VERSION 5.7 ;
BUSBITCHARS "[]" ;
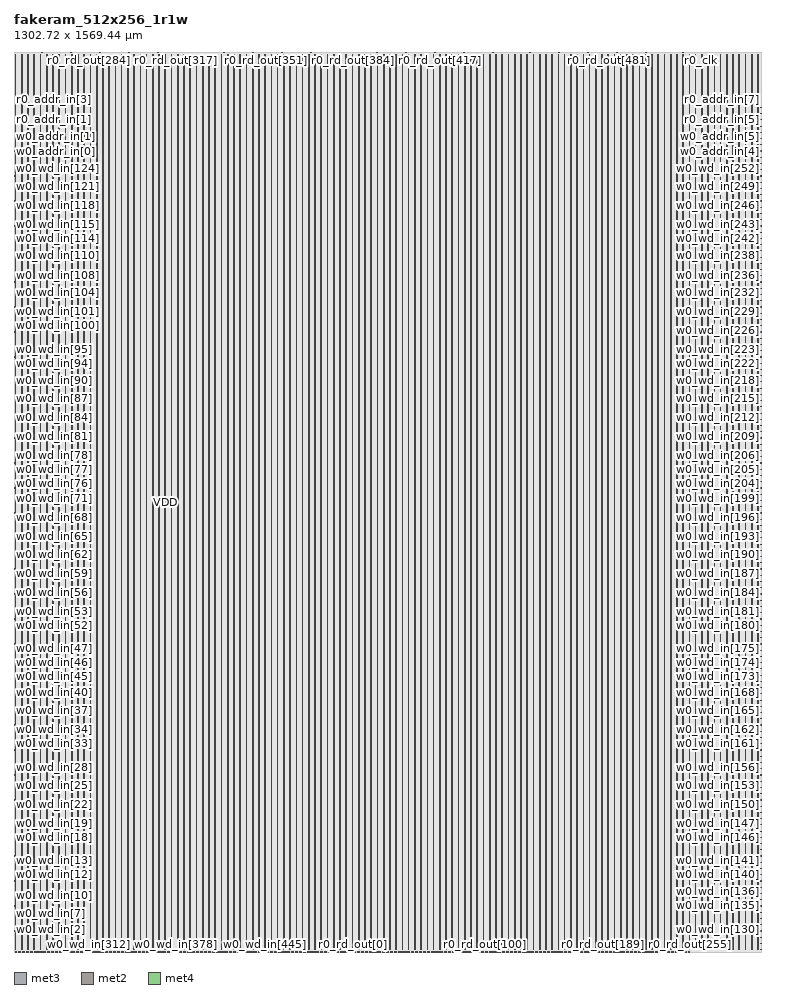
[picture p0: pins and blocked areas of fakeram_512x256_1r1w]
MACRO fakeram_512x256_1r1w
  FOREIGN fakeram_512x256_1r1w 0 0 ;
  SYMMETRY X Y R90 ;
  SIZE 1302.720 BY 1569.440 ;
  CLASS BLOCK ;
  PIN w0_wd_in[0]
    DIRECTION INPUT ;
    USE SIGNAL ;
    SHAPE ABUTMENT ;
    PORT
      LAYER met3 ;
      RECT 0.000 3.930 0.900 4.230 ;
    END
  END w0_wd_in[0]
  PIN w0_wd_in[1]
    DIRECTION INPUT ;
    USE SIGNAL ;
    SHAPE ABUTMENT ;
    PORT
      LAYER met3 ;
      RECT 0.000 14.810 0.900 15.110 ;
    END
  END w0_wd_in[1]
  PIN w0_wd_in[2]
    DIRECTION INPUT ;
    USE SIGNAL ;
    SHAPE ABUTMENT ;
    PORT
      LAYER met3 ;
      RECT 0.000 25.690 0.900 25.990 ;
    END
  END w0_wd_in[2]
  PIN w0_wd_in[3]
    DIRECTION INPUT ;
    USE SIGNAL ;
    SHAPE ABUTMENT ;
    PORT
      LAYER met3 ;
      RECT 0.000 36.570 0.900 36.870 ;
    END
  END w0_wd_in[3]
  PIN w0_wd_in[4]
    DIRECTION INPUT ;
    USE SIGNAL ;
    SHAPE ABUTMENT ;
    PORT
      LAYER met3 ;
      RECT 0.000 47.450 0.900 47.750 ;
    END
  END w0_wd_in[4]
  PIN w0_wd_in[5]
    DIRECTION INPUT ;
    USE SIGNAL ;
    SHAPE ABUTMENT ;
    PORT
      LAYER met3 ;
      RECT 0.000 58.330 0.900 58.630 ;
    END
  END w0_wd_in[5]
  PIN w0_wd_in[6]
    DIRECTION INPUT ;
    USE SIGNAL ;
    SHAPE ABUTMENT ;
    PORT
      LAYER met3 ;
      RECT 0.000 69.210 0.900 69.510 ;
    END
  END w0_wd_in[6]
  PIN w0_wd_in[7]
    DIRECTION INPUT ;
    USE SIGNAL ;
    SHAPE ABUTMENT ;
    PORT
      LAYER met3 ;
      RECT 0.000 80.090 0.900 80.390 ;
    END
  END w0_wd_in[7]
  PIN w0_wd_in[8]
    DIRECTION INPUT ;
    USE SIGNAL ;
    SHAPE ABUTMENT ;
    PORT
      LAYER met3 ;
      RECT 0.000 90.970 0.900 91.270 ;
    END
  END w0_wd_in[8]
  PIN w0_wd_in[9]
    DIRECTION INPUT ;
    USE SIGNAL ;
    SHAPE ABUTMENT ;
    PORT
      LAYER met3 ;
      RECT 0.000 101.850 0.900 102.150 ;
    END
  END w0_wd_in[9]
  PIN w0_wd_in[10]
    DIRECTION INPUT ;
    USE SIGNAL ;
    SHAPE ABUTMENT ;
    PORT
      LAYER met3 ;
      RECT 0.000 112.730 0.900 113.030 ;
    END
  END w0_wd_in[10]
  PIN w0_wd_in[11]
    DIRECTION INPUT ;
    USE SIGNAL ;
    SHAPE ABUTMENT ;
    PORT
      LAYER met3 ;
      RECT 0.000 123.610 0.900 123.910 ;
    END
  END w0_wd_in[11]
  PIN w0_wd_in[12]
    DIRECTION INPUT ;
    USE SIGNAL ;
    SHAPE ABUTMENT ;
    PORT
      LAYER met3 ;
      RECT 0.000 134.490 0.900 134.790 ;
    END
  END w0_wd_in[12]
  PIN w0_wd_in[13]
    DIRECTION INPUT ;
    USE SIGNAL ;
    SHAPE ABUTMENT ;
    PORT
      LAYER met3 ;
      RECT 0.000 145.370 0.900 145.670 ;
    END
  END w0_wd_in[13]
  PIN w0_wd_in[14]
    DIRECTION INPUT ;
    USE SIGNAL ;
    SHAPE ABUTMENT ;
    PORT
      LAYER met3 ;
      RECT 0.000 156.250 0.900 156.550 ;
    END
  END w0_wd_in[14]
  PIN w0_wd_in[15]
    DIRECTION INPUT ;
    USE SIGNAL ;
    SHAPE ABUTMENT ;
    PORT
      LAYER met3 ;
      RECT 0.000 167.130 0.900 167.430 ;
    END
  END w0_wd_in[15]
  PIN w0_wd_in[16]
    DIRECTION INPUT ;
    USE SIGNAL ;
    SHAPE ABUTMENT ;
    PORT
      LAYER met3 ;
      RECT 0.000 178.010 0.900 178.310 ;
    END
  END w0_wd_in[16]
  PIN w0_wd_in[17]
    DIRECTION INPUT ;
    USE SIGNAL ;
    SHAPE ABUTMENT ;
    PORT
      LAYER met3 ;
      RECT 0.000 188.890 0.900 189.190 ;
    END
  END w0_wd_in[17]
  PIN w0_wd_in[18]
    DIRECTION INPUT ;
    USE SIGNAL ;
    SHAPE ABUTMENT ;
    PORT
      LAYER met3 ;
      RECT 0.000 199.770 0.900 200.070 ;
    END
  END w0_wd_in[18]
  PIN w0_wd_in[19]
    DIRECTION INPUT ;
    USE SIGNAL ;
    SHAPE ABUTMENT ;
    PORT
      LAYER met3 ;
      RECT 0.000 210.650 0.900 210.950 ;
    END
  END w0_wd_in[19]
  PIN w0_wd_in[20]
    DIRECTION INPUT ;
    USE SIGNAL ;
    SHAPE ABUTMENT ;
    PORT
      LAYER met3 ;
      RECT 0.000 221.530 0.900 221.830 ;
    END
  END w0_wd_in[20]
  PIN w0_wd_in[21]
    DIRECTION INPUT ;
    USE SIGNAL ;
    SHAPE ABUTMENT ;
    PORT
      LAYER met3 ;
      RECT 0.000 232.410 0.900 232.710 ;
    END
  END w0_wd_in[21]
  PIN w0_wd_in[22]
    DIRECTION INPUT ;
    USE SIGNAL ;
    SHAPE ABUTMENT ;
    PORT
      LAYER met3 ;
      RECT 0.000 243.290 0.900 243.590 ;
    END
  END w0_wd_in[22]
  PIN w0_wd_in[23]
    DIRECTION INPUT ;
    USE SIGNAL ;
    SHAPE ABUTMENT ;
    PORT
      LAYER met3 ;
      RECT 0.000 254.170 0.900 254.470 ;
    END
  END w0_wd_in[23]
  PIN w0_wd_in[24]
    DIRECTION INPUT ;
    USE SIGNAL ;
    SHAPE ABUTMENT ;
    PORT
      LAYER met3 ;
      RECT 0.000 265.050 0.900 265.350 ;
    END
  END w0_wd_in[24]
  PIN w0_wd_in[25]
    DIRECTION INPUT ;
    USE SIGNAL ;
    SHAPE ABUTMENT ;
    PORT
      LAYER met3 ;
      RECT 0.000 275.930 0.900 276.230 ;
    END
  END w0_wd_in[25]
  PIN w0_wd_in[26]
    DIRECTION INPUT ;
    USE SIGNAL ;
    SHAPE ABUTMENT ;
    PORT
      LAYER met3 ;
      RECT 0.000 286.810 0.900 287.110 ;
    END
  END w0_wd_in[26]
  PIN w0_wd_in[27]
    DIRECTION INPUT ;
    USE SIGNAL ;
    SHAPE ABUTMENT ;
    PORT
      LAYER met3 ;
      RECT 0.000 297.690 0.900 297.990 ;
    END
  END w0_wd_in[27]
  PIN w0_wd_in[28]
    DIRECTION INPUT ;
    USE SIGNAL ;
    SHAPE ABUTMENT ;
    PORT
      LAYER met3 ;
      RECT 0.000 308.570 0.900 308.870 ;
    END
  END w0_wd_in[28]
  PIN w0_wd_in[29]
    DIRECTION INPUT ;
    USE SIGNAL ;
    SHAPE ABUTMENT ;
    PORT
      LAYER met3 ;
      RECT 0.000 319.450 0.900 319.750 ;
    END
  END w0_wd_in[29]
  PIN w0_wd_in[30]
    DIRECTION INPUT ;
    USE SIGNAL ;
    SHAPE ABUTMENT ;
    PORT
      LAYER met3 ;
      RECT 0.000 330.330 0.900 330.630 ;
    END
  END w0_wd_in[30]
  PIN w0_wd_in[31]
    DIRECTION INPUT ;
    USE SIGNAL ;
    SHAPE ABUTMENT ;
    PORT
      LAYER met3 ;
      RECT 0.000 341.210 0.900 341.510 ;
    END
  END w0_wd_in[31]
  PIN w0_wd_in[32]
    DIRECTION INPUT ;
    USE SIGNAL ;
    SHAPE ABUTMENT ;
    PORT
      LAYER met3 ;
      RECT 0.000 352.090 0.900 352.390 ;
    END
  END w0_wd_in[32]
  PIN w0_wd_in[33]
    DIRECTION INPUT ;
    USE SIGNAL ;
    SHAPE ABUTMENT ;
    PORT
      LAYER met3 ;
      RECT 0.000 362.970 0.900 363.270 ;
    END
  END w0_wd_in[33]
  PIN w0_wd_in[34]
    DIRECTION INPUT ;
    USE SIGNAL ;
    SHAPE ABUTMENT ;
    PORT
      LAYER met3 ;
      RECT 0.000 373.850 0.900 374.150 ;
    END
  END w0_wd_in[34]
  PIN w0_wd_in[35]
    DIRECTION INPUT ;
    USE SIGNAL ;
    SHAPE ABUTMENT ;
    PORT
      LAYER met3 ;
      RECT 0.000 384.730 0.900 385.030 ;
    END
  END w0_wd_in[35]
  PIN w0_wd_in[36]
    DIRECTION INPUT ;
    USE SIGNAL ;
    SHAPE ABUTMENT ;
    PORT
      LAYER met3 ;
      RECT 0.000 395.610 0.900 395.910 ;
    END
  END w0_wd_in[36]
  PIN w0_wd_in[37]
    DIRECTION INPUT ;
    USE SIGNAL ;
    SHAPE ABUTMENT ;
    PORT
      LAYER met3 ;
      RECT 0.000 406.490 0.900 406.790 ;
    END
  END w0_wd_in[37]
  PIN w0_wd_in[38]
    DIRECTION INPUT ;
    USE SIGNAL ;
    SHAPE ABUTMENT ;
    PORT
      LAYER met3 ;
      RECT 0.000 417.370 0.900 417.670 ;
    END
  END w0_wd_in[38]
  PIN w0_wd_in[39]
    DIRECTION INPUT ;
    USE SIGNAL ;
    SHAPE ABUTMENT ;
    PORT
      LAYER met3 ;
      RECT 0.000 428.250 0.900 428.550 ;
    END
  END w0_wd_in[39]
  PIN w0_wd_in[40]
    DIRECTION INPUT ;
    USE SIGNAL ;
    SHAPE ABUTMENT ;
    PORT
      LAYER met3 ;
      RECT 0.000 439.130 0.900 439.430 ;
    END
  END w0_wd_in[40]
  PIN w0_wd_in[41]
    DIRECTION INPUT ;
    USE SIGNAL ;
    SHAPE ABUTMENT ;
    PORT
      LAYER met3 ;
      RECT 0.000 450.010 0.900 450.310 ;
    END
  END w0_wd_in[41]
  PIN w0_wd_in[42]
    DIRECTION INPUT ;
    USE SIGNAL ;
    SHAPE ABUTMENT ;
    PORT
      LAYER met3 ;
      RECT 0.000 460.890 0.900 461.190 ;
    END
  END w0_wd_in[42]
  PIN w0_wd_in[43]
    DIRECTION INPUT ;
    USE SIGNAL ;
    SHAPE ABUTMENT ;
    PORT
      LAYER met3 ;
      RECT 0.000 471.770 0.900 472.070 ;
    END
  END w0_wd_in[43]
  PIN w0_wd_in[44]
    DIRECTION INPUT ;
    USE SIGNAL ;
    SHAPE ABUTMENT ;
    PORT
      LAYER met3 ;
      RECT 0.000 482.650 0.900 482.950 ;
    END
  END w0_wd_in[44]
  PIN w0_wd_in[45]
    DIRECTION INPUT ;
    USE SIGNAL ;
    SHAPE ABUTMENT ;
    PORT
      LAYER met3 ;
      RECT 0.000 493.530 0.900 493.830 ;
    END
  END w0_wd_in[45]
  PIN w0_wd_in[46]
    DIRECTION INPUT ;
    USE SIGNAL ;
    SHAPE ABUTMENT ;
    PORT
      LAYER met3 ;
      RECT 0.000 504.410 0.900 504.710 ;
    END
  END w0_wd_in[46]
  PIN w0_wd_in[47]
    DIRECTION INPUT ;
    USE SIGNAL ;
    SHAPE ABUTMENT ;
    PORT
      LAYER met3 ;
      RECT 0.000 515.290 0.900 515.590 ;
    END
  END w0_wd_in[47]
  PIN w0_wd_in[48]
    DIRECTION INPUT ;
    USE SIGNAL ;
    SHAPE ABUTMENT ;
    PORT
      LAYER met3 ;
      RECT 0.000 526.170 0.900 526.470 ;
    END
  END w0_wd_in[48]
  PIN w0_wd_in[49]
    DIRECTION INPUT ;
    USE SIGNAL ;
    SHAPE ABUTMENT ;
    PORT
      LAYER met3 ;
      RECT 0.000 537.050 0.900 537.350 ;
    END
  END w0_wd_in[49]
  PIN w0_wd_in[50]
    DIRECTION INPUT ;
    USE SIGNAL ;
    SHAPE ABUTMENT ;
    PORT
      LAYER met3 ;
      RECT 0.000 547.930 0.900 548.230 ;
    END
  END w0_wd_in[50]
  PIN w0_wd_in[51]
    DIRECTION INPUT ;
    USE SIGNAL ;
    SHAPE ABUTMENT ;
    PORT
      LAYER met3 ;
      RECT 0.000 558.810 0.900 559.110 ;
    END
  END w0_wd_in[51]
  PIN w0_wd_in[52]
    DIRECTION INPUT ;
    USE SIGNAL ;
    SHAPE ABUTMENT ;
    PORT
      LAYER met3 ;
      RECT 0.000 569.690 0.900 569.990 ;
    END
  END w0_wd_in[52]
  PIN w0_wd_in[53]
    DIRECTION INPUT ;
    USE SIGNAL ;
    SHAPE ABUTMENT ;
    PORT
      LAYER met3 ;
      RECT 0.000 580.570 0.900 580.870 ;
    END
  END w0_wd_in[53]
  PIN w0_wd_in[54]
    DIRECTION INPUT ;
    USE SIGNAL ;
    SHAPE ABUTMENT ;
    PORT
      LAYER met3 ;
      RECT 0.000 591.450 0.900 591.750 ;
    END
  END w0_wd_in[54]
  PIN w0_wd_in[55]
    DIRECTION INPUT ;
    USE SIGNAL ;
    SHAPE ABUTMENT ;
    PORT
      LAYER met3 ;
      RECT 0.000 602.330 0.900 602.630 ;
    END
  END w0_wd_in[55]
  PIN w0_wd_in[56]
    DIRECTION INPUT ;
    USE SIGNAL ;
    SHAPE ABUTMENT ;
    PORT
      LAYER met3 ;
      RECT 0.000 613.210 0.900 613.510 ;
    END
  END w0_wd_in[56]
  PIN w0_wd_in[57]
    DIRECTION INPUT ;
    USE SIGNAL ;
    SHAPE ABUTMENT ;
    PORT
      LAYER met3 ;
      RECT 0.000 624.090 0.900 624.390 ;
    END
  END w0_wd_in[57]
  PIN w0_wd_in[58]
    DIRECTION INPUT ;
    USE SIGNAL ;
    SHAPE ABUTMENT ;
    PORT
      LAYER met3 ;
      RECT 0.000 634.970 0.900 635.270 ;
    END
  END w0_wd_in[58]
  PIN w0_wd_in[59]
    DIRECTION INPUT ;
    USE SIGNAL ;
    SHAPE ABUTMENT ;
    PORT
      LAYER met3 ;
      RECT 0.000 645.850 0.900 646.150 ;
    END
  END w0_wd_in[59]
  PIN w0_wd_in[60]
    DIRECTION INPUT ;
    USE SIGNAL ;
    SHAPE ABUTMENT ;
    PORT
      LAYER met3 ;
      RECT 0.000 656.730 0.900 657.030 ;
    END
  END w0_wd_in[60]
  PIN w0_wd_in[61]
    DIRECTION INPUT ;
    USE SIGNAL ;
    SHAPE ABUTMENT ;
    PORT
      LAYER met3 ;
      RECT 0.000 667.610 0.900 667.910 ;
    END
  END w0_wd_in[61]
  PIN w0_wd_in[62]
    DIRECTION INPUT ;
    USE SIGNAL ;
    SHAPE ABUTMENT ;
    PORT
      LAYER met3 ;
      RECT 0.000 678.490 0.900 678.790 ;
    END
  END w0_wd_in[62]
  PIN w0_wd_in[63]
    DIRECTION INPUT ;
    USE SIGNAL ;
    SHAPE ABUTMENT ;
    PORT
      LAYER met3 ;
      RECT 0.000 689.370 0.900 689.670 ;
    END
  END w0_wd_in[63]
  PIN w0_wd_in[64]
    DIRECTION INPUT ;
    USE SIGNAL ;
    SHAPE ABUTMENT ;
    PORT
      LAYER met3 ;
      RECT 0.000 700.250 0.900 700.550 ;
    END
  END w0_wd_in[64]
  PIN w0_wd_in[65]
    DIRECTION INPUT ;
    USE SIGNAL ;
    SHAPE ABUTMENT ;
    PORT
      LAYER met3 ;
      RECT 0.000 711.130 0.900 711.430 ;
    END
  END w0_wd_in[65]
  PIN w0_wd_in[66]
    DIRECTION INPUT ;
    USE SIGNAL ;
    SHAPE ABUTMENT ;
    PORT
      LAYER met3 ;
      RECT 0.000 722.010 0.900 722.310 ;
    END
  END w0_wd_in[66]
  PIN w0_wd_in[67]
    DIRECTION INPUT ;
    USE SIGNAL ;
    SHAPE ABUTMENT ;
    PORT
      LAYER met3 ;
      RECT 0.000 732.890 0.900 733.190 ;
    END
  END w0_wd_in[67]
  PIN w0_wd_in[68]
    DIRECTION INPUT ;
    USE SIGNAL ;
    SHAPE ABUTMENT ;
    PORT
      LAYER met3 ;
      RECT 0.000 743.770 0.900 744.070 ;
    END
  END w0_wd_in[68]
  PIN w0_wd_in[69]
    DIRECTION INPUT ;
    USE SIGNAL ;
    SHAPE ABUTMENT ;
    PORT
      LAYER met3 ;
      RECT 0.000 754.650 0.900 754.950 ;
    END
  END w0_wd_in[69]
  PIN w0_wd_in[70]
    DIRECTION INPUT ;
    USE SIGNAL ;
    SHAPE ABUTMENT ;
    PORT
      LAYER met3 ;
      RECT 0.000 765.530 0.900 765.830 ;
    END
  END w0_wd_in[70]
  PIN w0_wd_in[71]
    DIRECTION INPUT ;
    USE SIGNAL ;
    SHAPE ABUTMENT ;
    PORT
      LAYER met3 ;
      RECT 0.000 776.410 0.900 776.710 ;
    END
  END w0_wd_in[71]
  PIN w0_wd_in[72]
    DIRECTION INPUT ;
    USE SIGNAL ;
    SHAPE ABUTMENT ;
    PORT
      LAYER met3 ;
      RECT 0.000 787.290 0.900 787.590 ;
    END
  END w0_wd_in[72]
  PIN w0_wd_in[73]
    DIRECTION INPUT ;
    USE SIGNAL ;
    SHAPE ABUTMENT ;
    PORT
      LAYER met3 ;
      RECT 0.000 798.170 0.900 798.470 ;
    END
  END w0_wd_in[73]
  PIN w0_wd_in[74]
    DIRECTION INPUT ;
    USE SIGNAL ;
    SHAPE ABUTMENT ;
    PORT
      LAYER met3 ;
      RECT 0.000 809.050 0.900 809.350 ;
    END
  END w0_wd_in[74]
  PIN w0_wd_in[75]
    DIRECTION INPUT ;
    USE SIGNAL ;
    SHAPE ABUTMENT ;
    PORT
      LAYER met3 ;
      RECT 0.000 819.930 0.900 820.230 ;
    END
  END w0_wd_in[75]
  PIN w0_wd_in[76]
    DIRECTION INPUT ;
    USE SIGNAL ;
    SHAPE ABUTMENT ;
    PORT
      LAYER met3 ;
      RECT 0.000 830.810 0.900 831.110 ;
    END
  END w0_wd_in[76]
  PIN w0_wd_in[77]
    DIRECTION INPUT ;
    USE SIGNAL ;
    SHAPE ABUTMENT ;
    PORT
      LAYER met3 ;
      RECT 0.000 841.690 0.900 841.990 ;
    END
  END w0_wd_in[77]
  PIN w0_wd_in[78]
    DIRECTION INPUT ;
    USE SIGNAL ;
    SHAPE ABUTMENT ;
    PORT
      LAYER met3 ;
      RECT 0.000 852.570 0.900 852.870 ;
    END
  END w0_wd_in[78]
  PIN w0_wd_in[79]
    DIRECTION INPUT ;
    USE SIGNAL ;
    SHAPE ABUTMENT ;
    PORT
      LAYER met3 ;
      RECT 0.000 863.450 0.900 863.750 ;
    END
  END w0_wd_in[79]
  PIN w0_wd_in[80]
    DIRECTION INPUT ;
    USE SIGNAL ;
    SHAPE ABUTMENT ;
    PORT
      LAYER met3 ;
      RECT 0.000 874.330 0.900 874.630 ;
    END
  END w0_wd_in[80]
  PIN w0_wd_in[81]
    DIRECTION INPUT ;
    USE SIGNAL ;
    SHAPE ABUTMENT ;
    PORT
      LAYER met3 ;
      RECT 0.000 885.210 0.900 885.510 ;
    END
  END w0_wd_in[81]
  PIN w0_wd_in[82]
    DIRECTION INPUT ;
    USE SIGNAL ;
    SHAPE ABUTMENT ;
    PORT
      LAYER met3 ;
      RECT 0.000 896.090 0.900 896.390 ;
    END
  END w0_wd_in[82]
  PIN w0_wd_in[83]
    DIRECTION INPUT ;
    USE SIGNAL ;
    SHAPE ABUTMENT ;
    PORT
      LAYER met3 ;
      RECT 0.000 906.970 0.900 907.270 ;
    END
  END w0_wd_in[83]
  PIN w0_wd_in[84]
    DIRECTION INPUT ;
    USE SIGNAL ;
    SHAPE ABUTMENT ;
    PORT
      LAYER met3 ;
      RECT 0.000 917.850 0.900 918.150 ;
    END
  END w0_wd_in[84]
  PIN w0_wd_in[85]
    DIRECTION INPUT ;
    USE SIGNAL ;
    SHAPE ABUTMENT ;
    PORT
      LAYER met3 ;
      RECT 0.000 928.730 0.900 929.030 ;
    END
  END w0_wd_in[85]
  PIN w0_wd_in[86]
    DIRECTION INPUT ;
    USE SIGNAL ;
    SHAPE ABUTMENT ;
    PORT
      LAYER met3 ;
      RECT 0.000 939.610 0.900 939.910 ;
    END
  END w0_wd_in[86]
  PIN w0_wd_in[87]
    DIRECTION INPUT ;
    USE SIGNAL ;
    SHAPE ABUTMENT ;
    PORT
      LAYER met3 ;
      RECT 0.000 950.490 0.900 950.790 ;
    END
  END w0_wd_in[87]
  PIN w0_wd_in[88]
    DIRECTION INPUT ;
    USE SIGNAL ;
    SHAPE ABUTMENT ;
    PORT
      LAYER met3 ;
      RECT 0.000 961.370 0.900 961.670 ;
    END
  END w0_wd_in[88]
  PIN w0_wd_in[89]
    DIRECTION INPUT ;
    USE SIGNAL ;
    SHAPE ABUTMENT ;
    PORT
      LAYER met3 ;
      RECT 0.000 972.250 0.900 972.550 ;
    END
  END w0_wd_in[89]
  PIN w0_wd_in[90]
    DIRECTION INPUT ;
    USE SIGNAL ;
    SHAPE ABUTMENT ;
    PORT
      LAYER met3 ;
      RECT 0.000 983.130 0.900 983.430 ;
    END
  END w0_wd_in[90]
  PIN w0_wd_in[91]
    DIRECTION INPUT ;
    USE SIGNAL ;
    SHAPE ABUTMENT ;
    PORT
      LAYER met3 ;
      RECT 0.000 994.010 0.900 994.310 ;
    END
  END w0_wd_in[91]
  PIN w0_wd_in[92]
    DIRECTION INPUT ;
    USE SIGNAL ;
    SHAPE ABUTMENT ;
    PORT
      LAYER met3 ;
      RECT 0.000 1004.890 0.900 1005.190 ;
    END
  END w0_wd_in[92]
  PIN w0_wd_in[93]
    DIRECTION INPUT ;
    USE SIGNAL ;
    SHAPE ABUTMENT ;
    PORT
      LAYER met3 ;
      RECT 0.000 1015.770 0.900 1016.070 ;
    END
  END w0_wd_in[93]
  PIN w0_wd_in[94]
    DIRECTION INPUT ;
    USE SIGNAL ;
    SHAPE ABUTMENT ;
    PORT
      LAYER met3 ;
      RECT 0.000 1026.650 0.900 1026.950 ;
    END
  END w0_wd_in[94]
  PIN w0_wd_in[95]
    DIRECTION INPUT ;
    USE SIGNAL ;
    SHAPE ABUTMENT ;
    PORT
      LAYER met3 ;
      RECT 0.000 1037.530 0.900 1037.830 ;
    END
  END w0_wd_in[95]
  PIN w0_wd_in[96]
    DIRECTION INPUT ;
    USE SIGNAL ;
    SHAPE ABUTMENT ;
    PORT
      LAYER met3 ;
      RECT 0.000 1048.410 0.900 1048.710 ;
    END
  END w0_wd_in[96]
  PIN w0_wd_in[97]
    DIRECTION INPUT ;
    USE SIGNAL ;
    SHAPE ABUTMENT ;
    PORT
      LAYER met3 ;
      RECT 0.000 1059.290 0.900 1059.590 ;
    END
  END w0_wd_in[97]
  PIN w0_wd_in[98]
    DIRECTION INPUT ;
    USE SIGNAL ;
    SHAPE ABUTMENT ;
    PORT
      LAYER met3 ;
      RECT 0.000 1070.170 0.900 1070.470 ;
    END
  END w0_wd_in[98]
  PIN w0_wd_in[99]
    DIRECTION INPUT ;
    USE SIGNAL ;
    SHAPE ABUTMENT ;
    PORT
      LAYER met3 ;
      RECT 0.000 1081.050 0.900 1081.350 ;
    END
  END w0_wd_in[99]
  PIN w0_wd_in[100]
    DIRECTION INPUT ;
    USE SIGNAL ;
    SHAPE ABUTMENT ;
    PORT
      LAYER met3 ;
      RECT 0.000 1091.930 0.900 1092.230 ;
    END
  END w0_wd_in[100]
  PIN w0_wd_in[101]
    DIRECTION INPUT ;
    USE SIGNAL ;
    SHAPE ABUTMENT ;
    PORT
      LAYER met3 ;
      RECT 0.000 1102.810 0.900 1103.110 ;
    END
  END w0_wd_in[101]
  PIN w0_wd_in[102]
    DIRECTION INPUT ;
    USE SIGNAL ;
    SHAPE ABUTMENT ;
    PORT
      LAYER met3 ;
      RECT 0.000 1113.690 0.900 1113.990 ;
    END
  END w0_wd_in[102]
  PIN w0_wd_in[103]
    DIRECTION INPUT ;
    USE SIGNAL ;
    SHAPE ABUTMENT ;
    PORT
      LAYER met3 ;
      RECT 0.000 1124.570 0.900 1124.870 ;
    END
  END w0_wd_in[103]
  PIN w0_wd_in[104]
    DIRECTION INPUT ;
    USE SIGNAL ;
    SHAPE ABUTMENT ;
    PORT
      LAYER met3 ;
      RECT 0.000 1135.450 0.900 1135.750 ;
    END
  END w0_wd_in[104]
  PIN w0_wd_in[105]
    DIRECTION INPUT ;
    USE SIGNAL ;
    SHAPE ABUTMENT ;
    PORT
      LAYER met3 ;
      RECT 0.000 1146.330 0.900 1146.630 ;
    END
  END w0_wd_in[105]
  PIN w0_wd_in[106]
    DIRECTION INPUT ;
    USE SIGNAL ;
    SHAPE ABUTMENT ;
    PORT
      LAYER met3 ;
      RECT 0.000 1157.210 0.900 1157.510 ;
    END
  END w0_wd_in[106]
  PIN w0_wd_in[107]
    DIRECTION INPUT ;
    USE SIGNAL ;
    SHAPE ABUTMENT ;
    PORT
      LAYER met3 ;
      RECT 0.000 1168.090 0.900 1168.390 ;
    END
  END w0_wd_in[107]
  PIN w0_wd_in[108]
    DIRECTION INPUT ;
    USE SIGNAL ;
    SHAPE ABUTMENT ;
    PORT
      LAYER met3 ;
      RECT 0.000 1178.970 0.900 1179.270 ;
    END
  END w0_wd_in[108]
  PIN w0_wd_in[109]
    DIRECTION INPUT ;
    USE SIGNAL ;
    SHAPE ABUTMENT ;
    PORT
      LAYER met3 ;
      RECT 0.000 1189.850 0.900 1190.150 ;
    END
  END w0_wd_in[109]
  PIN w0_wd_in[110]
    DIRECTION INPUT ;
    USE SIGNAL ;
    SHAPE ABUTMENT ;
    PORT
      LAYER met3 ;
      RECT 0.000 1200.730 0.900 1201.030 ;
    END
  END w0_wd_in[110]
  PIN w0_wd_in[111]
    DIRECTION INPUT ;
    USE SIGNAL ;
    SHAPE ABUTMENT ;
    PORT
      LAYER met3 ;
      RECT 0.000 1211.610 0.900 1211.910 ;
    END
  END w0_wd_in[111]
  PIN w0_wd_in[112]
    DIRECTION INPUT ;
    USE SIGNAL ;
    SHAPE ABUTMENT ;
    PORT
      LAYER met3 ;
      RECT 0.000 1222.490 0.900 1222.790 ;
    END
  END w0_wd_in[112]
  PIN w0_wd_in[113]
    DIRECTION INPUT ;
    USE SIGNAL ;
    SHAPE ABUTMENT ;
    PORT
      LAYER met3 ;
      RECT 0.000 1233.370 0.900 1233.670 ;
    END
  END w0_wd_in[113]
  PIN w0_wd_in[114]
    DIRECTION INPUT ;
    USE SIGNAL ;
    SHAPE ABUTMENT ;
    PORT
      LAYER met3 ;
      RECT 0.000 1244.250 0.900 1244.550 ;
    END
  END w0_wd_in[114]
  PIN w0_wd_in[115]
    DIRECTION INPUT ;
    USE SIGNAL ;
    SHAPE ABUTMENT ;
    PORT
      LAYER met3 ;
      RECT 0.000 1255.130 0.900 1255.430 ;
    END
  END w0_wd_in[115]
  PIN w0_wd_in[116]
    DIRECTION INPUT ;
    USE SIGNAL ;
    SHAPE ABUTMENT ;
    PORT
      LAYER met3 ;
      RECT 0.000 1266.010 0.900 1266.310 ;
    END
  END w0_wd_in[116]
  PIN w0_wd_in[117]
    DIRECTION INPUT ;
    USE SIGNAL ;
    SHAPE ABUTMENT ;
    PORT
      LAYER met3 ;
      RECT 0.000 1276.890 0.900 1277.190 ;
    END
  END w0_wd_in[117]
  PIN w0_wd_in[118]
    DIRECTION INPUT ;
    USE SIGNAL ;
    SHAPE ABUTMENT ;
    PORT
      LAYER met3 ;
      RECT 0.000 1287.770 0.900 1288.070 ;
    END
  END w0_wd_in[118]
  PIN w0_wd_in[119]
    DIRECTION INPUT ;
    USE SIGNAL ;
    SHAPE ABUTMENT ;
    PORT
      LAYER met3 ;
      RECT 0.000 1298.650 0.900 1298.950 ;
    END
  END w0_wd_in[119]
  PIN w0_wd_in[120]
    DIRECTION INPUT ;
    USE SIGNAL ;
    SHAPE ABUTMENT ;
    PORT
      LAYER met3 ;
      RECT 0.000 1309.530 0.900 1309.830 ;
    END
  END w0_wd_in[120]
  PIN w0_wd_in[121]
    DIRECTION INPUT ;
    USE SIGNAL ;
    SHAPE ABUTMENT ;
    PORT
      LAYER met3 ;
      RECT 0.000 1320.410 0.900 1320.710 ;
    END
  END w0_wd_in[121]
  PIN w0_wd_in[122]
    DIRECTION INPUT ;
    USE SIGNAL ;
    SHAPE ABUTMENT ;
    PORT
      LAYER met3 ;
      RECT 0.000 1331.290 0.900 1331.590 ;
    END
  END w0_wd_in[122]
  PIN w0_wd_in[123]
    DIRECTION INPUT ;
    USE SIGNAL ;
    SHAPE ABUTMENT ;
    PORT
      LAYER met3 ;
      RECT 0.000 1342.170 0.900 1342.470 ;
    END
  END w0_wd_in[123]
  PIN w0_wd_in[124]
    DIRECTION INPUT ;
    USE SIGNAL ;
    SHAPE ABUTMENT ;
    PORT
      LAYER met3 ;
      RECT 0.000 1353.050 0.900 1353.350 ;
    END
  END w0_wd_in[124]
  PIN w0_wd_in[125]
    DIRECTION INPUT ;
    USE SIGNAL ;
    SHAPE ABUTMENT ;
    PORT
      LAYER met3 ;
      RECT 0.000 1363.930 0.900 1364.230 ;
    END
  END w0_wd_in[125]
  PIN w0_wd_in[126]
    DIRECTION INPUT ;
    USE SIGNAL ;
    SHAPE ABUTMENT ;
    PORT
      LAYER met3 ;
      RECT 0.000 1374.810 0.900 1375.110 ;
    END
  END w0_wd_in[126]
  PIN w0_wd_in[127]
    DIRECTION INPUT ;
    USE SIGNAL ;
    SHAPE ABUTMENT ;
    PORT
      LAYER met3 ;
      RECT 0.000 1385.690 0.900 1385.990 ;
    END
  END w0_wd_in[127]
  PIN w0_wd_in[128]
    DIRECTION INPUT ;
    USE SIGNAL ;
    SHAPE ABUTMENT ;
    PORT
      LAYER met3 ;
      RECT 1301.820 3.930 1302.720 4.230 ;
    END
  END w0_wd_in[128]
  PIN w0_wd_in[129]
    DIRECTION INPUT ;
    USE SIGNAL ;
    SHAPE ABUTMENT ;
    PORT
      LAYER met3 ;
      RECT 1301.820 14.810 1302.720 15.110 ;
    END
  END w0_wd_in[129]
  PIN w0_wd_in[130]
    DIRECTION INPUT ;
    USE SIGNAL ;
    SHAPE ABUTMENT ;
    PORT
      LAYER met3 ;
      RECT 1301.820 25.690 1302.720 25.990 ;
    END
  END w0_wd_in[130]
  PIN w0_wd_in[131]
    DIRECTION INPUT ;
    USE SIGNAL ;
    SHAPE ABUTMENT ;
    PORT
      LAYER met3 ;
      RECT 1301.820 36.570 1302.720 36.870 ;
    END
  END w0_wd_in[131]
  PIN w0_wd_in[132]
    DIRECTION INPUT ;
    USE SIGNAL ;
    SHAPE ABUTMENT ;
    PORT
      LAYER met3 ;
      RECT 1301.820 47.450 1302.720 47.750 ;
    END
  END w0_wd_in[132]
  PIN w0_wd_in[133]
    DIRECTION INPUT ;
    USE SIGNAL ;
    SHAPE ABUTMENT ;
    PORT
      LAYER met3 ;
      RECT 1301.820 58.330 1302.720 58.630 ;
    END
  END w0_wd_in[133]
  PIN w0_wd_in[134]
    DIRECTION INPUT ;
    USE SIGNAL ;
    SHAPE ABUTMENT ;
    PORT
      LAYER met3 ;
      RECT 1301.820 69.210 1302.720 69.510 ;
    END
  END w0_wd_in[134]
  PIN w0_wd_in[135]
    DIRECTION INPUT ;
    USE SIGNAL ;
    SHAPE ABUTMENT ;
    PORT
      LAYER met3 ;
      RECT 1301.820 80.090 1302.720 80.390 ;
    END
  END w0_wd_in[135]
  PIN w0_wd_in[136]
    DIRECTION INPUT ;
    USE SIGNAL ;
    SHAPE ABUTMENT ;
    PORT
      LAYER met3 ;
      RECT 1301.820 90.970 1302.720 91.270 ;
    END
  END w0_wd_in[136]
  PIN w0_wd_in[137]
    DIRECTION INPUT ;
    USE SIGNAL ;
    SHAPE ABUTMENT ;
    PORT
      LAYER met3 ;
      RECT 1301.820 101.850 1302.720 102.150 ;
    END
  END w0_wd_in[137]
  PIN w0_wd_in[138]
    DIRECTION INPUT ;
    USE SIGNAL ;
    SHAPE ABUTMENT ;
    PORT
      LAYER met3 ;
      RECT 1301.820 112.730 1302.720 113.030 ;
    END
  END w0_wd_in[138]
  PIN w0_wd_in[139]
    DIRECTION INPUT ;
    USE SIGNAL ;
    SHAPE ABUTMENT ;
    PORT
      LAYER met3 ;
      RECT 1301.820 123.610 1302.720 123.910 ;
    END
  END w0_wd_in[139]
  PIN w0_wd_in[140]
    DIRECTION INPUT ;
    USE SIGNAL ;
    SHAPE ABUTMENT ;
    PORT
      LAYER met3 ;
      RECT 1301.820 134.490 1302.720 134.790 ;
    END
  END w0_wd_in[140]
  PIN w0_wd_in[141]
    DIRECTION INPUT ;
    USE SIGNAL ;
    SHAPE ABUTMENT ;
    PORT
      LAYER met3 ;
      RECT 1301.820 145.370 1302.720 145.670 ;
    END
  END w0_wd_in[141]
  PIN w0_wd_in[142]
    DIRECTION INPUT ;
    USE SIGNAL ;
    SHAPE ABUTMENT ;
    PORT
      LAYER met3 ;
      RECT 1301.820 156.250 1302.720 156.550 ;
    END
  END w0_wd_in[142]
  PIN w0_wd_in[143]
    DIRECTION INPUT ;
    USE SIGNAL ;
    SHAPE ABUTMENT ;
    PORT
      LAYER met3 ;
      RECT 1301.820 167.130 1302.720 167.430 ;
    END
  END w0_wd_in[143]
  PIN w0_wd_in[144]
    DIRECTION INPUT ;
    USE SIGNAL ;
    SHAPE ABUTMENT ;
    PORT
      LAYER met3 ;
      RECT 1301.820 178.010 1302.720 178.310 ;
    END
  END w0_wd_in[144]
  PIN w0_wd_in[145]
    DIRECTION INPUT ;
    USE SIGNAL ;
    SHAPE ABUTMENT ;
    PORT
      LAYER met3 ;
      RECT 1301.820 188.890 1302.720 189.190 ;
    END
  END w0_wd_in[145]
  PIN w0_wd_in[146]
    DIRECTION INPUT ;
    USE SIGNAL ;
    SHAPE ABUTMENT ;
    PORT
      LAYER met3 ;
      RECT 1301.820 199.770 1302.720 200.070 ;
    END
  END w0_wd_in[146]
  PIN w0_wd_in[147]
    DIRECTION INPUT ;
    USE SIGNAL ;
    SHAPE ABUTMENT ;
    PORT
      LAYER met3 ;
      RECT 1301.820 210.650 1302.720 210.950 ;
    END
  END w0_wd_in[147]
  PIN w0_wd_in[148]
    DIRECTION INPUT ;
    USE SIGNAL ;
    SHAPE ABUTMENT ;
    PORT
      LAYER met3 ;
      RECT 1301.820 221.530 1302.720 221.830 ;
    END
  END w0_wd_in[148]
  PIN w0_wd_in[149]
    DIRECTION INPUT ;
    USE SIGNAL ;
    SHAPE ABUTMENT ;
    PORT
      LAYER met3 ;
      RECT 1301.820 232.410 1302.720 232.710 ;
    END
  END w0_wd_in[149]
  PIN w0_wd_in[150]
    DIRECTION INPUT ;
    USE SIGNAL ;
    SHAPE ABUTMENT ;
    PORT
      LAYER met3 ;
      RECT 1301.820 243.290 1302.720 243.590 ;
    END
  END w0_wd_in[150]
  PIN w0_wd_in[151]
    DIRECTION INPUT ;
    USE SIGNAL ;
    SHAPE ABUTMENT ;
    PORT
      LAYER met3 ;
      RECT 1301.820 254.170 1302.720 254.470 ;
    END
  END w0_wd_in[151]
  PIN w0_wd_in[152]
    DIRECTION INPUT ;
    USE SIGNAL ;
    SHAPE ABUTMENT ;
    PORT
      LAYER met3 ;
      RECT 1301.820 265.050 1302.720 265.350 ;
    END
  END w0_wd_in[152]
  PIN w0_wd_in[153]
    DIRECTION INPUT ;
    USE SIGNAL ;
    SHAPE ABUTMENT ;
    PORT
      LAYER met3 ;
      RECT 1301.820 275.930 1302.720 276.230 ;
    END
  END w0_wd_in[153]
  PIN w0_wd_in[154]
    DIRECTION INPUT ;
    USE SIGNAL ;
    SHAPE ABUTMENT ;
    PORT
      LAYER met3 ;
      RECT 1301.820 286.810 1302.720 287.110 ;
    END
  END w0_wd_in[154]
  PIN w0_wd_in[155]
    DIRECTION INPUT ;
    USE SIGNAL ;
    SHAPE ABUTMENT ;
    PORT
      LAYER met3 ;
      RECT 1301.820 297.690 1302.720 297.990 ;
    END
  END w0_wd_in[155]
  PIN w0_wd_in[156]
    DIRECTION INPUT ;
    USE SIGNAL ;
    SHAPE ABUTMENT ;
    PORT
      LAYER met3 ;
      RECT 1301.820 308.570 1302.720 308.870 ;
    END
  END w0_wd_in[156]
  PIN w0_wd_in[157]
    DIRECTION INPUT ;
    USE SIGNAL ;
    SHAPE ABUTMENT ;
    PORT
      LAYER met3 ;
      RECT 1301.820 319.450 1302.720 319.750 ;
    END
  END w0_wd_in[157]
  PIN w0_wd_in[158]
    DIRECTION INPUT ;
    USE SIGNAL ;
    SHAPE ABUTMENT ;
    PORT
      LAYER met3 ;
      RECT 1301.820 330.330 1302.720 330.630 ;
    END
  END w0_wd_in[158]
  PIN w0_wd_in[159]
    DIRECTION INPUT ;
    USE SIGNAL ;
    SHAPE ABUTMENT ;
    PORT
      LAYER met3 ;
      RECT 1301.820 341.210 1302.720 341.510 ;
    END
  END w0_wd_in[159]
  PIN w0_wd_in[160]
    DIRECTION INPUT ;
    USE SIGNAL ;
    SHAPE ABUTMENT ;
    PORT
      LAYER met3 ;
      RECT 1301.820 352.090 1302.720 352.390 ;
    END
  END w0_wd_in[160]
  PIN w0_wd_in[161]
    DIRECTION INPUT ;
    USE SIGNAL ;
    SHAPE ABUTMENT ;
    PORT
      LAYER met3 ;
      RECT 1301.820 362.970 1302.720 363.270 ;
    END
  END w0_wd_in[161]
  PIN w0_wd_in[162]
    DIRECTION INPUT ;
    USE SIGNAL ;
    SHAPE ABUTMENT ;
    PORT
      LAYER met3 ;
      RECT 1301.820 373.850 1302.720 374.150 ;
    END
  END w0_wd_in[162]
  PIN w0_wd_in[163]
    DIRECTION INPUT ;
    USE SIGNAL ;
    SHAPE ABUTMENT ;
    PORT
      LAYER met3 ;
      RECT 1301.820 384.730 1302.720 385.030 ;
    END
  END w0_wd_in[163]
  PIN w0_wd_in[164]
    DIRECTION INPUT ;
    USE SIGNAL ;
    SHAPE ABUTMENT ;
    PORT
      LAYER met3 ;
      RECT 1301.820 395.610 1302.720 395.910 ;
    END
  END w0_wd_in[164]
  PIN w0_wd_in[165]
    DIRECTION INPUT ;
    USE SIGNAL ;
    SHAPE ABUTMENT ;
    PORT
      LAYER met3 ;
      RECT 1301.820 406.490 1302.720 406.790 ;
    END
  END w0_wd_in[165]
  PIN w0_wd_in[166]
    DIRECTION INPUT ;
    USE SIGNAL ;
    SHAPE ABUTMENT ;
    PORT
      LAYER met3 ;
      RECT 1301.820 417.370 1302.720 417.670 ;
    END
  END w0_wd_in[166]
  PIN w0_wd_in[167]
    DIRECTION INPUT ;
    USE SIGNAL ;
    SHAPE ABUTMENT ;
    PORT
      LAYER met3 ;
      RECT 1301.820 428.250 1302.720 428.550 ;
    END
  END w0_wd_in[167]
  PIN w0_wd_in[168]
    DIRECTION INPUT ;
    USE SIGNAL ;
    SHAPE ABUTMENT ;
    PORT
      LAYER met3 ;
      RECT 1301.820 439.130 1302.720 439.430 ;
    END
  END w0_wd_in[168]
  PIN w0_wd_in[169]
    DIRECTION INPUT ;
    USE SIGNAL ;
    SHAPE ABUTMENT ;
    PORT
      LAYER met3 ;
      RECT 1301.820 450.010 1302.720 450.310 ;
    END
  END w0_wd_in[169]
  PIN w0_wd_in[170]
    DIRECTION INPUT ;
    USE SIGNAL ;
    SHAPE ABUTMENT ;
    PORT
      LAYER met3 ;
      RECT 1301.820 460.890 1302.720 461.190 ;
    END
  END w0_wd_in[170]
  PIN w0_wd_in[171]
    DIRECTION INPUT ;
    USE SIGNAL ;
    SHAPE ABUTMENT ;
    PORT
      LAYER met3 ;
      RECT 1301.820 471.770 1302.720 472.070 ;
    END
  END w0_wd_in[171]
  PIN w0_wd_in[172]
    DIRECTION INPUT ;
    USE SIGNAL ;
    SHAPE ABUTMENT ;
    PORT
      LAYER met3 ;
      RECT 1301.820 482.650 1302.720 482.950 ;
    END
  END w0_wd_in[172]
  PIN w0_wd_in[173]
    DIRECTION INPUT ;
    USE SIGNAL ;
    SHAPE ABUTMENT ;
    PORT
      LAYER met3 ;
      RECT 1301.820 493.530 1302.720 493.830 ;
    END
  END w0_wd_in[173]
  PIN w0_wd_in[174]
    DIRECTION INPUT ;
    USE SIGNAL ;
    SHAPE ABUTMENT ;
    PORT
      LAYER met3 ;
      RECT 1301.820 504.410 1302.720 504.710 ;
    END
  END w0_wd_in[174]
  PIN w0_wd_in[175]
    DIRECTION INPUT ;
    USE SIGNAL ;
    SHAPE ABUTMENT ;
    PORT
      LAYER met3 ;
      RECT 1301.820 515.290 1302.720 515.590 ;
    END
  END w0_wd_in[175]
  PIN w0_wd_in[176]
    DIRECTION INPUT ;
    USE SIGNAL ;
    SHAPE ABUTMENT ;
    PORT
      LAYER met3 ;
      RECT 1301.820 526.170 1302.720 526.470 ;
    END
  END w0_wd_in[176]
  PIN w0_wd_in[177]
    DIRECTION INPUT ;
    USE SIGNAL ;
    SHAPE ABUTMENT ;
    PORT
      LAYER met3 ;
      RECT 1301.820 537.050 1302.720 537.350 ;
    END
  END w0_wd_in[177]
  PIN w0_wd_in[178]
    DIRECTION INPUT ;
    USE SIGNAL ;
    SHAPE ABUTMENT ;
    PORT
      LAYER met3 ;
      RECT 1301.820 547.930 1302.720 548.230 ;
    END
  END w0_wd_in[178]
  PIN w0_wd_in[179]
    DIRECTION INPUT ;
    USE SIGNAL ;
    SHAPE ABUTMENT ;
    PORT
      LAYER met3 ;
      RECT 1301.820 558.810 1302.720 559.110 ;
    END
  END w0_wd_in[179]
  PIN w0_wd_in[180]
    DIRECTION INPUT ;
    USE SIGNAL ;
    SHAPE ABUTMENT ;
    PORT
      LAYER met3 ;
      RECT 1301.820 569.690 1302.720 569.990 ;
    END
  END w0_wd_in[180]
  PIN w0_wd_in[181]
    DIRECTION INPUT ;
    USE SIGNAL ;
    SHAPE ABUTMENT ;
    PORT
      LAYER met3 ;
      RECT 1301.820 580.570 1302.720 580.870 ;
    END
  END w0_wd_in[181]
  PIN w0_wd_in[182]
    DIRECTION INPUT ;
    USE SIGNAL ;
    SHAPE ABUTMENT ;
    PORT
      LAYER met3 ;
      RECT 1301.820 591.450 1302.720 591.750 ;
    END
  END w0_wd_in[182]
  PIN w0_wd_in[183]
    DIRECTION INPUT ;
    USE SIGNAL ;
    SHAPE ABUTMENT ;
    PORT
      LAYER met3 ;
      RECT 1301.820 602.330 1302.720 602.630 ;
    END
  END w0_wd_in[183]
  PIN w0_wd_in[184]
    DIRECTION INPUT ;
    USE SIGNAL ;
    SHAPE ABUTMENT ;
    PORT
      LAYER met3 ;
      RECT 1301.820 613.210 1302.720 613.510 ;
    END
  END w0_wd_in[184]
  PIN w0_wd_in[185]
    DIRECTION INPUT ;
    USE SIGNAL ;
    SHAPE ABUTMENT ;
    PORT
      LAYER met3 ;
      RECT 1301.820 624.090 1302.720 624.390 ;
    END
  END w0_wd_in[185]
  PIN w0_wd_in[186]
    DIRECTION INPUT ;
    USE SIGNAL ;
    SHAPE ABUTMENT ;
    PORT
      LAYER met3 ;
      RECT 1301.820 634.970 1302.720 635.270 ;
    END
  END w0_wd_in[186]
  PIN w0_wd_in[187]
    DIRECTION INPUT ;
    USE SIGNAL ;
    SHAPE ABUTMENT ;
    PORT
      LAYER met3 ;
      RECT 1301.820 645.850 1302.720 646.150 ;
    END
  END w0_wd_in[187]
  PIN w0_wd_in[188]
    DIRECTION INPUT ;
    USE SIGNAL ;
    SHAPE ABUTMENT ;
    PORT
      LAYER met3 ;
      RECT 1301.820 656.730 1302.720 657.030 ;
    END
  END w0_wd_in[188]
  PIN w0_wd_in[189]
    DIRECTION INPUT ;
    USE SIGNAL ;
    SHAPE ABUTMENT ;
    PORT
      LAYER met3 ;
      RECT 1301.820 667.610 1302.720 667.910 ;
    END
  END w0_wd_in[189]
  PIN w0_wd_in[190]
    DIRECTION INPUT ;
    USE SIGNAL ;
    SHAPE ABUTMENT ;
    PORT
      LAYER met3 ;
      RECT 1301.820 678.490 1302.720 678.790 ;
    END
  END w0_wd_in[190]
  PIN w0_wd_in[191]
    DIRECTION INPUT ;
    USE SIGNAL ;
    SHAPE ABUTMENT ;
    PORT
      LAYER met3 ;
      RECT 1301.820 689.370 1302.720 689.670 ;
    END
  END w0_wd_in[191]
  PIN w0_wd_in[192]
    DIRECTION INPUT ;
    USE SIGNAL ;
    SHAPE ABUTMENT ;
    PORT
      LAYER met3 ;
      RECT 1301.820 700.250 1302.720 700.550 ;
    END
  END w0_wd_in[192]
  PIN w0_wd_in[193]
    DIRECTION INPUT ;
    USE SIGNAL ;
    SHAPE ABUTMENT ;
    PORT
      LAYER met3 ;
      RECT 1301.820 711.130 1302.720 711.430 ;
    END
  END w0_wd_in[193]
  PIN w0_wd_in[194]
    DIRECTION INPUT ;
    USE SIGNAL ;
    SHAPE ABUTMENT ;
    PORT
      LAYER met3 ;
      RECT 1301.820 722.010 1302.720 722.310 ;
    END
  END w0_wd_in[194]
  PIN w0_wd_in[195]
    DIRECTION INPUT ;
    USE SIGNAL ;
    SHAPE ABUTMENT ;
    PORT
      LAYER met3 ;
      RECT 1301.820 732.890 1302.720 733.190 ;
    END
  END w0_wd_in[195]
  PIN w0_wd_in[196]
    DIRECTION INPUT ;
    USE SIGNAL ;
    SHAPE ABUTMENT ;
    PORT
      LAYER met3 ;
      RECT 1301.820 743.770 1302.720 744.070 ;
    END
  END w0_wd_in[196]
  PIN w0_wd_in[197]
    DIRECTION INPUT ;
    USE SIGNAL ;
    SHAPE ABUTMENT ;
    PORT
      LAYER met3 ;
      RECT 1301.820 754.650 1302.720 754.950 ;
    END
  END w0_wd_in[197]
  PIN w0_wd_in[198]
    DIRECTION INPUT ;
    USE SIGNAL ;
    SHAPE ABUTMENT ;
    PORT
      LAYER met3 ;
      RECT 1301.820 765.530 1302.720 765.830 ;
    END
  END w0_wd_in[198]
  PIN w0_wd_in[199]
    DIRECTION INPUT ;
    USE SIGNAL ;
    SHAPE ABUTMENT ;
    PORT
      LAYER met3 ;
      RECT 1301.820 776.410 1302.720 776.710 ;
    END
  END w0_wd_in[199]
  PIN w0_wd_in[200]
    DIRECTION INPUT ;
    USE SIGNAL ;
    SHAPE ABUTMENT ;
    PORT
      LAYER met3 ;
      RECT 1301.820 787.290 1302.720 787.590 ;
    END
  END w0_wd_in[200]
  PIN w0_wd_in[201]
    DIRECTION INPUT ;
    USE SIGNAL ;
    SHAPE ABUTMENT ;
    PORT
      LAYER met3 ;
      RECT 1301.820 798.170 1302.720 798.470 ;
    END
  END w0_wd_in[201]
  PIN w0_wd_in[202]
    DIRECTION INPUT ;
    USE SIGNAL ;
    SHAPE ABUTMENT ;
    PORT
      LAYER met3 ;
      RECT 1301.820 809.050 1302.720 809.350 ;
    END
  END w0_wd_in[202]
  PIN w0_wd_in[203]
    DIRECTION INPUT ;
    USE SIGNAL ;
    SHAPE ABUTMENT ;
    PORT
      LAYER met3 ;
      RECT 1301.820 819.930 1302.720 820.230 ;
    END
  END w0_wd_in[203]
  PIN w0_wd_in[204]
    DIRECTION INPUT ;
    USE SIGNAL ;
    SHAPE ABUTMENT ;
    PORT
      LAYER met3 ;
      RECT 1301.820 830.810 1302.720 831.110 ;
    END
  END w0_wd_in[204]
  PIN w0_wd_in[205]
    DIRECTION INPUT ;
    USE SIGNAL ;
    SHAPE ABUTMENT ;
    PORT
      LAYER met3 ;
      RECT 1301.820 841.690 1302.720 841.990 ;
    END
  END w0_wd_in[205]
  PIN w0_wd_in[206]
    DIRECTION INPUT ;
    USE SIGNAL ;
    SHAPE ABUTMENT ;
    PORT
      LAYER met3 ;
      RECT 1301.820 852.570 1302.720 852.870 ;
    END
  END w0_wd_in[206]
  PIN w0_wd_in[207]
    DIRECTION INPUT ;
    USE SIGNAL ;
    SHAPE ABUTMENT ;
    PORT
      LAYER met3 ;
      RECT 1301.820 863.450 1302.720 863.750 ;
    END
  END w0_wd_in[207]
  PIN w0_wd_in[208]
    DIRECTION INPUT ;
    USE SIGNAL ;
    SHAPE ABUTMENT ;
    PORT
      LAYER met3 ;
      RECT 1301.820 874.330 1302.720 874.630 ;
    END
  END w0_wd_in[208]
  PIN w0_wd_in[209]
    DIRECTION INPUT ;
    USE SIGNAL ;
    SHAPE ABUTMENT ;
    PORT
      LAYER met3 ;
      RECT 1301.820 885.210 1302.720 885.510 ;
    END
  END w0_wd_in[209]
  PIN w0_wd_in[210]
    DIRECTION INPUT ;
    USE SIGNAL ;
    SHAPE ABUTMENT ;
    PORT
      LAYER met3 ;
      RECT 1301.820 896.090 1302.720 896.390 ;
    END
  END w0_wd_in[210]
  PIN w0_wd_in[211]
    DIRECTION INPUT ;
    USE SIGNAL ;
    SHAPE ABUTMENT ;
    PORT
      LAYER met3 ;
      RECT 1301.820 906.970 1302.720 907.270 ;
    END
  END w0_wd_in[211]
  PIN w0_wd_in[212]
    DIRECTION INPUT ;
    USE SIGNAL ;
    SHAPE ABUTMENT ;
    PORT
      LAYER met3 ;
      RECT 1301.820 917.850 1302.720 918.150 ;
    END
  END w0_wd_in[212]
  PIN w0_wd_in[213]
    DIRECTION INPUT ;
    USE SIGNAL ;
    SHAPE ABUTMENT ;
    PORT
      LAYER met3 ;
      RECT 1301.820 928.730 1302.720 929.030 ;
    END
  END w0_wd_in[213]
  PIN w0_wd_in[214]
    DIRECTION INPUT ;
    USE SIGNAL ;
    SHAPE ABUTMENT ;
    PORT
      LAYER met3 ;
      RECT 1301.820 939.610 1302.720 939.910 ;
    END
  END w0_wd_in[214]
  PIN w0_wd_in[215]
    DIRECTION INPUT ;
    USE SIGNAL ;
    SHAPE ABUTMENT ;
    PORT
      LAYER met3 ;
      RECT 1301.820 950.490 1302.720 950.790 ;
    END
  END w0_wd_in[215]
  PIN w0_wd_in[216]
    DIRECTION INPUT ;
    USE SIGNAL ;
    SHAPE ABUTMENT ;
    PORT
      LAYER met3 ;
      RECT 1301.820 961.370 1302.720 961.670 ;
    END
  END w0_wd_in[216]
  PIN w0_wd_in[217]
    DIRECTION INPUT ;
    USE SIGNAL ;
    SHAPE ABUTMENT ;
    PORT
      LAYER met3 ;
      RECT 1301.820 972.250 1302.720 972.550 ;
    END
  END w0_wd_in[217]
  PIN w0_wd_in[218]
    DIRECTION INPUT ;
    USE SIGNAL ;
    SHAPE ABUTMENT ;
    PORT
      LAYER met3 ;
      RECT 1301.820 983.130 1302.720 983.430 ;
    END
  END w0_wd_in[218]
  PIN w0_wd_in[219]
    DIRECTION INPUT ;
    USE SIGNAL ;
    SHAPE ABUTMENT ;
    PORT
      LAYER met3 ;
      RECT 1301.820 994.010 1302.720 994.310 ;
    END
  END w0_wd_in[219]
  PIN w0_wd_in[220]
    DIRECTION INPUT ;
    USE SIGNAL ;
    SHAPE ABUTMENT ;
    PORT
      LAYER met3 ;
      RECT 1301.820 1004.890 1302.720 1005.190 ;
    END
  END w0_wd_in[220]
  PIN w0_wd_in[221]
    DIRECTION INPUT ;
    USE SIGNAL ;
    SHAPE ABUTMENT ;
    PORT
      LAYER met3 ;
      RECT 1301.820 1015.770 1302.720 1016.070 ;
    END
  END w0_wd_in[221]
  PIN w0_wd_in[222]
    DIRECTION INPUT ;
    USE SIGNAL ;
    SHAPE ABUTMENT ;
    PORT
      LAYER met3 ;
      RECT 1301.820 1026.650 1302.720 1026.950 ;
    END
  END w0_wd_in[222]
  PIN w0_wd_in[223]
    DIRECTION INPUT ;
    USE SIGNAL ;
    SHAPE ABUTMENT ;
    PORT
      LAYER met3 ;
      RECT 1301.820 1037.530 1302.720 1037.830 ;
    END
  END w0_wd_in[223]
  PIN w0_wd_in[224]
    DIRECTION INPUT ;
    USE SIGNAL ;
    SHAPE ABUTMENT ;
    PORT
      LAYER met3 ;
      RECT 1301.820 1048.410 1302.720 1048.710 ;
    END
  END w0_wd_in[224]
  PIN w0_wd_in[225]
    DIRECTION INPUT ;
    USE SIGNAL ;
    SHAPE ABUTMENT ;
    PORT
      LAYER met3 ;
      RECT 1301.820 1059.290 1302.720 1059.590 ;
    END
  END w0_wd_in[225]
  PIN w0_wd_in[226]
    DIRECTION INPUT ;
    USE SIGNAL ;
    SHAPE ABUTMENT ;
    PORT
      LAYER met3 ;
      RECT 1301.820 1070.170 1302.720 1070.470 ;
    END
  END w0_wd_in[226]
  PIN w0_wd_in[227]
    DIRECTION INPUT ;
    USE SIGNAL ;
    SHAPE ABUTMENT ;
    PORT
      LAYER met3 ;
      RECT 1301.820 1081.050 1302.720 1081.350 ;
    END
  END w0_wd_in[227]
  PIN w0_wd_in[228]
    DIRECTION INPUT ;
    USE SIGNAL ;
    SHAPE ABUTMENT ;
    PORT
      LAYER met3 ;
      RECT 1301.820 1091.930 1302.720 1092.230 ;
    END
  END w0_wd_in[228]
  PIN w0_wd_in[229]
    DIRECTION INPUT ;
    USE SIGNAL ;
    SHAPE ABUTMENT ;
    PORT
      LAYER met3 ;
      RECT 1301.820 1102.810 1302.720 1103.110 ;
    END
  END w0_wd_in[229]
  PIN w0_wd_in[230]
    DIRECTION INPUT ;
    USE SIGNAL ;
    SHAPE ABUTMENT ;
    PORT
      LAYER met3 ;
      RECT 1301.820 1113.690 1302.720 1113.990 ;
    END
  END w0_wd_in[230]
  PIN w0_wd_in[231]
    DIRECTION INPUT ;
    USE SIGNAL ;
    SHAPE ABUTMENT ;
    PORT
      LAYER met3 ;
      RECT 1301.820 1124.570 1302.720 1124.870 ;
    END
  END w0_wd_in[231]
  PIN w0_wd_in[232]
    DIRECTION INPUT ;
    USE SIGNAL ;
    SHAPE ABUTMENT ;
    PORT
      LAYER met3 ;
      RECT 1301.820 1135.450 1302.720 1135.750 ;
    END
  END w0_wd_in[232]
  PIN w0_wd_in[233]
    DIRECTION INPUT ;
    USE SIGNAL ;
    SHAPE ABUTMENT ;
    PORT
      LAYER met3 ;
      RECT 1301.820 1146.330 1302.720 1146.630 ;
    END
  END w0_wd_in[233]
  PIN w0_wd_in[234]
    DIRECTION INPUT ;
    USE SIGNAL ;
    SHAPE ABUTMENT ;
    PORT
      LAYER met3 ;
      RECT 1301.820 1157.210 1302.720 1157.510 ;
    END
  END w0_wd_in[234]
  PIN w0_wd_in[235]
    DIRECTION INPUT ;
    USE SIGNAL ;
    SHAPE ABUTMENT ;
    PORT
      LAYER met3 ;
      RECT 1301.820 1168.090 1302.720 1168.390 ;
    END
  END w0_wd_in[235]
  PIN w0_wd_in[236]
    DIRECTION INPUT ;
    USE SIGNAL ;
    SHAPE ABUTMENT ;
    PORT
      LAYER met3 ;
      RECT 1301.820 1178.970 1302.720 1179.270 ;
    END
  END w0_wd_in[236]
  PIN w0_wd_in[237]
    DIRECTION INPUT ;
    USE SIGNAL ;
    SHAPE ABUTMENT ;
    PORT
      LAYER met3 ;
      RECT 1301.820 1189.850 1302.720 1190.150 ;
    END
  END w0_wd_in[237]
  PIN w0_wd_in[238]
    DIRECTION INPUT ;
    USE SIGNAL ;
    SHAPE ABUTMENT ;
    PORT
      LAYER met3 ;
      RECT 1301.820 1200.730 1302.720 1201.030 ;
    END
  END w0_wd_in[238]
  PIN w0_wd_in[239]
    DIRECTION INPUT ;
    USE SIGNAL ;
    SHAPE ABUTMENT ;
    PORT
      LAYER met3 ;
      RECT 1301.820 1211.610 1302.720 1211.910 ;
    END
  END w0_wd_in[239]
  PIN w0_wd_in[240]
    DIRECTION INPUT ;
    USE SIGNAL ;
    SHAPE ABUTMENT ;
    PORT
      LAYER met3 ;
      RECT 1301.820 1222.490 1302.720 1222.790 ;
    END
  END w0_wd_in[240]
  PIN w0_wd_in[241]
    DIRECTION INPUT ;
    USE SIGNAL ;
    SHAPE ABUTMENT ;
    PORT
      LAYER met3 ;
      RECT 1301.820 1233.370 1302.720 1233.670 ;
    END
  END w0_wd_in[241]
  PIN w0_wd_in[242]
    DIRECTION INPUT ;
    USE SIGNAL ;
    SHAPE ABUTMENT ;
    PORT
      LAYER met3 ;
      RECT 1301.820 1244.250 1302.720 1244.550 ;
    END
  END w0_wd_in[242]
  PIN w0_wd_in[243]
    DIRECTION INPUT ;
    USE SIGNAL ;
    SHAPE ABUTMENT ;
    PORT
      LAYER met3 ;
      RECT 1301.820 1255.130 1302.720 1255.430 ;
    END
  END w0_wd_in[243]
  PIN w0_wd_in[244]
    DIRECTION INPUT ;
    USE SIGNAL ;
    SHAPE ABUTMENT ;
    PORT
      LAYER met3 ;
      RECT 1301.820 1266.010 1302.720 1266.310 ;
    END
  END w0_wd_in[244]
  PIN w0_wd_in[245]
    DIRECTION INPUT ;
    USE SIGNAL ;
    SHAPE ABUTMENT ;
    PORT
      LAYER met3 ;
      RECT 1301.820 1276.890 1302.720 1277.190 ;
    END
  END w0_wd_in[245]
  PIN w0_wd_in[246]
    DIRECTION INPUT ;
    USE SIGNAL ;
    SHAPE ABUTMENT ;
    PORT
      LAYER met3 ;
      RECT 1301.820 1287.770 1302.720 1288.070 ;
    END
  END w0_wd_in[246]
  PIN w0_wd_in[247]
    DIRECTION INPUT ;
    USE SIGNAL ;
    SHAPE ABUTMENT ;
    PORT
      LAYER met3 ;
      RECT 1301.820 1298.650 1302.720 1298.950 ;
    END
  END w0_wd_in[247]
  PIN w0_wd_in[248]
    DIRECTION INPUT ;
    USE SIGNAL ;
    SHAPE ABUTMENT ;
    PORT
      LAYER met3 ;
      RECT 1301.820 1309.530 1302.720 1309.830 ;
    END
  END w0_wd_in[248]
  PIN w0_wd_in[249]
    DIRECTION INPUT ;
    USE SIGNAL ;
    SHAPE ABUTMENT ;
    PORT
      LAYER met3 ;
      RECT 1301.820 1320.410 1302.720 1320.710 ;
    END
  END w0_wd_in[249]
  PIN w0_wd_in[250]
    DIRECTION INPUT ;
    USE SIGNAL ;
    SHAPE ABUTMENT ;
    PORT
      LAYER met3 ;
      RECT 1301.820 1331.290 1302.720 1331.590 ;
    END
  END w0_wd_in[250]
  PIN w0_wd_in[251]
    DIRECTION INPUT ;
    USE SIGNAL ;
    SHAPE ABUTMENT ;
    PORT
      LAYER met3 ;
      RECT 1301.820 1342.170 1302.720 1342.470 ;
    END
  END w0_wd_in[251]
  PIN w0_wd_in[252]
    DIRECTION INPUT ;
    USE SIGNAL ;
    SHAPE ABUTMENT ;
    PORT
      LAYER met3 ;
      RECT 1301.820 1353.050 1302.720 1353.350 ;
    END
  END w0_wd_in[252]
  PIN w0_wd_in[253]
    DIRECTION INPUT ;
    USE SIGNAL ;
    SHAPE ABUTMENT ;
    PORT
      LAYER met3 ;
      RECT 1301.820 1363.930 1302.720 1364.230 ;
    END
  END w0_wd_in[253]
  PIN w0_wd_in[254]
    DIRECTION INPUT ;
    USE SIGNAL ;
    SHAPE ABUTMENT ;
    PORT
      LAYER met3 ;
      RECT 1301.820 1374.810 1302.720 1375.110 ;
    END
  END w0_wd_in[254]
  PIN w0_wd_in[255]
    DIRECTION INPUT ;
    USE SIGNAL ;
    SHAPE ABUTMENT ;
    PORT
      LAYER met3 ;
      RECT 1301.820 1385.690 1302.720 1385.990 ;
    END
  END w0_wd_in[255]
  PIN w0_wd_in[256]
    DIRECTION OUTPUT ;
    USE SIGNAL ;
    SHAPE ABUTMENT ;
    PORT
      LAYER met2 ;
      RECT 2.690 0.000 2.830 0.420 ;
    END
  END w0_wd_in[256]
  PIN w0_wd_in[257]
    DIRECTION OUTPUT ;
    USE SIGNAL ;
    SHAPE ABUTMENT ;
    PORT
      LAYER met2 ;
      RECT 4.990 0.000 5.130 0.420 ;
    END
  END w0_wd_in[257]
  PIN w0_wd_in[258]
    DIRECTION OUTPUT ;
    USE SIGNAL ;
    SHAPE ABUTMENT ;
    PORT
      LAYER met2 ;
      RECT 7.290 0.000 7.430 0.420 ;
    END
  END w0_wd_in[258]
  PIN w0_wd_in[259]
    DIRECTION OUTPUT ;
    USE SIGNAL ;
    SHAPE ABUTMENT ;
    PORT
      LAYER met2 ;
      RECT 9.590 0.000 9.730 0.420 ;
    END
  END w0_wd_in[259]
  PIN w0_wd_in[260]
    DIRECTION OUTPUT ;
    USE SIGNAL ;
    SHAPE ABUTMENT ;
    PORT
      LAYER met2 ;
      RECT 11.890 0.000 12.030 0.420 ;
    END
  END w0_wd_in[260]
  PIN w0_wd_in[261]
    DIRECTION OUTPUT ;
    USE SIGNAL ;
    SHAPE ABUTMENT ;
    PORT
      LAYER met2 ;
      RECT 14.190 0.000 14.330 0.420 ;
    END
  END w0_wd_in[261]
  PIN w0_wd_in[262]
    DIRECTION OUTPUT ;
    USE SIGNAL ;
    SHAPE ABUTMENT ;
    PORT
      LAYER met2 ;
      RECT 16.490 0.000 16.630 0.420 ;
    END
  END w0_wd_in[262]
  PIN w0_wd_in[263]
    DIRECTION OUTPUT ;
    USE SIGNAL ;
    SHAPE ABUTMENT ;
    PORT
      LAYER met2 ;
      RECT 18.790 0.000 18.930 0.420 ;
    END
  END w0_wd_in[263]
  PIN w0_wd_in[264]
    DIRECTION OUTPUT ;
    USE SIGNAL ;
    SHAPE ABUTMENT ;
    PORT
      LAYER met2 ;
      RECT 21.090 0.000 21.230 0.420 ;
    END
  END w0_wd_in[264]
  PIN w0_wd_in[265]
    DIRECTION OUTPUT ;
    USE SIGNAL ;
    SHAPE ABUTMENT ;
    PORT
      LAYER met2 ;
      RECT 23.390 0.000 23.530 0.420 ;
    END
  END w0_wd_in[265]
  PIN w0_wd_in[266]
    DIRECTION OUTPUT ;
    USE SIGNAL ;
    SHAPE ABUTMENT ;
    PORT
      LAYER met2 ;
      RECT 25.690 0.000 25.830 0.420 ;
    END
  END w0_wd_in[266]
  PIN w0_wd_in[267]
    DIRECTION OUTPUT ;
    USE SIGNAL ;
    SHAPE ABUTMENT ;
    PORT
      LAYER met2 ;
      RECT 27.990 0.000 28.130 0.420 ;
    END
  END w0_wd_in[267]
  PIN w0_wd_in[268]
    DIRECTION OUTPUT ;
    USE SIGNAL ;
    SHAPE ABUTMENT ;
    PORT
      LAYER met2 ;
      RECT 30.290 0.000 30.430 0.420 ;
    END
  END w0_wd_in[268]
  PIN w0_wd_in[269]
    DIRECTION OUTPUT ;
    USE SIGNAL ;
    SHAPE ABUTMENT ;
    PORT
      LAYER met2 ;
      RECT 32.590 0.000 32.730 0.420 ;
    END
  END w0_wd_in[269]
  PIN w0_wd_in[270]
    DIRECTION OUTPUT ;
    USE SIGNAL ;
    SHAPE ABUTMENT ;
    PORT
      LAYER met2 ;
      RECT 34.890 0.000 35.030 0.420 ;
    END
  END w0_wd_in[270]
  PIN w0_wd_in[271]
    DIRECTION OUTPUT ;
    USE SIGNAL ;
    SHAPE ABUTMENT ;
    PORT
      LAYER met2 ;
      RECT 37.190 0.000 37.330 0.420 ;
    END
  END w0_wd_in[271]
  PIN w0_wd_in[272]
    DIRECTION OUTPUT ;
    USE SIGNAL ;
    SHAPE ABUTMENT ;
    PORT
      LAYER met2 ;
      RECT 39.490 0.000 39.630 0.420 ;
    END
  END w0_wd_in[272]
  PIN w0_wd_in[273]
    DIRECTION OUTPUT ;
    USE SIGNAL ;
    SHAPE ABUTMENT ;
    PORT
      LAYER met2 ;
      RECT 41.790 0.000 41.930 0.420 ;
    END
  END w0_wd_in[273]
  PIN w0_wd_in[274]
    DIRECTION OUTPUT ;
    USE SIGNAL ;
    SHAPE ABUTMENT ;
    PORT
      LAYER met2 ;
      RECT 44.090 0.000 44.230 0.420 ;
    END
  END w0_wd_in[274]
  PIN w0_wd_in[275]
    DIRECTION OUTPUT ;
    USE SIGNAL ;
    SHAPE ABUTMENT ;
    PORT
      LAYER met2 ;
      RECT 46.390 0.000 46.530 0.420 ;
    END
  END w0_wd_in[275]
  PIN w0_wd_in[276]
    DIRECTION OUTPUT ;
    USE SIGNAL ;
    SHAPE ABUTMENT ;
    PORT
      LAYER met2 ;
      RECT 48.690 0.000 48.830 0.420 ;
    END
  END w0_wd_in[276]
  PIN w0_wd_in[277]
    DIRECTION OUTPUT ;
    USE SIGNAL ;
    SHAPE ABUTMENT ;
    PORT
      LAYER met2 ;
      RECT 50.990 0.000 51.130 0.420 ;
    END
  END w0_wd_in[277]
  PIN w0_wd_in[278]
    DIRECTION OUTPUT ;
    USE SIGNAL ;
    SHAPE ABUTMENT ;
    PORT
      LAYER met2 ;
      RECT 53.290 0.000 53.430 0.420 ;
    END
  END w0_wd_in[278]
  PIN w0_wd_in[279]
    DIRECTION OUTPUT ;
    USE SIGNAL ;
    SHAPE ABUTMENT ;
    PORT
      LAYER met2 ;
      RECT 55.590 0.000 55.730 0.420 ;
    END
  END w0_wd_in[279]
  PIN w0_wd_in[280]
    DIRECTION OUTPUT ;
    USE SIGNAL ;
    SHAPE ABUTMENT ;
    PORT
      LAYER met2 ;
      RECT 57.890 0.000 58.030 0.420 ;
    END
  END w0_wd_in[280]
  PIN w0_wd_in[281]
    DIRECTION OUTPUT ;
    USE SIGNAL ;
    SHAPE ABUTMENT ;
    PORT
      LAYER met2 ;
      RECT 60.190 0.000 60.330 0.420 ;
    END
  END w0_wd_in[281]
  PIN w0_wd_in[282]
    DIRECTION OUTPUT ;
    USE SIGNAL ;
    SHAPE ABUTMENT ;
    PORT
      LAYER met2 ;
      RECT 62.490 0.000 62.630 0.420 ;
    END
  END w0_wd_in[282]
  PIN w0_wd_in[283]
    DIRECTION OUTPUT ;
    USE SIGNAL ;
    SHAPE ABUTMENT ;
    PORT
      LAYER met2 ;
      RECT 64.790 0.000 64.930 0.420 ;
    END
  END w0_wd_in[283]
  PIN w0_wd_in[284]
    DIRECTION OUTPUT ;
    USE SIGNAL ;
    SHAPE ABUTMENT ;
    PORT
      LAYER met2 ;
      RECT 67.090 0.000 67.230 0.420 ;
    END
  END w0_wd_in[284]
  PIN w0_wd_in[285]
    DIRECTION OUTPUT ;
    USE SIGNAL ;
    SHAPE ABUTMENT ;
    PORT
      LAYER met2 ;
      RECT 69.390 0.000 69.530 0.420 ;
    END
  END w0_wd_in[285]
  PIN w0_wd_in[286]
    DIRECTION OUTPUT ;
    USE SIGNAL ;
    SHAPE ABUTMENT ;
    PORT
      LAYER met2 ;
      RECT 71.690 0.000 71.830 0.420 ;
    END
  END w0_wd_in[286]
  PIN w0_wd_in[287]
    DIRECTION OUTPUT ;
    USE SIGNAL ;
    SHAPE ABUTMENT ;
    PORT
      LAYER met2 ;
      RECT 73.990 0.000 74.130 0.420 ;
    END
  END w0_wd_in[287]
  PIN w0_wd_in[288]
    DIRECTION OUTPUT ;
    USE SIGNAL ;
    SHAPE ABUTMENT ;
    PORT
      LAYER met2 ;
      RECT 76.290 0.000 76.430 0.420 ;
    END
  END w0_wd_in[288]
  PIN w0_wd_in[289]
    DIRECTION OUTPUT ;
    USE SIGNAL ;
    SHAPE ABUTMENT ;
    PORT
      LAYER met2 ;
      RECT 78.590 0.000 78.730 0.420 ;
    END
  END w0_wd_in[289]
  PIN w0_wd_in[290]
    DIRECTION OUTPUT ;
    USE SIGNAL ;
    SHAPE ABUTMENT ;
    PORT
      LAYER met2 ;
      RECT 80.890 0.000 81.030 0.420 ;
    END
  END w0_wd_in[290]
  PIN w0_wd_in[291]
    DIRECTION OUTPUT ;
    USE SIGNAL ;
    SHAPE ABUTMENT ;
    PORT
      LAYER met2 ;
      RECT 83.190 0.000 83.330 0.420 ;
    END
  END w0_wd_in[291]
  PIN w0_wd_in[292]
    DIRECTION OUTPUT ;
    USE SIGNAL ;
    SHAPE ABUTMENT ;
    PORT
      LAYER met2 ;
      RECT 85.490 0.000 85.630 0.420 ;
    END
  END w0_wd_in[292]
  PIN w0_wd_in[293]
    DIRECTION OUTPUT ;
    USE SIGNAL ;
    SHAPE ABUTMENT ;
    PORT
      LAYER met2 ;
      RECT 87.790 0.000 87.930 0.420 ;
    END
  END w0_wd_in[293]
  PIN w0_wd_in[294]
    DIRECTION OUTPUT ;
    USE SIGNAL ;
    SHAPE ABUTMENT ;
    PORT
      LAYER met2 ;
      RECT 90.090 0.000 90.230 0.420 ;
    END
  END w0_wd_in[294]
  PIN w0_wd_in[295]
    DIRECTION OUTPUT ;
    USE SIGNAL ;
    SHAPE ABUTMENT ;
    PORT
      LAYER met2 ;
      RECT 92.390 0.000 92.530 0.420 ;
    END
  END w0_wd_in[295]
  PIN w0_wd_in[296]
    DIRECTION OUTPUT ;
    USE SIGNAL ;
    SHAPE ABUTMENT ;
    PORT
      LAYER met2 ;
      RECT 94.690 0.000 94.830 0.420 ;
    END
  END w0_wd_in[296]
  PIN w0_wd_in[297]
    DIRECTION OUTPUT ;
    USE SIGNAL ;
    SHAPE ABUTMENT ;
    PORT
      LAYER met2 ;
      RECT 96.990 0.000 97.130 0.420 ;
    END
  END w0_wd_in[297]
  PIN w0_wd_in[298]
    DIRECTION OUTPUT ;
    USE SIGNAL ;
    SHAPE ABUTMENT ;
    PORT
      LAYER met2 ;
      RECT 99.290 0.000 99.430 0.420 ;
    END
  END w0_wd_in[298]
  PIN w0_wd_in[299]
    DIRECTION OUTPUT ;
    USE SIGNAL ;
    SHAPE ABUTMENT ;
    PORT
      LAYER met2 ;
      RECT 101.590 0.000 101.730 0.420 ;
    END
  END w0_wd_in[299]
  PIN w0_wd_in[300]
    DIRECTION OUTPUT ;
    USE SIGNAL ;
    SHAPE ABUTMENT ;
    PORT
      LAYER met2 ;
      RECT 103.890 0.000 104.030 0.420 ;
    END
  END w0_wd_in[300]
  PIN w0_wd_in[301]
    DIRECTION OUTPUT ;
    USE SIGNAL ;
    SHAPE ABUTMENT ;
    PORT
      LAYER met2 ;
      RECT 106.190 0.000 106.330 0.420 ;
    END
  END w0_wd_in[301]
  PIN w0_wd_in[302]
    DIRECTION OUTPUT ;
    USE SIGNAL ;
    SHAPE ABUTMENT ;
    PORT
      LAYER met2 ;
      RECT 108.490 0.000 108.630 0.420 ;
    END
  END w0_wd_in[302]
  PIN w0_wd_in[303]
    DIRECTION OUTPUT ;
    USE SIGNAL ;
    SHAPE ABUTMENT ;
    PORT
      LAYER met2 ;
      RECT 110.790 0.000 110.930 0.420 ;
    END
  END w0_wd_in[303]
  PIN w0_wd_in[304]
    DIRECTION OUTPUT ;
    USE SIGNAL ;
    SHAPE ABUTMENT ;
    PORT
      LAYER met2 ;
      RECT 113.090 0.000 113.230 0.420 ;
    END
  END w0_wd_in[304]
  PIN w0_wd_in[305]
    DIRECTION OUTPUT ;
    USE SIGNAL ;
    SHAPE ABUTMENT ;
    PORT
      LAYER met2 ;
      RECT 115.390 0.000 115.530 0.420 ;
    END
  END w0_wd_in[305]
  PIN w0_wd_in[306]
    DIRECTION OUTPUT ;
    USE SIGNAL ;
    SHAPE ABUTMENT ;
    PORT
      LAYER met2 ;
      RECT 117.690 0.000 117.830 0.420 ;
    END
  END w0_wd_in[306]
  PIN w0_wd_in[307]
    DIRECTION OUTPUT ;
    USE SIGNAL ;
    SHAPE ABUTMENT ;
    PORT
      LAYER met2 ;
      RECT 119.990 0.000 120.130 0.420 ;
    END
  END w0_wd_in[307]
  PIN w0_wd_in[308]
    DIRECTION OUTPUT ;
    USE SIGNAL ;
    SHAPE ABUTMENT ;
    PORT
      LAYER met2 ;
      RECT 122.290 0.000 122.430 0.420 ;
    END
  END w0_wd_in[308]
  PIN w0_wd_in[309]
    DIRECTION OUTPUT ;
    USE SIGNAL ;
    SHAPE ABUTMENT ;
    PORT
      LAYER met2 ;
      RECT 124.590 0.000 124.730 0.420 ;
    END
  END w0_wd_in[309]
  PIN w0_wd_in[310]
    DIRECTION OUTPUT ;
    USE SIGNAL ;
    SHAPE ABUTMENT ;
    PORT
      LAYER met2 ;
      RECT 126.890 0.000 127.030 0.420 ;
    END
  END w0_wd_in[310]
  PIN w0_wd_in[311]
    DIRECTION OUTPUT ;
    USE SIGNAL ;
    SHAPE ABUTMENT ;
    PORT
      LAYER met2 ;
      RECT 129.190 0.000 129.330 0.420 ;
    END
  END w0_wd_in[311]
  PIN w0_wd_in[312]
    DIRECTION OUTPUT ;
    USE SIGNAL ;
    SHAPE ABUTMENT ;
    PORT
      LAYER met2 ;
      RECT 131.490 0.000 131.630 0.420 ;
    END
  END w0_wd_in[312]
  PIN w0_wd_in[313]
    DIRECTION OUTPUT ;
    USE SIGNAL ;
    SHAPE ABUTMENT ;
    PORT
      LAYER met2 ;
      RECT 133.790 0.000 133.930 0.420 ;
    END
  END w0_wd_in[313]
  PIN w0_wd_in[314]
    DIRECTION OUTPUT ;
    USE SIGNAL ;
    SHAPE ABUTMENT ;
    PORT
      LAYER met2 ;
      RECT 136.090 0.000 136.230 0.420 ;
    END
  END w0_wd_in[314]
  PIN w0_wd_in[315]
    DIRECTION OUTPUT ;
    USE SIGNAL ;
    SHAPE ABUTMENT ;
    PORT
      LAYER met2 ;
      RECT 138.390 0.000 138.530 0.420 ;
    END
  END w0_wd_in[315]
  PIN w0_wd_in[316]
    DIRECTION OUTPUT ;
    USE SIGNAL ;
    SHAPE ABUTMENT ;
    PORT
      LAYER met2 ;
      RECT 140.690 0.000 140.830 0.420 ;
    END
  END w0_wd_in[316]
  PIN w0_wd_in[317]
    DIRECTION OUTPUT ;
    USE SIGNAL ;
    SHAPE ABUTMENT ;
    PORT
      LAYER met2 ;
      RECT 142.990 0.000 143.130 0.420 ;
    END
  END w0_wd_in[317]
  PIN w0_wd_in[318]
    DIRECTION OUTPUT ;
    USE SIGNAL ;
    SHAPE ABUTMENT ;
    PORT
      LAYER met2 ;
      RECT 145.290 0.000 145.430 0.420 ;
    END
  END w0_wd_in[318]
  PIN w0_wd_in[319]
    DIRECTION OUTPUT ;
    USE SIGNAL ;
    SHAPE ABUTMENT ;
    PORT
      LAYER met2 ;
      RECT 147.590 0.000 147.730 0.420 ;
    END
  END w0_wd_in[319]
  PIN w0_wd_in[320]
    DIRECTION OUTPUT ;
    USE SIGNAL ;
    SHAPE ABUTMENT ;
    PORT
      LAYER met2 ;
      RECT 149.890 0.000 150.030 0.420 ;
    END
  END w0_wd_in[320]
  PIN w0_wd_in[321]
    DIRECTION OUTPUT ;
    USE SIGNAL ;
    SHAPE ABUTMENT ;
    PORT
      LAYER met2 ;
      RECT 152.190 0.000 152.330 0.420 ;
    END
  END w0_wd_in[321]
  PIN w0_wd_in[322]
    DIRECTION OUTPUT ;
    USE SIGNAL ;
    SHAPE ABUTMENT ;
    PORT
      LAYER met2 ;
      RECT 154.490 0.000 154.630 0.420 ;
    END
  END w0_wd_in[322]
  PIN w0_wd_in[323]
    DIRECTION OUTPUT ;
    USE SIGNAL ;
    SHAPE ABUTMENT ;
    PORT
      LAYER met2 ;
      RECT 156.790 0.000 156.930 0.420 ;
    END
  END w0_wd_in[323]
  PIN w0_wd_in[324]
    DIRECTION OUTPUT ;
    USE SIGNAL ;
    SHAPE ABUTMENT ;
    PORT
      LAYER met2 ;
      RECT 159.090 0.000 159.230 0.420 ;
    END
  END w0_wd_in[324]
  PIN w0_wd_in[325]
    DIRECTION OUTPUT ;
    USE SIGNAL ;
    SHAPE ABUTMENT ;
    PORT
      LAYER met2 ;
      RECT 161.390 0.000 161.530 0.420 ;
    END
  END w0_wd_in[325]
  PIN w0_wd_in[326]
    DIRECTION OUTPUT ;
    USE SIGNAL ;
    SHAPE ABUTMENT ;
    PORT
      LAYER met2 ;
      RECT 163.690 0.000 163.830 0.420 ;
    END
  END w0_wd_in[326]
  PIN w0_wd_in[327]
    DIRECTION OUTPUT ;
    USE SIGNAL ;
    SHAPE ABUTMENT ;
    PORT
      LAYER met2 ;
      RECT 165.990 0.000 166.130 0.420 ;
    END
  END w0_wd_in[327]
  PIN w0_wd_in[328]
    DIRECTION OUTPUT ;
    USE SIGNAL ;
    SHAPE ABUTMENT ;
    PORT
      LAYER met2 ;
      RECT 168.290 0.000 168.430 0.420 ;
    END
  END w0_wd_in[328]
  PIN w0_wd_in[329]
    DIRECTION OUTPUT ;
    USE SIGNAL ;
    SHAPE ABUTMENT ;
    PORT
      LAYER met2 ;
      RECT 170.590 0.000 170.730 0.420 ;
    END
  END w0_wd_in[329]
  PIN w0_wd_in[330]
    DIRECTION OUTPUT ;
    USE SIGNAL ;
    SHAPE ABUTMENT ;
    PORT
      LAYER met2 ;
      RECT 172.890 0.000 173.030 0.420 ;
    END
  END w0_wd_in[330]
  PIN w0_wd_in[331]
    DIRECTION OUTPUT ;
    USE SIGNAL ;
    SHAPE ABUTMENT ;
    PORT
      LAYER met2 ;
      RECT 175.190 0.000 175.330 0.420 ;
    END
  END w0_wd_in[331]
  PIN w0_wd_in[332]
    DIRECTION OUTPUT ;
    USE SIGNAL ;
    SHAPE ABUTMENT ;
    PORT
      LAYER met2 ;
      RECT 177.490 0.000 177.630 0.420 ;
    END
  END w0_wd_in[332]
  PIN w0_wd_in[333]
    DIRECTION OUTPUT ;
    USE SIGNAL ;
    SHAPE ABUTMENT ;
    PORT
      LAYER met2 ;
      RECT 179.790 0.000 179.930 0.420 ;
    END
  END w0_wd_in[333]
  PIN w0_wd_in[334]
    DIRECTION OUTPUT ;
    USE SIGNAL ;
    SHAPE ABUTMENT ;
    PORT
      LAYER met2 ;
      RECT 182.090 0.000 182.230 0.420 ;
    END
  END w0_wd_in[334]
  PIN w0_wd_in[335]
    DIRECTION OUTPUT ;
    USE SIGNAL ;
    SHAPE ABUTMENT ;
    PORT
      LAYER met2 ;
      RECT 184.390 0.000 184.530 0.420 ;
    END
  END w0_wd_in[335]
  PIN w0_wd_in[336]
    DIRECTION OUTPUT ;
    USE SIGNAL ;
    SHAPE ABUTMENT ;
    PORT
      LAYER met2 ;
      RECT 186.690 0.000 186.830 0.420 ;
    END
  END w0_wd_in[336]
  PIN w0_wd_in[337]
    DIRECTION OUTPUT ;
    USE SIGNAL ;
    SHAPE ABUTMENT ;
    PORT
      LAYER met2 ;
      RECT 188.990 0.000 189.130 0.420 ;
    END
  END w0_wd_in[337]
  PIN w0_wd_in[338]
    DIRECTION OUTPUT ;
    USE SIGNAL ;
    SHAPE ABUTMENT ;
    PORT
      LAYER met2 ;
      RECT 191.290 0.000 191.430 0.420 ;
    END
  END w0_wd_in[338]
  PIN w0_wd_in[339]
    DIRECTION OUTPUT ;
    USE SIGNAL ;
    SHAPE ABUTMENT ;
    PORT
      LAYER met2 ;
      RECT 193.590 0.000 193.730 0.420 ;
    END
  END w0_wd_in[339]
  PIN w0_wd_in[340]
    DIRECTION OUTPUT ;
    USE SIGNAL ;
    SHAPE ABUTMENT ;
    PORT
      LAYER met2 ;
      RECT 195.890 0.000 196.030 0.420 ;
    END
  END w0_wd_in[340]
  PIN w0_wd_in[341]
    DIRECTION OUTPUT ;
    USE SIGNAL ;
    SHAPE ABUTMENT ;
    PORT
      LAYER met2 ;
      RECT 198.190 0.000 198.330 0.420 ;
    END
  END w0_wd_in[341]
  PIN w0_wd_in[342]
    DIRECTION OUTPUT ;
    USE SIGNAL ;
    SHAPE ABUTMENT ;
    PORT
      LAYER met2 ;
      RECT 200.490 0.000 200.630 0.420 ;
    END
  END w0_wd_in[342]
  PIN w0_wd_in[343]
    DIRECTION OUTPUT ;
    USE SIGNAL ;
    SHAPE ABUTMENT ;
    PORT
      LAYER met2 ;
      RECT 202.790 0.000 202.930 0.420 ;
    END
  END w0_wd_in[343]
  PIN w0_wd_in[344]
    DIRECTION OUTPUT ;
    USE SIGNAL ;
    SHAPE ABUTMENT ;
    PORT
      LAYER met2 ;
      RECT 205.090 0.000 205.230 0.420 ;
    END
  END w0_wd_in[344]
  PIN w0_wd_in[345]
    DIRECTION OUTPUT ;
    USE SIGNAL ;
    SHAPE ABUTMENT ;
    PORT
      LAYER met2 ;
      RECT 207.390 0.000 207.530 0.420 ;
    END
  END w0_wd_in[345]
  PIN w0_wd_in[346]
    DIRECTION OUTPUT ;
    USE SIGNAL ;
    SHAPE ABUTMENT ;
    PORT
      LAYER met2 ;
      RECT 209.690 0.000 209.830 0.420 ;
    END
  END w0_wd_in[346]
  PIN w0_wd_in[347]
    DIRECTION OUTPUT ;
    USE SIGNAL ;
    SHAPE ABUTMENT ;
    PORT
      LAYER met2 ;
      RECT 211.990 0.000 212.130 0.420 ;
    END
  END w0_wd_in[347]
  PIN w0_wd_in[348]
    DIRECTION OUTPUT ;
    USE SIGNAL ;
    SHAPE ABUTMENT ;
    PORT
      LAYER met2 ;
      RECT 214.290 0.000 214.430 0.420 ;
    END
  END w0_wd_in[348]
  PIN w0_wd_in[349]
    DIRECTION OUTPUT ;
    USE SIGNAL ;
    SHAPE ABUTMENT ;
    PORT
      LAYER met2 ;
      RECT 216.590 0.000 216.730 0.420 ;
    END
  END w0_wd_in[349]
  PIN w0_wd_in[350]
    DIRECTION OUTPUT ;
    USE SIGNAL ;
    SHAPE ABUTMENT ;
    PORT
      LAYER met2 ;
      RECT 218.890 0.000 219.030 0.420 ;
    END
  END w0_wd_in[350]
  PIN w0_wd_in[351]
    DIRECTION OUTPUT ;
    USE SIGNAL ;
    SHAPE ABUTMENT ;
    PORT
      LAYER met2 ;
      RECT 221.190 0.000 221.330 0.420 ;
    END
  END w0_wd_in[351]
  PIN w0_wd_in[352]
    DIRECTION OUTPUT ;
    USE SIGNAL ;
    SHAPE ABUTMENT ;
    PORT
      LAYER met2 ;
      RECT 223.490 0.000 223.630 0.420 ;
    END
  END w0_wd_in[352]
  PIN w0_wd_in[353]
    DIRECTION OUTPUT ;
    USE SIGNAL ;
    SHAPE ABUTMENT ;
    PORT
      LAYER met2 ;
      RECT 225.790 0.000 225.930 0.420 ;
    END
  END w0_wd_in[353]
  PIN w0_wd_in[354]
    DIRECTION OUTPUT ;
    USE SIGNAL ;
    SHAPE ABUTMENT ;
    PORT
      LAYER met2 ;
      RECT 228.090 0.000 228.230 0.420 ;
    END
  END w0_wd_in[354]
  PIN w0_wd_in[355]
    DIRECTION OUTPUT ;
    USE SIGNAL ;
    SHAPE ABUTMENT ;
    PORT
      LAYER met2 ;
      RECT 230.390 0.000 230.530 0.420 ;
    END
  END w0_wd_in[355]
  PIN w0_wd_in[356]
    DIRECTION OUTPUT ;
    USE SIGNAL ;
    SHAPE ABUTMENT ;
    PORT
      LAYER met2 ;
      RECT 232.690 0.000 232.830 0.420 ;
    END
  END w0_wd_in[356]
  PIN w0_wd_in[357]
    DIRECTION OUTPUT ;
    USE SIGNAL ;
    SHAPE ABUTMENT ;
    PORT
      LAYER met2 ;
      RECT 234.990 0.000 235.130 0.420 ;
    END
  END w0_wd_in[357]
  PIN w0_wd_in[358]
    DIRECTION OUTPUT ;
    USE SIGNAL ;
    SHAPE ABUTMENT ;
    PORT
      LAYER met2 ;
      RECT 237.290 0.000 237.430 0.420 ;
    END
  END w0_wd_in[358]
  PIN w0_wd_in[359]
    DIRECTION OUTPUT ;
    USE SIGNAL ;
    SHAPE ABUTMENT ;
    PORT
      LAYER met2 ;
      RECT 239.590 0.000 239.730 0.420 ;
    END
  END w0_wd_in[359]
  PIN w0_wd_in[360]
    DIRECTION OUTPUT ;
    USE SIGNAL ;
    SHAPE ABUTMENT ;
    PORT
      LAYER met2 ;
      RECT 241.890 0.000 242.030 0.420 ;
    END
  END w0_wd_in[360]
  PIN w0_wd_in[361]
    DIRECTION OUTPUT ;
    USE SIGNAL ;
    SHAPE ABUTMENT ;
    PORT
      LAYER met2 ;
      RECT 244.190 0.000 244.330 0.420 ;
    END
  END w0_wd_in[361]
  PIN w0_wd_in[362]
    DIRECTION OUTPUT ;
    USE SIGNAL ;
    SHAPE ABUTMENT ;
    PORT
      LAYER met2 ;
      RECT 246.490 0.000 246.630 0.420 ;
    END
  END w0_wd_in[362]
  PIN w0_wd_in[363]
    DIRECTION OUTPUT ;
    USE SIGNAL ;
    SHAPE ABUTMENT ;
    PORT
      LAYER met2 ;
      RECT 248.790 0.000 248.930 0.420 ;
    END
  END w0_wd_in[363]
  PIN w0_wd_in[364]
    DIRECTION OUTPUT ;
    USE SIGNAL ;
    SHAPE ABUTMENT ;
    PORT
      LAYER met2 ;
      RECT 251.090 0.000 251.230 0.420 ;
    END
  END w0_wd_in[364]
  PIN w0_wd_in[365]
    DIRECTION OUTPUT ;
    USE SIGNAL ;
    SHAPE ABUTMENT ;
    PORT
      LAYER met2 ;
      RECT 253.390 0.000 253.530 0.420 ;
    END
  END w0_wd_in[365]
  PIN w0_wd_in[366]
    DIRECTION OUTPUT ;
    USE SIGNAL ;
    SHAPE ABUTMENT ;
    PORT
      LAYER met2 ;
      RECT 255.690 0.000 255.830 0.420 ;
    END
  END w0_wd_in[366]
  PIN w0_wd_in[367]
    DIRECTION OUTPUT ;
    USE SIGNAL ;
    SHAPE ABUTMENT ;
    PORT
      LAYER met2 ;
      RECT 257.990 0.000 258.130 0.420 ;
    END
  END w0_wd_in[367]
  PIN w0_wd_in[368]
    DIRECTION OUTPUT ;
    USE SIGNAL ;
    SHAPE ABUTMENT ;
    PORT
      LAYER met2 ;
      RECT 260.290 0.000 260.430 0.420 ;
    END
  END w0_wd_in[368]
  PIN w0_wd_in[369]
    DIRECTION OUTPUT ;
    USE SIGNAL ;
    SHAPE ABUTMENT ;
    PORT
      LAYER met2 ;
      RECT 262.590 0.000 262.730 0.420 ;
    END
  END w0_wd_in[369]
  PIN w0_wd_in[370]
    DIRECTION OUTPUT ;
    USE SIGNAL ;
    SHAPE ABUTMENT ;
    PORT
      LAYER met2 ;
      RECT 264.890 0.000 265.030 0.420 ;
    END
  END w0_wd_in[370]
  PIN w0_wd_in[371]
    DIRECTION OUTPUT ;
    USE SIGNAL ;
    SHAPE ABUTMENT ;
    PORT
      LAYER met2 ;
      RECT 267.190 0.000 267.330 0.420 ;
    END
  END w0_wd_in[371]
  PIN w0_wd_in[372]
    DIRECTION OUTPUT ;
    USE SIGNAL ;
    SHAPE ABUTMENT ;
    PORT
      LAYER met2 ;
      RECT 269.490 0.000 269.630 0.420 ;
    END
  END w0_wd_in[372]
  PIN w0_wd_in[373]
    DIRECTION OUTPUT ;
    USE SIGNAL ;
    SHAPE ABUTMENT ;
    PORT
      LAYER met2 ;
      RECT 271.790 0.000 271.930 0.420 ;
    END
  END w0_wd_in[373]
  PIN w0_wd_in[374]
    DIRECTION OUTPUT ;
    USE SIGNAL ;
    SHAPE ABUTMENT ;
    PORT
      LAYER met2 ;
      RECT 274.090 0.000 274.230 0.420 ;
    END
  END w0_wd_in[374]
  PIN w0_wd_in[375]
    DIRECTION OUTPUT ;
    USE SIGNAL ;
    SHAPE ABUTMENT ;
    PORT
      LAYER met2 ;
      RECT 276.390 0.000 276.530 0.420 ;
    END
  END w0_wd_in[375]
  PIN w0_wd_in[376]
    DIRECTION OUTPUT ;
    USE SIGNAL ;
    SHAPE ABUTMENT ;
    PORT
      LAYER met2 ;
      RECT 278.690 0.000 278.830 0.420 ;
    END
  END w0_wd_in[376]
  PIN w0_wd_in[377]
    DIRECTION OUTPUT ;
    USE SIGNAL ;
    SHAPE ABUTMENT ;
    PORT
      LAYER met2 ;
      RECT 280.990 0.000 281.130 0.420 ;
    END
  END w0_wd_in[377]
  PIN w0_wd_in[378]
    DIRECTION OUTPUT ;
    USE SIGNAL ;
    SHAPE ABUTMENT ;
    PORT
      LAYER met2 ;
      RECT 283.290 0.000 283.430 0.420 ;
    END
  END w0_wd_in[378]
  PIN w0_wd_in[379]
    DIRECTION OUTPUT ;
    USE SIGNAL ;
    SHAPE ABUTMENT ;
    PORT
      LAYER met2 ;
      RECT 285.590 0.000 285.730 0.420 ;
    END
  END w0_wd_in[379]
  PIN w0_wd_in[380]
    DIRECTION OUTPUT ;
    USE SIGNAL ;
    SHAPE ABUTMENT ;
    PORT
      LAYER met2 ;
      RECT 287.890 0.000 288.030 0.420 ;
    END
  END w0_wd_in[380]
  PIN w0_wd_in[381]
    DIRECTION OUTPUT ;
    USE SIGNAL ;
    SHAPE ABUTMENT ;
    PORT
      LAYER met2 ;
      RECT 290.190 0.000 290.330 0.420 ;
    END
  END w0_wd_in[381]
  PIN w0_wd_in[382]
    DIRECTION OUTPUT ;
    USE SIGNAL ;
    SHAPE ABUTMENT ;
    PORT
      LAYER met2 ;
      RECT 292.490 0.000 292.630 0.420 ;
    END
  END w0_wd_in[382]
  PIN w0_wd_in[383]
    DIRECTION OUTPUT ;
    USE SIGNAL ;
    SHAPE ABUTMENT ;
    PORT
      LAYER met2 ;
      RECT 294.790 0.000 294.930 0.420 ;
    END
  END w0_wd_in[383]
  PIN w0_wd_in[384]
    DIRECTION OUTPUT ;
    USE SIGNAL ;
    SHAPE ABUTMENT ;
    PORT
      LAYER met2 ;
      RECT 297.090 0.000 297.230 0.420 ;
    END
  END w0_wd_in[384]
  PIN w0_wd_in[385]
    DIRECTION OUTPUT ;
    USE SIGNAL ;
    SHAPE ABUTMENT ;
    PORT
      LAYER met2 ;
      RECT 299.390 0.000 299.530 0.420 ;
    END
  END w0_wd_in[385]
  PIN w0_wd_in[386]
    DIRECTION OUTPUT ;
    USE SIGNAL ;
    SHAPE ABUTMENT ;
    PORT
      LAYER met2 ;
      RECT 301.690 0.000 301.830 0.420 ;
    END
  END w0_wd_in[386]
  PIN w0_wd_in[387]
    DIRECTION OUTPUT ;
    USE SIGNAL ;
    SHAPE ABUTMENT ;
    PORT
      LAYER met2 ;
      RECT 303.990 0.000 304.130 0.420 ;
    END
  END w0_wd_in[387]
  PIN w0_wd_in[388]
    DIRECTION OUTPUT ;
    USE SIGNAL ;
    SHAPE ABUTMENT ;
    PORT
      LAYER met2 ;
      RECT 306.290 0.000 306.430 0.420 ;
    END
  END w0_wd_in[388]
  PIN w0_wd_in[389]
    DIRECTION OUTPUT ;
    USE SIGNAL ;
    SHAPE ABUTMENT ;
    PORT
      LAYER met2 ;
      RECT 308.590 0.000 308.730 0.420 ;
    END
  END w0_wd_in[389]
  PIN w0_wd_in[390]
    DIRECTION OUTPUT ;
    USE SIGNAL ;
    SHAPE ABUTMENT ;
    PORT
      LAYER met2 ;
      RECT 310.890 0.000 311.030 0.420 ;
    END
  END w0_wd_in[390]
  PIN w0_wd_in[391]
    DIRECTION OUTPUT ;
    USE SIGNAL ;
    SHAPE ABUTMENT ;
    PORT
      LAYER met2 ;
      RECT 313.190 0.000 313.330 0.420 ;
    END
  END w0_wd_in[391]
  PIN w0_wd_in[392]
    DIRECTION OUTPUT ;
    USE SIGNAL ;
    SHAPE ABUTMENT ;
    PORT
      LAYER met2 ;
      RECT 315.490 0.000 315.630 0.420 ;
    END
  END w0_wd_in[392]
  PIN w0_wd_in[393]
    DIRECTION OUTPUT ;
    USE SIGNAL ;
    SHAPE ABUTMENT ;
    PORT
      LAYER met2 ;
      RECT 317.790 0.000 317.930 0.420 ;
    END
  END w0_wd_in[393]
  PIN w0_wd_in[394]
    DIRECTION OUTPUT ;
    USE SIGNAL ;
    SHAPE ABUTMENT ;
    PORT
      LAYER met2 ;
      RECT 320.090 0.000 320.230 0.420 ;
    END
  END w0_wd_in[394]
  PIN w0_wd_in[395]
    DIRECTION OUTPUT ;
    USE SIGNAL ;
    SHAPE ABUTMENT ;
    PORT
      LAYER met2 ;
      RECT 322.390 0.000 322.530 0.420 ;
    END
  END w0_wd_in[395]
  PIN w0_wd_in[396]
    DIRECTION OUTPUT ;
    USE SIGNAL ;
    SHAPE ABUTMENT ;
    PORT
      LAYER met2 ;
      RECT 324.690 0.000 324.830 0.420 ;
    END
  END w0_wd_in[396]
  PIN w0_wd_in[397]
    DIRECTION OUTPUT ;
    USE SIGNAL ;
    SHAPE ABUTMENT ;
    PORT
      LAYER met2 ;
      RECT 326.990 0.000 327.130 0.420 ;
    END
  END w0_wd_in[397]
  PIN w0_wd_in[398]
    DIRECTION OUTPUT ;
    USE SIGNAL ;
    SHAPE ABUTMENT ;
    PORT
      LAYER met2 ;
      RECT 329.290 0.000 329.430 0.420 ;
    END
  END w0_wd_in[398]
  PIN w0_wd_in[399]
    DIRECTION OUTPUT ;
    USE SIGNAL ;
    SHAPE ABUTMENT ;
    PORT
      LAYER met2 ;
      RECT 331.590 0.000 331.730 0.420 ;
    END
  END w0_wd_in[399]
  PIN w0_wd_in[400]
    DIRECTION OUTPUT ;
    USE SIGNAL ;
    SHAPE ABUTMENT ;
    PORT
      LAYER met2 ;
      RECT 333.890 0.000 334.030 0.420 ;
    END
  END w0_wd_in[400]
  PIN w0_wd_in[401]
    DIRECTION OUTPUT ;
    USE SIGNAL ;
    SHAPE ABUTMENT ;
    PORT
      LAYER met2 ;
      RECT 336.190 0.000 336.330 0.420 ;
    END
  END w0_wd_in[401]
  PIN w0_wd_in[402]
    DIRECTION OUTPUT ;
    USE SIGNAL ;
    SHAPE ABUTMENT ;
    PORT
      LAYER met2 ;
      RECT 338.490 0.000 338.630 0.420 ;
    END
  END w0_wd_in[402]
  PIN w0_wd_in[403]
    DIRECTION OUTPUT ;
    USE SIGNAL ;
    SHAPE ABUTMENT ;
    PORT
      LAYER met2 ;
      RECT 340.790 0.000 340.930 0.420 ;
    END
  END w0_wd_in[403]
  PIN w0_wd_in[404]
    DIRECTION OUTPUT ;
    USE SIGNAL ;
    SHAPE ABUTMENT ;
    PORT
      LAYER met2 ;
      RECT 343.090 0.000 343.230 0.420 ;
    END
  END w0_wd_in[404]
  PIN w0_wd_in[405]
    DIRECTION OUTPUT ;
    USE SIGNAL ;
    SHAPE ABUTMENT ;
    PORT
      LAYER met2 ;
      RECT 345.390 0.000 345.530 0.420 ;
    END
  END w0_wd_in[405]
  PIN w0_wd_in[406]
    DIRECTION OUTPUT ;
    USE SIGNAL ;
    SHAPE ABUTMENT ;
    PORT
      LAYER met2 ;
      RECT 347.690 0.000 347.830 0.420 ;
    END
  END w0_wd_in[406]
  PIN w0_wd_in[407]
    DIRECTION OUTPUT ;
    USE SIGNAL ;
    SHAPE ABUTMENT ;
    PORT
      LAYER met2 ;
      RECT 349.990 0.000 350.130 0.420 ;
    END
  END w0_wd_in[407]
  PIN w0_wd_in[408]
    DIRECTION OUTPUT ;
    USE SIGNAL ;
    SHAPE ABUTMENT ;
    PORT
      LAYER met2 ;
      RECT 352.290 0.000 352.430 0.420 ;
    END
  END w0_wd_in[408]
  PIN w0_wd_in[409]
    DIRECTION OUTPUT ;
    USE SIGNAL ;
    SHAPE ABUTMENT ;
    PORT
      LAYER met2 ;
      RECT 354.590 0.000 354.730 0.420 ;
    END
  END w0_wd_in[409]
  PIN w0_wd_in[410]
    DIRECTION OUTPUT ;
    USE SIGNAL ;
    SHAPE ABUTMENT ;
    PORT
      LAYER met2 ;
      RECT 356.890 0.000 357.030 0.420 ;
    END
  END w0_wd_in[410]
  PIN w0_wd_in[411]
    DIRECTION OUTPUT ;
    USE SIGNAL ;
    SHAPE ABUTMENT ;
    PORT
      LAYER met2 ;
      RECT 359.190 0.000 359.330 0.420 ;
    END
  END w0_wd_in[411]
  PIN w0_wd_in[412]
    DIRECTION OUTPUT ;
    USE SIGNAL ;
    SHAPE ABUTMENT ;
    PORT
      LAYER met2 ;
      RECT 361.490 0.000 361.630 0.420 ;
    END
  END w0_wd_in[412]
  PIN w0_wd_in[413]
    DIRECTION OUTPUT ;
    USE SIGNAL ;
    SHAPE ABUTMENT ;
    PORT
      LAYER met2 ;
      RECT 363.790 0.000 363.930 0.420 ;
    END
  END w0_wd_in[413]
  PIN w0_wd_in[414]
    DIRECTION OUTPUT ;
    USE SIGNAL ;
    SHAPE ABUTMENT ;
    PORT
      LAYER met2 ;
      RECT 366.090 0.000 366.230 0.420 ;
    END
  END w0_wd_in[414]
  PIN w0_wd_in[415]
    DIRECTION OUTPUT ;
    USE SIGNAL ;
    SHAPE ABUTMENT ;
    PORT
      LAYER met2 ;
      RECT 368.390 0.000 368.530 0.420 ;
    END
  END w0_wd_in[415]
  PIN w0_wd_in[416]
    DIRECTION OUTPUT ;
    USE SIGNAL ;
    SHAPE ABUTMENT ;
    PORT
      LAYER met2 ;
      RECT 370.690 0.000 370.830 0.420 ;
    END
  END w0_wd_in[416]
  PIN w0_wd_in[417]
    DIRECTION OUTPUT ;
    USE SIGNAL ;
    SHAPE ABUTMENT ;
    PORT
      LAYER met2 ;
      RECT 372.990 0.000 373.130 0.420 ;
    END
  END w0_wd_in[417]
  PIN w0_wd_in[418]
    DIRECTION OUTPUT ;
    USE SIGNAL ;
    SHAPE ABUTMENT ;
    PORT
      LAYER met2 ;
      RECT 375.290 0.000 375.430 0.420 ;
    END
  END w0_wd_in[418]
  PIN w0_wd_in[419]
    DIRECTION OUTPUT ;
    USE SIGNAL ;
    SHAPE ABUTMENT ;
    PORT
      LAYER met2 ;
      RECT 377.590 0.000 377.730 0.420 ;
    END
  END w0_wd_in[419]
  PIN w0_wd_in[420]
    DIRECTION OUTPUT ;
    USE SIGNAL ;
    SHAPE ABUTMENT ;
    PORT
      LAYER met2 ;
      RECT 379.890 0.000 380.030 0.420 ;
    END
  END w0_wd_in[420]
  PIN w0_wd_in[421]
    DIRECTION OUTPUT ;
    USE SIGNAL ;
    SHAPE ABUTMENT ;
    PORT
      LAYER met2 ;
      RECT 382.190 0.000 382.330 0.420 ;
    END
  END w0_wd_in[421]
  PIN w0_wd_in[422]
    DIRECTION OUTPUT ;
    USE SIGNAL ;
    SHAPE ABUTMENT ;
    PORT
      LAYER met2 ;
      RECT 384.490 0.000 384.630 0.420 ;
    END
  END w0_wd_in[422]
  PIN w0_wd_in[423]
    DIRECTION OUTPUT ;
    USE SIGNAL ;
    SHAPE ABUTMENT ;
    PORT
      LAYER met2 ;
      RECT 386.790 0.000 386.930 0.420 ;
    END
  END w0_wd_in[423]
  PIN w0_wd_in[424]
    DIRECTION OUTPUT ;
    USE SIGNAL ;
    SHAPE ABUTMENT ;
    PORT
      LAYER met2 ;
      RECT 389.090 0.000 389.230 0.420 ;
    END
  END w0_wd_in[424]
  PIN w0_wd_in[425]
    DIRECTION OUTPUT ;
    USE SIGNAL ;
    SHAPE ABUTMENT ;
    PORT
      LAYER met2 ;
      RECT 391.390 0.000 391.530 0.420 ;
    END
  END w0_wd_in[425]
  PIN w0_wd_in[426]
    DIRECTION OUTPUT ;
    USE SIGNAL ;
    SHAPE ABUTMENT ;
    PORT
      LAYER met2 ;
      RECT 393.690 0.000 393.830 0.420 ;
    END
  END w0_wd_in[426]
  PIN w0_wd_in[427]
    DIRECTION OUTPUT ;
    USE SIGNAL ;
    SHAPE ABUTMENT ;
    PORT
      LAYER met2 ;
      RECT 395.990 0.000 396.130 0.420 ;
    END
  END w0_wd_in[427]
  PIN w0_wd_in[428]
    DIRECTION OUTPUT ;
    USE SIGNAL ;
    SHAPE ABUTMENT ;
    PORT
      LAYER met2 ;
      RECT 398.290 0.000 398.430 0.420 ;
    END
  END w0_wd_in[428]
  PIN w0_wd_in[429]
    DIRECTION OUTPUT ;
    USE SIGNAL ;
    SHAPE ABUTMENT ;
    PORT
      LAYER met2 ;
      RECT 400.590 0.000 400.730 0.420 ;
    END
  END w0_wd_in[429]
  PIN w0_wd_in[430]
    DIRECTION OUTPUT ;
    USE SIGNAL ;
    SHAPE ABUTMENT ;
    PORT
      LAYER met2 ;
      RECT 402.890 0.000 403.030 0.420 ;
    END
  END w0_wd_in[430]
  PIN w0_wd_in[431]
    DIRECTION OUTPUT ;
    USE SIGNAL ;
    SHAPE ABUTMENT ;
    PORT
      LAYER met2 ;
      RECT 405.190 0.000 405.330 0.420 ;
    END
  END w0_wd_in[431]
  PIN w0_wd_in[432]
    DIRECTION OUTPUT ;
    USE SIGNAL ;
    SHAPE ABUTMENT ;
    PORT
      LAYER met2 ;
      RECT 407.490 0.000 407.630 0.420 ;
    END
  END w0_wd_in[432]
  PIN w0_wd_in[433]
    DIRECTION OUTPUT ;
    USE SIGNAL ;
    SHAPE ABUTMENT ;
    PORT
      LAYER met2 ;
      RECT 409.790 0.000 409.930 0.420 ;
    END
  END w0_wd_in[433]
  PIN w0_wd_in[434]
    DIRECTION OUTPUT ;
    USE SIGNAL ;
    SHAPE ABUTMENT ;
    PORT
      LAYER met2 ;
      RECT 412.090 0.000 412.230 0.420 ;
    END
  END w0_wd_in[434]
  PIN w0_wd_in[435]
    DIRECTION OUTPUT ;
    USE SIGNAL ;
    SHAPE ABUTMENT ;
    PORT
      LAYER met2 ;
      RECT 414.390 0.000 414.530 0.420 ;
    END
  END w0_wd_in[435]
  PIN w0_wd_in[436]
    DIRECTION OUTPUT ;
    USE SIGNAL ;
    SHAPE ABUTMENT ;
    PORT
      LAYER met2 ;
      RECT 416.690 0.000 416.830 0.420 ;
    END
  END w0_wd_in[436]
  PIN w0_wd_in[437]
    DIRECTION OUTPUT ;
    USE SIGNAL ;
    SHAPE ABUTMENT ;
    PORT
      LAYER met2 ;
      RECT 418.990 0.000 419.130 0.420 ;
    END
  END w0_wd_in[437]
  PIN w0_wd_in[438]
    DIRECTION OUTPUT ;
    USE SIGNAL ;
    SHAPE ABUTMENT ;
    PORT
      LAYER met2 ;
      RECT 421.290 0.000 421.430 0.420 ;
    END
  END w0_wd_in[438]
  PIN w0_wd_in[439]
    DIRECTION OUTPUT ;
    USE SIGNAL ;
    SHAPE ABUTMENT ;
    PORT
      LAYER met2 ;
      RECT 423.590 0.000 423.730 0.420 ;
    END
  END w0_wd_in[439]
  PIN w0_wd_in[440]
    DIRECTION OUTPUT ;
    USE SIGNAL ;
    SHAPE ABUTMENT ;
    PORT
      LAYER met2 ;
      RECT 425.890 0.000 426.030 0.420 ;
    END
  END w0_wd_in[440]
  PIN w0_wd_in[441]
    DIRECTION OUTPUT ;
    USE SIGNAL ;
    SHAPE ABUTMENT ;
    PORT
      LAYER met2 ;
      RECT 428.190 0.000 428.330 0.420 ;
    END
  END w0_wd_in[441]
  PIN w0_wd_in[442]
    DIRECTION OUTPUT ;
    USE SIGNAL ;
    SHAPE ABUTMENT ;
    PORT
      LAYER met2 ;
      RECT 430.490 0.000 430.630 0.420 ;
    END
  END w0_wd_in[442]
  PIN w0_wd_in[443]
    DIRECTION OUTPUT ;
    USE SIGNAL ;
    SHAPE ABUTMENT ;
    PORT
      LAYER met2 ;
      RECT 432.790 0.000 432.930 0.420 ;
    END
  END w0_wd_in[443]
  PIN w0_wd_in[444]
    DIRECTION OUTPUT ;
    USE SIGNAL ;
    SHAPE ABUTMENT ;
    PORT
      LAYER met2 ;
      RECT 435.090 0.000 435.230 0.420 ;
    END
  END w0_wd_in[444]
  PIN w0_wd_in[445]
    DIRECTION OUTPUT ;
    USE SIGNAL ;
    SHAPE ABUTMENT ;
    PORT
      LAYER met2 ;
      RECT 437.390 0.000 437.530 0.420 ;
    END
  END w0_wd_in[445]
  PIN w0_wd_in[446]
    DIRECTION OUTPUT ;
    USE SIGNAL ;
    SHAPE ABUTMENT ;
    PORT
      LAYER met2 ;
      RECT 439.690 0.000 439.830 0.420 ;
    END
  END w0_wd_in[446]
  PIN w0_wd_in[447]
    DIRECTION OUTPUT ;
    USE SIGNAL ;
    SHAPE ABUTMENT ;
    PORT
      LAYER met2 ;
      RECT 441.990 0.000 442.130 0.420 ;
    END
  END w0_wd_in[447]
  PIN w0_wd_in[448]
    DIRECTION OUTPUT ;
    USE SIGNAL ;
    SHAPE ABUTMENT ;
    PORT
      LAYER met2 ;
      RECT 444.290 0.000 444.430 0.420 ;
    END
  END w0_wd_in[448]
  PIN w0_wd_in[449]
    DIRECTION OUTPUT ;
    USE SIGNAL ;
    SHAPE ABUTMENT ;
    PORT
      LAYER met2 ;
      RECT 446.590 0.000 446.730 0.420 ;
    END
  END w0_wd_in[449]
  PIN w0_wd_in[450]
    DIRECTION OUTPUT ;
    USE SIGNAL ;
    SHAPE ABUTMENT ;
    PORT
      LAYER met2 ;
      RECT 448.890 0.000 449.030 0.420 ;
    END
  END w0_wd_in[450]
  PIN w0_wd_in[451]
    DIRECTION OUTPUT ;
    USE SIGNAL ;
    SHAPE ABUTMENT ;
    PORT
      LAYER met2 ;
      RECT 451.190 0.000 451.330 0.420 ;
    END
  END w0_wd_in[451]
  PIN w0_wd_in[452]
    DIRECTION OUTPUT ;
    USE SIGNAL ;
    SHAPE ABUTMENT ;
    PORT
      LAYER met2 ;
      RECT 453.490 0.000 453.630 0.420 ;
    END
  END w0_wd_in[452]
  PIN w0_wd_in[453]
    DIRECTION OUTPUT ;
    USE SIGNAL ;
    SHAPE ABUTMENT ;
    PORT
      LAYER met2 ;
      RECT 455.790 0.000 455.930 0.420 ;
    END
  END w0_wd_in[453]
  PIN w0_wd_in[454]
    DIRECTION OUTPUT ;
    USE SIGNAL ;
    SHAPE ABUTMENT ;
    PORT
      LAYER met2 ;
      RECT 458.090 0.000 458.230 0.420 ;
    END
  END w0_wd_in[454]
  PIN w0_wd_in[455]
    DIRECTION OUTPUT ;
    USE SIGNAL ;
    SHAPE ABUTMENT ;
    PORT
      LAYER met2 ;
      RECT 460.390 0.000 460.530 0.420 ;
    END
  END w0_wd_in[455]
  PIN w0_wd_in[456]
    DIRECTION OUTPUT ;
    USE SIGNAL ;
    SHAPE ABUTMENT ;
    PORT
      LAYER met2 ;
      RECT 462.690 0.000 462.830 0.420 ;
    END
  END w0_wd_in[456]
  PIN w0_wd_in[457]
    DIRECTION OUTPUT ;
    USE SIGNAL ;
    SHAPE ABUTMENT ;
    PORT
      LAYER met2 ;
      RECT 464.990 0.000 465.130 0.420 ;
    END
  END w0_wd_in[457]
  PIN w0_wd_in[458]
    DIRECTION OUTPUT ;
    USE SIGNAL ;
    SHAPE ABUTMENT ;
    PORT
      LAYER met2 ;
      RECT 467.290 0.000 467.430 0.420 ;
    END
  END w0_wd_in[458]
  PIN w0_wd_in[459]
    DIRECTION OUTPUT ;
    USE SIGNAL ;
    SHAPE ABUTMENT ;
    PORT
      LAYER met2 ;
      RECT 469.590 0.000 469.730 0.420 ;
    END
  END w0_wd_in[459]
  PIN w0_wd_in[460]
    DIRECTION OUTPUT ;
    USE SIGNAL ;
    SHAPE ABUTMENT ;
    PORT
      LAYER met2 ;
      RECT 471.890 0.000 472.030 0.420 ;
    END
  END w0_wd_in[460]
  PIN w0_wd_in[461]
    DIRECTION OUTPUT ;
    USE SIGNAL ;
    SHAPE ABUTMENT ;
    PORT
      LAYER met2 ;
      RECT 474.190 0.000 474.330 0.420 ;
    END
  END w0_wd_in[461]
  PIN w0_wd_in[462]
    DIRECTION OUTPUT ;
    USE SIGNAL ;
    SHAPE ABUTMENT ;
    PORT
      LAYER met2 ;
      RECT 476.490 0.000 476.630 0.420 ;
    END
  END w0_wd_in[462]
  PIN w0_wd_in[463]
    DIRECTION OUTPUT ;
    USE SIGNAL ;
    SHAPE ABUTMENT ;
    PORT
      LAYER met2 ;
      RECT 478.790 0.000 478.930 0.420 ;
    END
  END w0_wd_in[463]
  PIN w0_wd_in[464]
    DIRECTION OUTPUT ;
    USE SIGNAL ;
    SHAPE ABUTMENT ;
    PORT
      LAYER met2 ;
      RECT 481.090 0.000 481.230 0.420 ;
    END
  END w0_wd_in[464]
  PIN w0_wd_in[465]
    DIRECTION OUTPUT ;
    USE SIGNAL ;
    SHAPE ABUTMENT ;
    PORT
      LAYER met2 ;
      RECT 483.390 0.000 483.530 0.420 ;
    END
  END w0_wd_in[465]
  PIN w0_wd_in[466]
    DIRECTION OUTPUT ;
    USE SIGNAL ;
    SHAPE ABUTMENT ;
    PORT
      LAYER met2 ;
      RECT 485.690 0.000 485.830 0.420 ;
    END
  END w0_wd_in[466]
  PIN w0_wd_in[467]
    DIRECTION OUTPUT ;
    USE SIGNAL ;
    SHAPE ABUTMENT ;
    PORT
      LAYER met2 ;
      RECT 487.990 0.000 488.130 0.420 ;
    END
  END w0_wd_in[467]
  PIN w0_wd_in[468]
    DIRECTION OUTPUT ;
    USE SIGNAL ;
    SHAPE ABUTMENT ;
    PORT
      LAYER met2 ;
      RECT 490.290 0.000 490.430 0.420 ;
    END
  END w0_wd_in[468]
  PIN w0_wd_in[469]
    DIRECTION OUTPUT ;
    USE SIGNAL ;
    SHAPE ABUTMENT ;
    PORT
      LAYER met2 ;
      RECT 492.590 0.000 492.730 0.420 ;
    END
  END w0_wd_in[469]
  PIN w0_wd_in[470]
    DIRECTION OUTPUT ;
    USE SIGNAL ;
    SHAPE ABUTMENT ;
    PORT
      LAYER met2 ;
      RECT 494.890 0.000 495.030 0.420 ;
    END
  END w0_wd_in[470]
  PIN w0_wd_in[471]
    DIRECTION OUTPUT ;
    USE SIGNAL ;
    SHAPE ABUTMENT ;
    PORT
      LAYER met2 ;
      RECT 497.190 0.000 497.330 0.420 ;
    END
  END w0_wd_in[471]
  PIN w0_wd_in[472]
    DIRECTION OUTPUT ;
    USE SIGNAL ;
    SHAPE ABUTMENT ;
    PORT
      LAYER met2 ;
      RECT 499.490 0.000 499.630 0.420 ;
    END
  END w0_wd_in[472]
  PIN w0_wd_in[473]
    DIRECTION OUTPUT ;
    USE SIGNAL ;
    SHAPE ABUTMENT ;
    PORT
      LAYER met2 ;
      RECT 501.790 0.000 501.930 0.420 ;
    END
  END w0_wd_in[473]
  PIN w0_wd_in[474]
    DIRECTION OUTPUT ;
    USE SIGNAL ;
    SHAPE ABUTMENT ;
    PORT
      LAYER met2 ;
      RECT 504.090 0.000 504.230 0.420 ;
    END
  END w0_wd_in[474]
  PIN w0_wd_in[475]
    DIRECTION OUTPUT ;
    USE SIGNAL ;
    SHAPE ABUTMENT ;
    PORT
      LAYER met2 ;
      RECT 506.390 0.000 506.530 0.420 ;
    END
  END w0_wd_in[475]
  PIN w0_wd_in[476]
    DIRECTION OUTPUT ;
    USE SIGNAL ;
    SHAPE ABUTMENT ;
    PORT
      LAYER met2 ;
      RECT 508.690 0.000 508.830 0.420 ;
    END
  END w0_wd_in[476]
  PIN w0_wd_in[477]
    DIRECTION OUTPUT ;
    USE SIGNAL ;
    SHAPE ABUTMENT ;
    PORT
      LAYER met2 ;
      RECT 510.990 0.000 511.130 0.420 ;
    END
  END w0_wd_in[477]
  PIN w0_wd_in[478]
    DIRECTION OUTPUT ;
    USE SIGNAL ;
    SHAPE ABUTMENT ;
    PORT
      LAYER met2 ;
      RECT 513.290 0.000 513.430 0.420 ;
    END
  END w0_wd_in[478]
  PIN w0_wd_in[479]
    DIRECTION OUTPUT ;
    USE SIGNAL ;
    SHAPE ABUTMENT ;
    PORT
      LAYER met2 ;
      RECT 515.590 0.000 515.730 0.420 ;
    END
  END w0_wd_in[479]
  PIN w0_wd_in[480]
    DIRECTION OUTPUT ;
    USE SIGNAL ;
    SHAPE ABUTMENT ;
    PORT
      LAYER met2 ;
      RECT 517.890 0.000 518.030 0.420 ;
    END
  END w0_wd_in[480]
  PIN w0_wd_in[481]
    DIRECTION OUTPUT ;
    USE SIGNAL ;
    SHAPE ABUTMENT ;
    PORT
      LAYER met2 ;
      RECT 520.190 0.000 520.330 0.420 ;
    END
  END w0_wd_in[481]
  PIN w0_wd_in[482]
    DIRECTION OUTPUT ;
    USE SIGNAL ;
    SHAPE ABUTMENT ;
    PORT
      LAYER met2 ;
      RECT 522.490 0.000 522.630 0.420 ;
    END
  END w0_wd_in[482]
  PIN w0_wd_in[483]
    DIRECTION OUTPUT ;
    USE SIGNAL ;
    SHAPE ABUTMENT ;
    PORT
      LAYER met2 ;
      RECT 524.790 0.000 524.930 0.420 ;
    END
  END w0_wd_in[483]
  PIN w0_wd_in[484]
    DIRECTION OUTPUT ;
    USE SIGNAL ;
    SHAPE ABUTMENT ;
    PORT
      LAYER met2 ;
      RECT 527.090 0.000 527.230 0.420 ;
    END
  END w0_wd_in[484]
  PIN w0_wd_in[485]
    DIRECTION OUTPUT ;
    USE SIGNAL ;
    SHAPE ABUTMENT ;
    PORT
      LAYER met2 ;
      RECT 529.390 0.000 529.530 0.420 ;
    END
  END w0_wd_in[485]
  PIN w0_wd_in[486]
    DIRECTION OUTPUT ;
    USE SIGNAL ;
    SHAPE ABUTMENT ;
    PORT
      LAYER met2 ;
      RECT 531.690 0.000 531.830 0.420 ;
    END
  END w0_wd_in[486]
  PIN w0_wd_in[487]
    DIRECTION OUTPUT ;
    USE SIGNAL ;
    SHAPE ABUTMENT ;
    PORT
      LAYER met2 ;
      RECT 533.990 0.000 534.130 0.420 ;
    END
  END w0_wd_in[487]
  PIN w0_wd_in[488]
    DIRECTION OUTPUT ;
    USE SIGNAL ;
    SHAPE ABUTMENT ;
    PORT
      LAYER met2 ;
      RECT 536.290 0.000 536.430 0.420 ;
    END
  END w0_wd_in[488]
  PIN w0_wd_in[489]
    DIRECTION OUTPUT ;
    USE SIGNAL ;
    SHAPE ABUTMENT ;
    PORT
      LAYER met2 ;
      RECT 538.590 0.000 538.730 0.420 ;
    END
  END w0_wd_in[489]
  PIN w0_wd_in[490]
    DIRECTION OUTPUT ;
    USE SIGNAL ;
    SHAPE ABUTMENT ;
    PORT
      LAYER met2 ;
      RECT 540.890 0.000 541.030 0.420 ;
    END
  END w0_wd_in[490]
  PIN w0_wd_in[491]
    DIRECTION OUTPUT ;
    USE SIGNAL ;
    SHAPE ABUTMENT ;
    PORT
      LAYER met2 ;
      RECT 543.190 0.000 543.330 0.420 ;
    END
  END w0_wd_in[491]
  PIN w0_wd_in[492]
    DIRECTION OUTPUT ;
    USE SIGNAL ;
    SHAPE ABUTMENT ;
    PORT
      LAYER met2 ;
      RECT 545.490 0.000 545.630 0.420 ;
    END
  END w0_wd_in[492]
  PIN w0_wd_in[493]
    DIRECTION OUTPUT ;
    USE SIGNAL ;
    SHAPE ABUTMENT ;
    PORT
      LAYER met2 ;
      RECT 547.790 0.000 547.930 0.420 ;
    END
  END w0_wd_in[493]
  PIN w0_wd_in[494]
    DIRECTION OUTPUT ;
    USE SIGNAL ;
    SHAPE ABUTMENT ;
    PORT
      LAYER met2 ;
      RECT 550.090 0.000 550.230 0.420 ;
    END
  END w0_wd_in[494]
  PIN w0_wd_in[495]
    DIRECTION OUTPUT ;
    USE SIGNAL ;
    SHAPE ABUTMENT ;
    PORT
      LAYER met2 ;
      RECT 552.390 0.000 552.530 0.420 ;
    END
  END w0_wd_in[495]
  PIN w0_wd_in[496]
    DIRECTION OUTPUT ;
    USE SIGNAL ;
    SHAPE ABUTMENT ;
    PORT
      LAYER met2 ;
      RECT 554.690 0.000 554.830 0.420 ;
    END
  END w0_wd_in[496]
  PIN w0_wd_in[497]
    DIRECTION OUTPUT ;
    USE SIGNAL ;
    SHAPE ABUTMENT ;
    PORT
      LAYER met2 ;
      RECT 556.990 0.000 557.130 0.420 ;
    END
  END w0_wd_in[497]
  PIN w0_wd_in[498]
    DIRECTION OUTPUT ;
    USE SIGNAL ;
    SHAPE ABUTMENT ;
    PORT
      LAYER met2 ;
      RECT 559.290 0.000 559.430 0.420 ;
    END
  END w0_wd_in[498]
  PIN w0_wd_in[499]
    DIRECTION OUTPUT ;
    USE SIGNAL ;
    SHAPE ABUTMENT ;
    PORT
      LAYER met2 ;
      RECT 561.590 0.000 561.730 0.420 ;
    END
  END w0_wd_in[499]
  PIN w0_wd_in[500]
    DIRECTION OUTPUT ;
    USE SIGNAL ;
    SHAPE ABUTMENT ;
    PORT
      LAYER met2 ;
      RECT 563.890 0.000 564.030 0.420 ;
    END
  END w0_wd_in[500]
  PIN w0_wd_in[501]
    DIRECTION OUTPUT ;
    USE SIGNAL ;
    SHAPE ABUTMENT ;
    PORT
      LAYER met2 ;
      RECT 566.190 0.000 566.330 0.420 ;
    END
  END w0_wd_in[501]
  PIN w0_wd_in[502]
    DIRECTION OUTPUT ;
    USE SIGNAL ;
    SHAPE ABUTMENT ;
    PORT
      LAYER met2 ;
      RECT 568.490 0.000 568.630 0.420 ;
    END
  END w0_wd_in[502]
  PIN w0_wd_in[503]
    DIRECTION OUTPUT ;
    USE SIGNAL ;
    SHAPE ABUTMENT ;
    PORT
      LAYER met2 ;
      RECT 570.790 0.000 570.930 0.420 ;
    END
  END w0_wd_in[503]
  PIN w0_wd_in[504]
    DIRECTION OUTPUT ;
    USE SIGNAL ;
    SHAPE ABUTMENT ;
    PORT
      LAYER met2 ;
      RECT 573.090 0.000 573.230 0.420 ;
    END
  END w0_wd_in[504]
  PIN w0_wd_in[505]
    DIRECTION OUTPUT ;
    USE SIGNAL ;
    SHAPE ABUTMENT ;
    PORT
      LAYER met2 ;
      RECT 575.390 0.000 575.530 0.420 ;
    END
  END w0_wd_in[505]
  PIN w0_wd_in[506]
    DIRECTION OUTPUT ;
    USE SIGNAL ;
    SHAPE ABUTMENT ;
    PORT
      LAYER met2 ;
      RECT 577.690 0.000 577.830 0.420 ;
    END
  END w0_wd_in[506]
  PIN w0_wd_in[507]
    DIRECTION OUTPUT ;
    USE SIGNAL ;
    SHAPE ABUTMENT ;
    PORT
      LAYER met2 ;
      RECT 579.990 0.000 580.130 0.420 ;
    END
  END w0_wd_in[507]
  PIN w0_wd_in[508]
    DIRECTION OUTPUT ;
    USE SIGNAL ;
    SHAPE ABUTMENT ;
    PORT
      LAYER met2 ;
      RECT 582.290 0.000 582.430 0.420 ;
    END
  END w0_wd_in[508]
  PIN w0_wd_in[509]
    DIRECTION OUTPUT ;
    USE SIGNAL ;
    SHAPE ABUTMENT ;
    PORT
      LAYER met2 ;
      RECT 584.590 0.000 584.730 0.420 ;
    END
  END w0_wd_in[509]
  PIN w0_wd_in[510]
    DIRECTION OUTPUT ;
    USE SIGNAL ;
    SHAPE ABUTMENT ;
    PORT
      LAYER met2 ;
      RECT 586.890 0.000 587.030 0.420 ;
    END
  END w0_wd_in[510]
  PIN w0_wd_in[511]
    DIRECTION OUTPUT ;
    USE SIGNAL ;
    SHAPE ABUTMENT ;
    PORT
      LAYER met2 ;
      RECT 589.190 0.000 589.330 0.420 ;
    END
  END w0_wd_in[511]
  PIN r0_rd_out[0]
    DIRECTION OUTPUT ;
    USE SIGNAL ;
    SHAPE ABUTMENT ;
    PORT
      LAYER met2 ;
      RECT 591.490 0.000 591.630 0.420 ;
    END
  END r0_rd_out[0]
  PIN r0_rd_out[1]
    DIRECTION OUTPUT ;
    USE SIGNAL ;
    SHAPE ABUTMENT ;
    PORT
      LAYER met2 ;
      RECT 593.790 0.000 593.930 0.420 ;
    END
  END r0_rd_out[1]
  PIN r0_rd_out[2]
    DIRECTION OUTPUT ;
    USE SIGNAL ;
    SHAPE ABUTMENT ;
    PORT
      LAYER met2 ;
      RECT 596.090 0.000 596.230 0.420 ;
    END
  END r0_rd_out[2]
  PIN r0_rd_out[3]
    DIRECTION OUTPUT ;
    USE SIGNAL ;
    SHAPE ABUTMENT ;
    PORT
      LAYER met2 ;
      RECT 598.390 0.000 598.530 0.420 ;
    END
  END r0_rd_out[3]
  PIN r0_rd_out[4]
    DIRECTION OUTPUT ;
    USE SIGNAL ;
    SHAPE ABUTMENT ;
    PORT
      LAYER met2 ;
      RECT 600.690 0.000 600.830 0.420 ;
    END
  END r0_rd_out[4]
  PIN r0_rd_out[5]
    DIRECTION OUTPUT ;
    USE SIGNAL ;
    SHAPE ABUTMENT ;
    PORT
      LAYER met2 ;
      RECT 602.990 0.000 603.130 0.420 ;
    END
  END r0_rd_out[5]
  PIN r0_rd_out[6]
    DIRECTION OUTPUT ;
    USE SIGNAL ;
    SHAPE ABUTMENT ;
    PORT
      LAYER met2 ;
      RECT 605.290 0.000 605.430 0.420 ;
    END
  END r0_rd_out[6]
  PIN r0_rd_out[7]
    DIRECTION OUTPUT ;
    USE SIGNAL ;
    SHAPE ABUTMENT ;
    PORT
      LAYER met2 ;
      RECT 607.590 0.000 607.730 0.420 ;
    END
  END r0_rd_out[7]
  PIN r0_rd_out[8]
    DIRECTION OUTPUT ;
    USE SIGNAL ;
    SHAPE ABUTMENT ;
    PORT
      LAYER met2 ;
      RECT 609.890 0.000 610.030 0.420 ;
    END
  END r0_rd_out[8]
  PIN r0_rd_out[9]
    DIRECTION OUTPUT ;
    USE SIGNAL ;
    SHAPE ABUTMENT ;
    PORT
      LAYER met2 ;
      RECT 612.190 0.000 612.330 0.420 ;
    END
  END r0_rd_out[9]
  PIN r0_rd_out[10]
    DIRECTION OUTPUT ;
    USE SIGNAL ;
    SHAPE ABUTMENT ;
    PORT
      LAYER met2 ;
      RECT 614.490 0.000 614.630 0.420 ;
    END
  END r0_rd_out[10]
  PIN r0_rd_out[11]
    DIRECTION OUTPUT ;
    USE SIGNAL ;
    SHAPE ABUTMENT ;
    PORT
      LAYER met2 ;
      RECT 616.790 0.000 616.930 0.420 ;
    END
  END r0_rd_out[11]
  PIN r0_rd_out[12]
    DIRECTION OUTPUT ;
    USE SIGNAL ;
    SHAPE ABUTMENT ;
    PORT
      LAYER met2 ;
      RECT 619.090 0.000 619.230 0.420 ;
    END
  END r0_rd_out[12]
  PIN r0_rd_out[13]
    DIRECTION OUTPUT ;
    USE SIGNAL ;
    SHAPE ABUTMENT ;
    PORT
      LAYER met2 ;
      RECT 621.390 0.000 621.530 0.420 ;
    END
  END r0_rd_out[13]
  PIN r0_rd_out[14]
    DIRECTION OUTPUT ;
    USE SIGNAL ;
    SHAPE ABUTMENT ;
    PORT
      LAYER met2 ;
      RECT 623.690 0.000 623.830 0.420 ;
    END
  END r0_rd_out[14]
  PIN r0_rd_out[15]
    DIRECTION OUTPUT ;
    USE SIGNAL ;
    SHAPE ABUTMENT ;
    PORT
      LAYER met2 ;
      RECT 625.990 0.000 626.130 0.420 ;
    END
  END r0_rd_out[15]
  PIN r0_rd_out[16]
    DIRECTION OUTPUT ;
    USE SIGNAL ;
    SHAPE ABUTMENT ;
    PORT
      LAYER met2 ;
      RECT 628.290 0.000 628.430 0.420 ;
    END
  END r0_rd_out[16]
  PIN r0_rd_out[17]
    DIRECTION OUTPUT ;
    USE SIGNAL ;
    SHAPE ABUTMENT ;
    PORT
      LAYER met2 ;
      RECT 630.590 0.000 630.730 0.420 ;
    END
  END r0_rd_out[17]
  PIN r0_rd_out[18]
    DIRECTION OUTPUT ;
    USE SIGNAL ;
    SHAPE ABUTMENT ;
    PORT
      LAYER met2 ;
      RECT 632.890 0.000 633.030 0.420 ;
    END
  END r0_rd_out[18]
  PIN r0_rd_out[19]
    DIRECTION OUTPUT ;
    USE SIGNAL ;
    SHAPE ABUTMENT ;
    PORT
      LAYER met2 ;
      RECT 635.190 0.000 635.330 0.420 ;
    END
  END r0_rd_out[19]
  PIN r0_rd_out[20]
    DIRECTION OUTPUT ;
    USE SIGNAL ;
    SHAPE ABUTMENT ;
    PORT
      LAYER met2 ;
      RECT 637.490 0.000 637.630 0.420 ;
    END
  END r0_rd_out[20]
  PIN r0_rd_out[21]
    DIRECTION OUTPUT ;
    USE SIGNAL ;
    SHAPE ABUTMENT ;
    PORT
      LAYER met2 ;
      RECT 639.790 0.000 639.930 0.420 ;
    END
  END r0_rd_out[21]
  PIN r0_rd_out[22]
    DIRECTION OUTPUT ;
    USE SIGNAL ;
    SHAPE ABUTMENT ;
    PORT
      LAYER met2 ;
      RECT 642.090 0.000 642.230 0.420 ;
    END
  END r0_rd_out[22]
  PIN r0_rd_out[23]
    DIRECTION OUTPUT ;
    USE SIGNAL ;
    SHAPE ABUTMENT ;
    PORT
      LAYER met2 ;
      RECT 644.390 0.000 644.530 0.420 ;
    END
  END r0_rd_out[23]
  PIN r0_rd_out[24]
    DIRECTION OUTPUT ;
    USE SIGNAL ;
    SHAPE ABUTMENT ;
    PORT
      LAYER met2 ;
      RECT 646.690 0.000 646.830 0.420 ;
    END
  END r0_rd_out[24]
  PIN r0_rd_out[25]
    DIRECTION OUTPUT ;
    USE SIGNAL ;
    SHAPE ABUTMENT ;
    PORT
      LAYER met2 ;
      RECT 648.990 0.000 649.130 0.420 ;
    END
  END r0_rd_out[25]
  PIN r0_rd_out[26]
    DIRECTION OUTPUT ;
    USE SIGNAL ;
    SHAPE ABUTMENT ;
    PORT
      LAYER met2 ;
      RECT 651.290 0.000 651.430 0.420 ;
    END
  END r0_rd_out[26]
  PIN r0_rd_out[27]
    DIRECTION OUTPUT ;
    USE SIGNAL ;
    SHAPE ABUTMENT ;
    PORT
      LAYER met2 ;
      RECT 653.590 0.000 653.730 0.420 ;
    END
  END r0_rd_out[27]
  PIN r0_rd_out[28]
    DIRECTION OUTPUT ;
    USE SIGNAL ;
    SHAPE ABUTMENT ;
    PORT
      LAYER met2 ;
      RECT 655.890 0.000 656.030 0.420 ;
    END
  END r0_rd_out[28]
  PIN r0_rd_out[29]
    DIRECTION OUTPUT ;
    USE SIGNAL ;
    SHAPE ABUTMENT ;
    PORT
      LAYER met2 ;
      RECT 658.190 0.000 658.330 0.420 ;
    END
  END r0_rd_out[29]
  PIN r0_rd_out[30]
    DIRECTION OUTPUT ;
    USE SIGNAL ;
    SHAPE ABUTMENT ;
    PORT
      LAYER met2 ;
      RECT 660.490 0.000 660.630 0.420 ;
    END
  END r0_rd_out[30]
  PIN r0_rd_out[31]
    DIRECTION OUTPUT ;
    USE SIGNAL ;
    SHAPE ABUTMENT ;
    PORT
      LAYER met2 ;
      RECT 662.790 0.000 662.930 0.420 ;
    END
  END r0_rd_out[31]
  PIN r0_rd_out[32]
    DIRECTION OUTPUT ;
    USE SIGNAL ;
    SHAPE ABUTMENT ;
    PORT
      LAYER met2 ;
      RECT 665.090 0.000 665.230 0.420 ;
    END
  END r0_rd_out[32]
  PIN r0_rd_out[33]
    DIRECTION OUTPUT ;
    USE SIGNAL ;
    SHAPE ABUTMENT ;
    PORT
      LAYER met2 ;
      RECT 667.390 0.000 667.530 0.420 ;
    END
  END r0_rd_out[33]
  PIN r0_rd_out[34]
    DIRECTION OUTPUT ;
    USE SIGNAL ;
    SHAPE ABUTMENT ;
    PORT
      LAYER met2 ;
      RECT 669.690 0.000 669.830 0.420 ;
    END
  END r0_rd_out[34]
  PIN r0_rd_out[35]
    DIRECTION OUTPUT ;
    USE SIGNAL ;
    SHAPE ABUTMENT ;
    PORT
      LAYER met2 ;
      RECT 671.990 0.000 672.130 0.420 ;
    END
  END r0_rd_out[35]
  PIN r0_rd_out[36]
    DIRECTION OUTPUT ;
    USE SIGNAL ;
    SHAPE ABUTMENT ;
    PORT
      LAYER met2 ;
      RECT 674.290 0.000 674.430 0.420 ;
    END
  END r0_rd_out[36]
  PIN r0_rd_out[37]
    DIRECTION OUTPUT ;
    USE SIGNAL ;
    SHAPE ABUTMENT ;
    PORT
      LAYER met2 ;
      RECT 676.590 0.000 676.730 0.420 ;
    END
  END r0_rd_out[37]
  PIN r0_rd_out[38]
    DIRECTION OUTPUT ;
    USE SIGNAL ;
    SHAPE ABUTMENT ;
    PORT
      LAYER met2 ;
      RECT 678.890 0.000 679.030 0.420 ;
    END
  END r0_rd_out[38]
  PIN r0_rd_out[39]
    DIRECTION OUTPUT ;
    USE SIGNAL ;
    SHAPE ABUTMENT ;
    PORT
      LAYER met2 ;
      RECT 681.190 0.000 681.330 0.420 ;
    END
  END r0_rd_out[39]
  PIN r0_rd_out[40]
    DIRECTION OUTPUT ;
    USE SIGNAL ;
    SHAPE ABUTMENT ;
    PORT
      LAYER met2 ;
      RECT 683.490 0.000 683.630 0.420 ;
    END
  END r0_rd_out[40]
  PIN r0_rd_out[41]
    DIRECTION OUTPUT ;
    USE SIGNAL ;
    SHAPE ABUTMENT ;
    PORT
      LAYER met2 ;
      RECT 685.790 0.000 685.930 0.420 ;
    END
  END r0_rd_out[41]
  PIN r0_rd_out[42]
    DIRECTION OUTPUT ;
    USE SIGNAL ;
    SHAPE ABUTMENT ;
    PORT
      LAYER met2 ;
      RECT 688.090 0.000 688.230 0.420 ;
    END
  END r0_rd_out[42]
  PIN r0_rd_out[43]
    DIRECTION OUTPUT ;
    USE SIGNAL ;
    SHAPE ABUTMENT ;
    PORT
      LAYER met2 ;
      RECT 690.390 0.000 690.530 0.420 ;
    END
  END r0_rd_out[43]
  PIN r0_rd_out[44]
    DIRECTION OUTPUT ;
    USE SIGNAL ;
    SHAPE ABUTMENT ;
    PORT
      LAYER met2 ;
      RECT 692.690 0.000 692.830 0.420 ;
    END
  END r0_rd_out[44]
  PIN r0_rd_out[45]
    DIRECTION OUTPUT ;
    USE SIGNAL ;
    SHAPE ABUTMENT ;
    PORT
      LAYER met2 ;
      RECT 694.990 0.000 695.130 0.420 ;
    END
  END r0_rd_out[45]
  PIN r0_rd_out[46]
    DIRECTION OUTPUT ;
    USE SIGNAL ;
    SHAPE ABUTMENT ;
    PORT
      LAYER met2 ;
      RECT 697.290 0.000 697.430 0.420 ;
    END
  END r0_rd_out[46]
  PIN r0_rd_out[47]
    DIRECTION OUTPUT ;
    USE SIGNAL ;
    SHAPE ABUTMENT ;
    PORT
      LAYER met2 ;
      RECT 699.590 0.000 699.730 0.420 ;
    END
  END r0_rd_out[47]
  PIN r0_rd_out[48]
    DIRECTION OUTPUT ;
    USE SIGNAL ;
    SHAPE ABUTMENT ;
    PORT
      LAYER met2 ;
      RECT 701.890 0.000 702.030 0.420 ;
    END
  END r0_rd_out[48]
  PIN r0_rd_out[49]
    DIRECTION OUTPUT ;
    USE SIGNAL ;
    SHAPE ABUTMENT ;
    PORT
      LAYER met2 ;
      RECT 704.190 0.000 704.330 0.420 ;
    END
  END r0_rd_out[49]
  PIN r0_rd_out[50]
    DIRECTION OUTPUT ;
    USE SIGNAL ;
    SHAPE ABUTMENT ;
    PORT
      LAYER met2 ;
      RECT 706.490 0.000 706.630 0.420 ;
    END
  END r0_rd_out[50]
  PIN r0_rd_out[51]
    DIRECTION OUTPUT ;
    USE SIGNAL ;
    SHAPE ABUTMENT ;
    PORT
      LAYER met2 ;
      RECT 708.790 0.000 708.930 0.420 ;
    END
  END r0_rd_out[51]
  PIN r0_rd_out[52]
    DIRECTION OUTPUT ;
    USE SIGNAL ;
    SHAPE ABUTMENT ;
    PORT
      LAYER met2 ;
      RECT 711.090 0.000 711.230 0.420 ;
    END
  END r0_rd_out[52]
  PIN r0_rd_out[53]
    DIRECTION OUTPUT ;
    USE SIGNAL ;
    SHAPE ABUTMENT ;
    PORT
      LAYER met2 ;
      RECT 713.390 0.000 713.530 0.420 ;
    END
  END r0_rd_out[53]
  PIN r0_rd_out[54]
    DIRECTION OUTPUT ;
    USE SIGNAL ;
    SHAPE ABUTMENT ;
    PORT
      LAYER met2 ;
      RECT 715.690 0.000 715.830 0.420 ;
    END
  END r0_rd_out[54]
  PIN r0_rd_out[55]
    DIRECTION OUTPUT ;
    USE SIGNAL ;
    SHAPE ABUTMENT ;
    PORT
      LAYER met2 ;
      RECT 717.990 0.000 718.130 0.420 ;
    END
  END r0_rd_out[55]
  PIN r0_rd_out[56]
    DIRECTION OUTPUT ;
    USE SIGNAL ;
    SHAPE ABUTMENT ;
    PORT
      LAYER met2 ;
      RECT 720.290 0.000 720.430 0.420 ;
    END
  END r0_rd_out[56]
  PIN r0_rd_out[57]
    DIRECTION OUTPUT ;
    USE SIGNAL ;
    SHAPE ABUTMENT ;
    PORT
      LAYER met2 ;
      RECT 722.590 0.000 722.730 0.420 ;
    END
  END r0_rd_out[57]
  PIN r0_rd_out[58]
    DIRECTION OUTPUT ;
    USE SIGNAL ;
    SHAPE ABUTMENT ;
    PORT
      LAYER met2 ;
      RECT 724.890 0.000 725.030 0.420 ;
    END
  END r0_rd_out[58]
  PIN r0_rd_out[59]
    DIRECTION OUTPUT ;
    USE SIGNAL ;
    SHAPE ABUTMENT ;
    PORT
      LAYER met2 ;
      RECT 727.190 0.000 727.330 0.420 ;
    END
  END r0_rd_out[59]
  PIN r0_rd_out[60]
    DIRECTION OUTPUT ;
    USE SIGNAL ;
    SHAPE ABUTMENT ;
    PORT
      LAYER met2 ;
      RECT 729.490 0.000 729.630 0.420 ;
    END
  END r0_rd_out[60]
  PIN r0_rd_out[61]
    DIRECTION OUTPUT ;
    USE SIGNAL ;
    SHAPE ABUTMENT ;
    PORT
      LAYER met2 ;
      RECT 731.790 0.000 731.930 0.420 ;
    END
  END r0_rd_out[61]
  PIN r0_rd_out[62]
    DIRECTION OUTPUT ;
    USE SIGNAL ;
    SHAPE ABUTMENT ;
    PORT
      LAYER met2 ;
      RECT 734.090 0.000 734.230 0.420 ;
    END
  END r0_rd_out[62]
  PIN r0_rd_out[63]
    DIRECTION OUTPUT ;
    USE SIGNAL ;
    SHAPE ABUTMENT ;
    PORT
      LAYER met2 ;
      RECT 736.390 0.000 736.530 0.420 ;
    END
  END r0_rd_out[63]
  PIN r0_rd_out[64]
    DIRECTION OUTPUT ;
    USE SIGNAL ;
    SHAPE ABUTMENT ;
    PORT
      LAYER met2 ;
      RECT 738.690 0.000 738.830 0.420 ;
    END
  END r0_rd_out[64]
  PIN r0_rd_out[65]
    DIRECTION OUTPUT ;
    USE SIGNAL ;
    SHAPE ABUTMENT ;
    PORT
      LAYER met2 ;
      RECT 740.990 0.000 741.130 0.420 ;
    END
  END r0_rd_out[65]
  PIN r0_rd_out[66]
    DIRECTION OUTPUT ;
    USE SIGNAL ;
    SHAPE ABUTMENT ;
    PORT
      LAYER met2 ;
      RECT 743.290 0.000 743.430 0.420 ;
    END
  END r0_rd_out[66]
  PIN r0_rd_out[67]
    DIRECTION OUTPUT ;
    USE SIGNAL ;
    SHAPE ABUTMENT ;
    PORT
      LAYER met2 ;
      RECT 745.590 0.000 745.730 0.420 ;
    END
  END r0_rd_out[67]
  PIN r0_rd_out[68]
    DIRECTION OUTPUT ;
    USE SIGNAL ;
    SHAPE ABUTMENT ;
    PORT
      LAYER met2 ;
      RECT 747.890 0.000 748.030 0.420 ;
    END
  END r0_rd_out[68]
  PIN r0_rd_out[69]
    DIRECTION OUTPUT ;
    USE SIGNAL ;
    SHAPE ABUTMENT ;
    PORT
      LAYER met2 ;
      RECT 750.190 0.000 750.330 0.420 ;
    END
  END r0_rd_out[69]
  PIN r0_rd_out[70]
    DIRECTION OUTPUT ;
    USE SIGNAL ;
    SHAPE ABUTMENT ;
    PORT
      LAYER met2 ;
      RECT 752.490 0.000 752.630 0.420 ;
    END
  END r0_rd_out[70]
  PIN r0_rd_out[71]
    DIRECTION OUTPUT ;
    USE SIGNAL ;
    SHAPE ABUTMENT ;
    PORT
      LAYER met2 ;
      RECT 754.790 0.000 754.930 0.420 ;
    END
  END r0_rd_out[71]
  PIN r0_rd_out[72]
    DIRECTION OUTPUT ;
    USE SIGNAL ;
    SHAPE ABUTMENT ;
    PORT
      LAYER met2 ;
      RECT 757.090 0.000 757.230 0.420 ;
    END
  END r0_rd_out[72]
  PIN r0_rd_out[73]
    DIRECTION OUTPUT ;
    USE SIGNAL ;
    SHAPE ABUTMENT ;
    PORT
      LAYER met2 ;
      RECT 759.390 0.000 759.530 0.420 ;
    END
  END r0_rd_out[73]
  PIN r0_rd_out[74]
    DIRECTION OUTPUT ;
    USE SIGNAL ;
    SHAPE ABUTMENT ;
    PORT
      LAYER met2 ;
      RECT 761.690 0.000 761.830 0.420 ;
    END
  END r0_rd_out[74]
  PIN r0_rd_out[75]
    DIRECTION OUTPUT ;
    USE SIGNAL ;
    SHAPE ABUTMENT ;
    PORT
      LAYER met2 ;
      RECT 763.990 0.000 764.130 0.420 ;
    END
  END r0_rd_out[75]
  PIN r0_rd_out[76]
    DIRECTION OUTPUT ;
    USE SIGNAL ;
    SHAPE ABUTMENT ;
    PORT
      LAYER met2 ;
      RECT 766.290 0.000 766.430 0.420 ;
    END
  END r0_rd_out[76]
  PIN r0_rd_out[77]
    DIRECTION OUTPUT ;
    USE SIGNAL ;
    SHAPE ABUTMENT ;
    PORT
      LAYER met2 ;
      RECT 768.590 0.000 768.730 0.420 ;
    END
  END r0_rd_out[77]
  PIN r0_rd_out[78]
    DIRECTION OUTPUT ;
    USE SIGNAL ;
    SHAPE ABUTMENT ;
    PORT
      LAYER met2 ;
      RECT 770.890 0.000 771.030 0.420 ;
    END
  END r0_rd_out[78]
  PIN r0_rd_out[79]
    DIRECTION OUTPUT ;
    USE SIGNAL ;
    SHAPE ABUTMENT ;
    PORT
      LAYER met2 ;
      RECT 773.190 0.000 773.330 0.420 ;
    END
  END r0_rd_out[79]
  PIN r0_rd_out[80]
    DIRECTION OUTPUT ;
    USE SIGNAL ;
    SHAPE ABUTMENT ;
    PORT
      LAYER met2 ;
      RECT 775.490 0.000 775.630 0.420 ;
    END
  END r0_rd_out[80]
  PIN r0_rd_out[81]
    DIRECTION OUTPUT ;
    USE SIGNAL ;
    SHAPE ABUTMENT ;
    PORT
      LAYER met2 ;
      RECT 777.790 0.000 777.930 0.420 ;
    END
  END r0_rd_out[81]
  PIN r0_rd_out[82]
    DIRECTION OUTPUT ;
    USE SIGNAL ;
    SHAPE ABUTMENT ;
    PORT
      LAYER met2 ;
      RECT 780.090 0.000 780.230 0.420 ;
    END
  END r0_rd_out[82]
  PIN r0_rd_out[83]
    DIRECTION OUTPUT ;
    USE SIGNAL ;
    SHAPE ABUTMENT ;
    PORT
      LAYER met2 ;
      RECT 782.390 0.000 782.530 0.420 ;
    END
  END r0_rd_out[83]
  PIN r0_rd_out[84]
    DIRECTION OUTPUT ;
    USE SIGNAL ;
    SHAPE ABUTMENT ;
    PORT
      LAYER met2 ;
      RECT 784.690 0.000 784.830 0.420 ;
    END
  END r0_rd_out[84]
  PIN r0_rd_out[85]
    DIRECTION OUTPUT ;
    USE SIGNAL ;
    SHAPE ABUTMENT ;
    PORT
      LAYER met2 ;
      RECT 786.990 0.000 787.130 0.420 ;
    END
  END r0_rd_out[85]
  PIN r0_rd_out[86]
    DIRECTION OUTPUT ;
    USE SIGNAL ;
    SHAPE ABUTMENT ;
    PORT
      LAYER met2 ;
      RECT 789.290 0.000 789.430 0.420 ;
    END
  END r0_rd_out[86]
  PIN r0_rd_out[87]
    DIRECTION OUTPUT ;
    USE SIGNAL ;
    SHAPE ABUTMENT ;
    PORT
      LAYER met2 ;
      RECT 791.590 0.000 791.730 0.420 ;
    END
  END r0_rd_out[87]
  PIN r0_rd_out[88]
    DIRECTION OUTPUT ;
    USE SIGNAL ;
    SHAPE ABUTMENT ;
    PORT
      LAYER met2 ;
      RECT 793.890 0.000 794.030 0.420 ;
    END
  END r0_rd_out[88]
  PIN r0_rd_out[89]
    DIRECTION OUTPUT ;
    USE SIGNAL ;
    SHAPE ABUTMENT ;
    PORT
      LAYER met2 ;
      RECT 796.190 0.000 796.330 0.420 ;
    END
  END r0_rd_out[89]
  PIN r0_rd_out[90]
    DIRECTION OUTPUT ;
    USE SIGNAL ;
    SHAPE ABUTMENT ;
    PORT
      LAYER met2 ;
      RECT 798.490 0.000 798.630 0.420 ;
    END
  END r0_rd_out[90]
  PIN r0_rd_out[91]
    DIRECTION OUTPUT ;
    USE SIGNAL ;
    SHAPE ABUTMENT ;
    PORT
      LAYER met2 ;
      RECT 800.790 0.000 800.930 0.420 ;
    END
  END r0_rd_out[91]
  PIN r0_rd_out[92]
    DIRECTION OUTPUT ;
    USE SIGNAL ;
    SHAPE ABUTMENT ;
    PORT
      LAYER met2 ;
      RECT 803.090 0.000 803.230 0.420 ;
    END
  END r0_rd_out[92]
  PIN r0_rd_out[93]
    DIRECTION OUTPUT ;
    USE SIGNAL ;
    SHAPE ABUTMENT ;
    PORT
      LAYER met2 ;
      RECT 805.390 0.000 805.530 0.420 ;
    END
  END r0_rd_out[93]
  PIN r0_rd_out[94]
    DIRECTION OUTPUT ;
    USE SIGNAL ;
    SHAPE ABUTMENT ;
    PORT
      LAYER met2 ;
      RECT 807.690 0.000 807.830 0.420 ;
    END
  END r0_rd_out[94]
  PIN r0_rd_out[95]
    DIRECTION OUTPUT ;
    USE SIGNAL ;
    SHAPE ABUTMENT ;
    PORT
      LAYER met2 ;
      RECT 809.990 0.000 810.130 0.420 ;
    END
  END r0_rd_out[95]
  PIN r0_rd_out[96]
    DIRECTION OUTPUT ;
    USE SIGNAL ;
    SHAPE ABUTMENT ;
    PORT
      LAYER met2 ;
      RECT 812.290 0.000 812.430 0.420 ;
    END
  END r0_rd_out[96]
  PIN r0_rd_out[97]
    DIRECTION OUTPUT ;
    USE SIGNAL ;
    SHAPE ABUTMENT ;
    PORT
      LAYER met2 ;
      RECT 814.590 0.000 814.730 0.420 ;
    END
  END r0_rd_out[97]
  PIN r0_rd_out[98]
    DIRECTION OUTPUT ;
    USE SIGNAL ;
    SHAPE ABUTMENT ;
    PORT
      LAYER met2 ;
      RECT 816.890 0.000 817.030 0.420 ;
    END
  END r0_rd_out[98]
  PIN r0_rd_out[99]
    DIRECTION OUTPUT ;
    USE SIGNAL ;
    SHAPE ABUTMENT ;
    PORT
      LAYER met2 ;
      RECT 819.190 0.000 819.330 0.420 ;
    END
  END r0_rd_out[99]
  PIN r0_rd_out[100]
    DIRECTION OUTPUT ;
    USE SIGNAL ;
    SHAPE ABUTMENT ;
    PORT
      LAYER met2 ;
      RECT 821.490 0.000 821.630 0.420 ;
    END
  END r0_rd_out[100]
  PIN r0_rd_out[101]
    DIRECTION OUTPUT ;
    USE SIGNAL ;
    SHAPE ABUTMENT ;
    PORT
      LAYER met2 ;
      RECT 823.790 0.000 823.930 0.420 ;
    END
  END r0_rd_out[101]
  PIN r0_rd_out[102]
    DIRECTION OUTPUT ;
    USE SIGNAL ;
    SHAPE ABUTMENT ;
    PORT
      LAYER met2 ;
      RECT 826.090 0.000 826.230 0.420 ;
    END
  END r0_rd_out[102]
  PIN r0_rd_out[103]
    DIRECTION OUTPUT ;
    USE SIGNAL ;
    SHAPE ABUTMENT ;
    PORT
      LAYER met2 ;
      RECT 828.390 0.000 828.530 0.420 ;
    END
  END r0_rd_out[103]
  PIN r0_rd_out[104]
    DIRECTION OUTPUT ;
    USE SIGNAL ;
    SHAPE ABUTMENT ;
    PORT
      LAYER met2 ;
      RECT 830.690 0.000 830.830 0.420 ;
    END
  END r0_rd_out[104]
  PIN r0_rd_out[105]
    DIRECTION OUTPUT ;
    USE SIGNAL ;
    SHAPE ABUTMENT ;
    PORT
      LAYER met2 ;
      RECT 832.990 0.000 833.130 0.420 ;
    END
  END r0_rd_out[105]
  PIN r0_rd_out[106]
    DIRECTION OUTPUT ;
    USE SIGNAL ;
    SHAPE ABUTMENT ;
    PORT
      LAYER met2 ;
      RECT 835.290 0.000 835.430 0.420 ;
    END
  END r0_rd_out[106]
  PIN r0_rd_out[107]
    DIRECTION OUTPUT ;
    USE SIGNAL ;
    SHAPE ABUTMENT ;
    PORT
      LAYER met2 ;
      RECT 837.590 0.000 837.730 0.420 ;
    END
  END r0_rd_out[107]
  PIN r0_rd_out[108]
    DIRECTION OUTPUT ;
    USE SIGNAL ;
    SHAPE ABUTMENT ;
    PORT
      LAYER met2 ;
      RECT 839.890 0.000 840.030 0.420 ;
    END
  END r0_rd_out[108]
  PIN r0_rd_out[109]
    DIRECTION OUTPUT ;
    USE SIGNAL ;
    SHAPE ABUTMENT ;
    PORT
      LAYER met2 ;
      RECT 842.190 0.000 842.330 0.420 ;
    END
  END r0_rd_out[109]
  PIN r0_rd_out[110]
    DIRECTION OUTPUT ;
    USE SIGNAL ;
    SHAPE ABUTMENT ;
    PORT
      LAYER met2 ;
      RECT 844.490 0.000 844.630 0.420 ;
    END
  END r0_rd_out[110]
  PIN r0_rd_out[111]
    DIRECTION OUTPUT ;
    USE SIGNAL ;
    SHAPE ABUTMENT ;
    PORT
      LAYER met2 ;
      RECT 846.790 0.000 846.930 0.420 ;
    END
  END r0_rd_out[111]
  PIN r0_rd_out[112]
    DIRECTION OUTPUT ;
    USE SIGNAL ;
    SHAPE ABUTMENT ;
    PORT
      LAYER met2 ;
      RECT 849.090 0.000 849.230 0.420 ;
    END
  END r0_rd_out[112]
  PIN r0_rd_out[113]
    DIRECTION OUTPUT ;
    USE SIGNAL ;
    SHAPE ABUTMENT ;
    PORT
      LAYER met2 ;
      RECT 851.390 0.000 851.530 0.420 ;
    END
  END r0_rd_out[113]
  PIN r0_rd_out[114]
    DIRECTION OUTPUT ;
    USE SIGNAL ;
    SHAPE ABUTMENT ;
    PORT
      LAYER met2 ;
      RECT 853.690 0.000 853.830 0.420 ;
    END
  END r0_rd_out[114]
  PIN r0_rd_out[115]
    DIRECTION OUTPUT ;
    USE SIGNAL ;
    SHAPE ABUTMENT ;
    PORT
      LAYER met2 ;
      RECT 855.990 0.000 856.130 0.420 ;
    END
  END r0_rd_out[115]
  PIN r0_rd_out[116]
    DIRECTION OUTPUT ;
    USE SIGNAL ;
    SHAPE ABUTMENT ;
    PORT
      LAYER met2 ;
      RECT 858.290 0.000 858.430 0.420 ;
    END
  END r0_rd_out[116]
  PIN r0_rd_out[117]
    DIRECTION OUTPUT ;
    USE SIGNAL ;
    SHAPE ABUTMENT ;
    PORT
      LAYER met2 ;
      RECT 860.590 0.000 860.730 0.420 ;
    END
  END r0_rd_out[117]
  PIN r0_rd_out[118]
    DIRECTION OUTPUT ;
    USE SIGNAL ;
    SHAPE ABUTMENT ;
    PORT
      LAYER met2 ;
      RECT 862.890 0.000 863.030 0.420 ;
    END
  END r0_rd_out[118]
  PIN r0_rd_out[119]
    DIRECTION OUTPUT ;
    USE SIGNAL ;
    SHAPE ABUTMENT ;
    PORT
      LAYER met2 ;
      RECT 865.190 0.000 865.330 0.420 ;
    END
  END r0_rd_out[119]
  PIN r0_rd_out[120]
    DIRECTION OUTPUT ;
    USE SIGNAL ;
    SHAPE ABUTMENT ;
    PORT
      LAYER met2 ;
      RECT 867.490 0.000 867.630 0.420 ;
    END
  END r0_rd_out[120]
  PIN r0_rd_out[121]
    DIRECTION OUTPUT ;
    USE SIGNAL ;
    SHAPE ABUTMENT ;
    PORT
      LAYER met2 ;
      RECT 869.790 0.000 869.930 0.420 ;
    END
  END r0_rd_out[121]
  PIN r0_rd_out[122]
    DIRECTION OUTPUT ;
    USE SIGNAL ;
    SHAPE ABUTMENT ;
    PORT
      LAYER met2 ;
      RECT 872.090 0.000 872.230 0.420 ;
    END
  END r0_rd_out[122]
  PIN r0_rd_out[123]
    DIRECTION OUTPUT ;
    USE SIGNAL ;
    SHAPE ABUTMENT ;
    PORT
      LAYER met2 ;
      RECT 874.390 0.000 874.530 0.420 ;
    END
  END r0_rd_out[123]
  PIN r0_rd_out[124]
    DIRECTION OUTPUT ;
    USE SIGNAL ;
    SHAPE ABUTMENT ;
    PORT
      LAYER met2 ;
      RECT 876.690 0.000 876.830 0.420 ;
    END
  END r0_rd_out[124]
  PIN r0_rd_out[125]
    DIRECTION OUTPUT ;
    USE SIGNAL ;
    SHAPE ABUTMENT ;
    PORT
      LAYER met2 ;
      RECT 878.990 0.000 879.130 0.420 ;
    END
  END r0_rd_out[125]
  PIN r0_rd_out[126]
    DIRECTION OUTPUT ;
    USE SIGNAL ;
    SHAPE ABUTMENT ;
    PORT
      LAYER met2 ;
      RECT 881.290 0.000 881.430 0.420 ;
    END
  END r0_rd_out[126]
  PIN r0_rd_out[127]
    DIRECTION OUTPUT ;
    USE SIGNAL ;
    SHAPE ABUTMENT ;
    PORT
      LAYER met2 ;
      RECT 883.590 0.000 883.730 0.420 ;
    END
  END r0_rd_out[127]
  PIN r0_rd_out[128]
    DIRECTION OUTPUT ;
    USE SIGNAL ;
    SHAPE ABUTMENT ;
    PORT
      LAYER met2 ;
      RECT 885.890 0.000 886.030 0.420 ;
    END
  END r0_rd_out[128]
  PIN r0_rd_out[129]
    DIRECTION OUTPUT ;
    USE SIGNAL ;
    SHAPE ABUTMENT ;
    PORT
      LAYER met2 ;
      RECT 888.190 0.000 888.330 0.420 ;
    END
  END r0_rd_out[129]
  PIN r0_rd_out[130]
    DIRECTION OUTPUT ;
    USE SIGNAL ;
    SHAPE ABUTMENT ;
    PORT
      LAYER met2 ;
      RECT 890.490 0.000 890.630 0.420 ;
    END
  END r0_rd_out[130]
  PIN r0_rd_out[131]
    DIRECTION OUTPUT ;
    USE SIGNAL ;
    SHAPE ABUTMENT ;
    PORT
      LAYER met2 ;
      RECT 892.790 0.000 892.930 0.420 ;
    END
  END r0_rd_out[131]
  PIN r0_rd_out[132]
    DIRECTION OUTPUT ;
    USE SIGNAL ;
    SHAPE ABUTMENT ;
    PORT
      LAYER met2 ;
      RECT 895.090 0.000 895.230 0.420 ;
    END
  END r0_rd_out[132]
  PIN r0_rd_out[133]
    DIRECTION OUTPUT ;
    USE SIGNAL ;
    SHAPE ABUTMENT ;
    PORT
      LAYER met2 ;
      RECT 897.390 0.000 897.530 0.420 ;
    END
  END r0_rd_out[133]
  PIN r0_rd_out[134]
    DIRECTION OUTPUT ;
    USE SIGNAL ;
    SHAPE ABUTMENT ;
    PORT
      LAYER met2 ;
      RECT 899.690 0.000 899.830 0.420 ;
    END
  END r0_rd_out[134]
  PIN r0_rd_out[135]
    DIRECTION OUTPUT ;
    USE SIGNAL ;
    SHAPE ABUTMENT ;
    PORT
      LAYER met2 ;
      RECT 901.990 0.000 902.130 0.420 ;
    END
  END r0_rd_out[135]
  PIN r0_rd_out[136]
    DIRECTION OUTPUT ;
    USE SIGNAL ;
    SHAPE ABUTMENT ;
    PORT
      LAYER met2 ;
      RECT 904.290 0.000 904.430 0.420 ;
    END
  END r0_rd_out[136]
  PIN r0_rd_out[137]
    DIRECTION OUTPUT ;
    USE SIGNAL ;
    SHAPE ABUTMENT ;
    PORT
      LAYER met2 ;
      RECT 906.590 0.000 906.730 0.420 ;
    END
  END r0_rd_out[137]
  PIN r0_rd_out[138]
    DIRECTION OUTPUT ;
    USE SIGNAL ;
    SHAPE ABUTMENT ;
    PORT
      LAYER met2 ;
      RECT 908.890 0.000 909.030 0.420 ;
    END
  END r0_rd_out[138]
  PIN r0_rd_out[139]
    DIRECTION OUTPUT ;
    USE SIGNAL ;
    SHAPE ABUTMENT ;
    PORT
      LAYER met2 ;
      RECT 911.190 0.000 911.330 0.420 ;
    END
  END r0_rd_out[139]
  PIN r0_rd_out[140]
    DIRECTION OUTPUT ;
    USE SIGNAL ;
    SHAPE ABUTMENT ;
    PORT
      LAYER met2 ;
      RECT 913.490 0.000 913.630 0.420 ;
    END
  END r0_rd_out[140]
  PIN r0_rd_out[141]
    DIRECTION OUTPUT ;
    USE SIGNAL ;
    SHAPE ABUTMENT ;
    PORT
      LAYER met2 ;
      RECT 915.790 0.000 915.930 0.420 ;
    END
  END r0_rd_out[141]
  PIN r0_rd_out[142]
    DIRECTION OUTPUT ;
    USE SIGNAL ;
    SHAPE ABUTMENT ;
    PORT
      LAYER met2 ;
      RECT 918.090 0.000 918.230 0.420 ;
    END
  END r0_rd_out[142]
  PIN r0_rd_out[143]
    DIRECTION OUTPUT ;
    USE SIGNAL ;
    SHAPE ABUTMENT ;
    PORT
      LAYER met2 ;
      RECT 920.390 0.000 920.530 0.420 ;
    END
  END r0_rd_out[143]
  PIN r0_rd_out[144]
    DIRECTION OUTPUT ;
    USE SIGNAL ;
    SHAPE ABUTMENT ;
    PORT
      LAYER met2 ;
      RECT 922.690 0.000 922.830 0.420 ;
    END
  END r0_rd_out[144]
  PIN r0_rd_out[145]
    DIRECTION OUTPUT ;
    USE SIGNAL ;
    SHAPE ABUTMENT ;
    PORT
      LAYER met2 ;
      RECT 924.990 0.000 925.130 0.420 ;
    END
  END r0_rd_out[145]
  PIN r0_rd_out[146]
    DIRECTION OUTPUT ;
    USE SIGNAL ;
    SHAPE ABUTMENT ;
    PORT
      LAYER met2 ;
      RECT 927.290 0.000 927.430 0.420 ;
    END
  END r0_rd_out[146]
  PIN r0_rd_out[147]
    DIRECTION OUTPUT ;
    USE SIGNAL ;
    SHAPE ABUTMENT ;
    PORT
      LAYER met2 ;
      RECT 929.590 0.000 929.730 0.420 ;
    END
  END r0_rd_out[147]
  PIN r0_rd_out[148]
    DIRECTION OUTPUT ;
    USE SIGNAL ;
    SHAPE ABUTMENT ;
    PORT
      LAYER met2 ;
      RECT 931.890 0.000 932.030 0.420 ;
    END
  END r0_rd_out[148]
  PIN r0_rd_out[149]
    DIRECTION OUTPUT ;
    USE SIGNAL ;
    SHAPE ABUTMENT ;
    PORT
      LAYER met2 ;
      RECT 934.190 0.000 934.330 0.420 ;
    END
  END r0_rd_out[149]
  PIN r0_rd_out[150]
    DIRECTION OUTPUT ;
    USE SIGNAL ;
    SHAPE ABUTMENT ;
    PORT
      LAYER met2 ;
      RECT 936.490 0.000 936.630 0.420 ;
    END
  END r0_rd_out[150]
  PIN r0_rd_out[151]
    DIRECTION OUTPUT ;
    USE SIGNAL ;
    SHAPE ABUTMENT ;
    PORT
      LAYER met2 ;
      RECT 938.790 0.000 938.930 0.420 ;
    END
  END r0_rd_out[151]
  PIN r0_rd_out[152]
    DIRECTION OUTPUT ;
    USE SIGNAL ;
    SHAPE ABUTMENT ;
    PORT
      LAYER met2 ;
      RECT 941.090 0.000 941.230 0.420 ;
    END
  END r0_rd_out[152]
  PIN r0_rd_out[153]
    DIRECTION OUTPUT ;
    USE SIGNAL ;
    SHAPE ABUTMENT ;
    PORT
      LAYER met2 ;
      RECT 943.390 0.000 943.530 0.420 ;
    END
  END r0_rd_out[153]
  PIN r0_rd_out[154]
    DIRECTION OUTPUT ;
    USE SIGNAL ;
    SHAPE ABUTMENT ;
    PORT
      LAYER met2 ;
      RECT 945.690 0.000 945.830 0.420 ;
    END
  END r0_rd_out[154]
  PIN r0_rd_out[155]
    DIRECTION OUTPUT ;
    USE SIGNAL ;
    SHAPE ABUTMENT ;
    PORT
      LAYER met2 ;
      RECT 947.990 0.000 948.130 0.420 ;
    END
  END r0_rd_out[155]
  PIN r0_rd_out[156]
    DIRECTION OUTPUT ;
    USE SIGNAL ;
    SHAPE ABUTMENT ;
    PORT
      LAYER met2 ;
      RECT 950.290 0.000 950.430 0.420 ;
    END
  END r0_rd_out[156]
  PIN r0_rd_out[157]
    DIRECTION OUTPUT ;
    USE SIGNAL ;
    SHAPE ABUTMENT ;
    PORT
      LAYER met2 ;
      RECT 952.590 0.000 952.730 0.420 ;
    END
  END r0_rd_out[157]
  PIN r0_rd_out[158]
    DIRECTION OUTPUT ;
    USE SIGNAL ;
    SHAPE ABUTMENT ;
    PORT
      LAYER met2 ;
      RECT 954.890 0.000 955.030 0.420 ;
    END
  END r0_rd_out[158]
  PIN r0_rd_out[159]
    DIRECTION OUTPUT ;
    USE SIGNAL ;
    SHAPE ABUTMENT ;
    PORT
      LAYER met2 ;
      RECT 957.190 0.000 957.330 0.420 ;
    END
  END r0_rd_out[159]
  PIN r0_rd_out[160]
    DIRECTION OUTPUT ;
    USE SIGNAL ;
    SHAPE ABUTMENT ;
    PORT
      LAYER met2 ;
      RECT 959.490 0.000 959.630 0.420 ;
    END
  END r0_rd_out[160]
  PIN r0_rd_out[161]
    DIRECTION OUTPUT ;
    USE SIGNAL ;
    SHAPE ABUTMENT ;
    PORT
      LAYER met2 ;
      RECT 961.790 0.000 961.930 0.420 ;
    END
  END r0_rd_out[161]
  PIN r0_rd_out[162]
    DIRECTION OUTPUT ;
    USE SIGNAL ;
    SHAPE ABUTMENT ;
    PORT
      LAYER met2 ;
      RECT 964.090 0.000 964.230 0.420 ;
    END
  END r0_rd_out[162]
  PIN r0_rd_out[163]
    DIRECTION OUTPUT ;
    USE SIGNAL ;
    SHAPE ABUTMENT ;
    PORT
      LAYER met2 ;
      RECT 966.390 0.000 966.530 0.420 ;
    END
  END r0_rd_out[163]
  PIN r0_rd_out[164]
    DIRECTION OUTPUT ;
    USE SIGNAL ;
    SHAPE ABUTMENT ;
    PORT
      LAYER met2 ;
      RECT 968.690 0.000 968.830 0.420 ;
    END
  END r0_rd_out[164]
  PIN r0_rd_out[165]
    DIRECTION OUTPUT ;
    USE SIGNAL ;
    SHAPE ABUTMENT ;
    PORT
      LAYER met2 ;
      RECT 970.990 0.000 971.130 0.420 ;
    END
  END r0_rd_out[165]
  PIN r0_rd_out[166]
    DIRECTION OUTPUT ;
    USE SIGNAL ;
    SHAPE ABUTMENT ;
    PORT
      LAYER met2 ;
      RECT 973.290 0.000 973.430 0.420 ;
    END
  END r0_rd_out[166]
  PIN r0_rd_out[167]
    DIRECTION OUTPUT ;
    USE SIGNAL ;
    SHAPE ABUTMENT ;
    PORT
      LAYER met2 ;
      RECT 975.590 0.000 975.730 0.420 ;
    END
  END r0_rd_out[167]
  PIN r0_rd_out[168]
    DIRECTION OUTPUT ;
    USE SIGNAL ;
    SHAPE ABUTMENT ;
    PORT
      LAYER met2 ;
      RECT 977.890 0.000 978.030 0.420 ;
    END
  END r0_rd_out[168]
  PIN r0_rd_out[169]
    DIRECTION OUTPUT ;
    USE SIGNAL ;
    SHAPE ABUTMENT ;
    PORT
      LAYER met2 ;
      RECT 980.190 0.000 980.330 0.420 ;
    END
  END r0_rd_out[169]
  PIN r0_rd_out[170]
    DIRECTION OUTPUT ;
    USE SIGNAL ;
    SHAPE ABUTMENT ;
    PORT
      LAYER met2 ;
      RECT 982.490 0.000 982.630 0.420 ;
    END
  END r0_rd_out[170]
  PIN r0_rd_out[171]
    DIRECTION OUTPUT ;
    USE SIGNAL ;
    SHAPE ABUTMENT ;
    PORT
      LAYER met2 ;
      RECT 984.790 0.000 984.930 0.420 ;
    END
  END r0_rd_out[171]
  PIN r0_rd_out[172]
    DIRECTION OUTPUT ;
    USE SIGNAL ;
    SHAPE ABUTMENT ;
    PORT
      LAYER met2 ;
      RECT 987.090 0.000 987.230 0.420 ;
    END
  END r0_rd_out[172]
  PIN r0_rd_out[173]
    DIRECTION OUTPUT ;
    USE SIGNAL ;
    SHAPE ABUTMENT ;
    PORT
      LAYER met2 ;
      RECT 989.390 0.000 989.530 0.420 ;
    END
  END r0_rd_out[173]
  PIN r0_rd_out[174]
    DIRECTION OUTPUT ;
    USE SIGNAL ;
    SHAPE ABUTMENT ;
    PORT
      LAYER met2 ;
      RECT 991.690 0.000 991.830 0.420 ;
    END
  END r0_rd_out[174]
  PIN r0_rd_out[175]
    DIRECTION OUTPUT ;
    USE SIGNAL ;
    SHAPE ABUTMENT ;
    PORT
      LAYER met2 ;
      RECT 993.990 0.000 994.130 0.420 ;
    END
  END r0_rd_out[175]
  PIN r0_rd_out[176]
    DIRECTION OUTPUT ;
    USE SIGNAL ;
    SHAPE ABUTMENT ;
    PORT
      LAYER met2 ;
      RECT 996.290 0.000 996.430 0.420 ;
    END
  END r0_rd_out[176]
  PIN r0_rd_out[177]
    DIRECTION OUTPUT ;
    USE SIGNAL ;
    SHAPE ABUTMENT ;
    PORT
      LAYER met2 ;
      RECT 998.590 0.000 998.730 0.420 ;
    END
  END r0_rd_out[177]
  PIN r0_rd_out[178]
    DIRECTION OUTPUT ;
    USE SIGNAL ;
    SHAPE ABUTMENT ;
    PORT
      LAYER met2 ;
      RECT 1000.890 0.000 1001.030 0.420 ;
    END
  END r0_rd_out[178]
  PIN r0_rd_out[179]
    DIRECTION OUTPUT ;
    USE SIGNAL ;
    SHAPE ABUTMENT ;
    PORT
      LAYER met2 ;
      RECT 1003.190 0.000 1003.330 0.420 ;
    END
  END r0_rd_out[179]
  PIN r0_rd_out[180]
    DIRECTION OUTPUT ;
    USE SIGNAL ;
    SHAPE ABUTMENT ;
    PORT
      LAYER met2 ;
      RECT 1005.490 0.000 1005.630 0.420 ;
    END
  END r0_rd_out[180]
  PIN r0_rd_out[181]
    DIRECTION OUTPUT ;
    USE SIGNAL ;
    SHAPE ABUTMENT ;
    PORT
      LAYER met2 ;
      RECT 1007.790 0.000 1007.930 0.420 ;
    END
  END r0_rd_out[181]
  PIN r0_rd_out[182]
    DIRECTION OUTPUT ;
    USE SIGNAL ;
    SHAPE ABUTMENT ;
    PORT
      LAYER met2 ;
      RECT 1010.090 0.000 1010.230 0.420 ;
    END
  END r0_rd_out[182]
  PIN r0_rd_out[183]
    DIRECTION OUTPUT ;
    USE SIGNAL ;
    SHAPE ABUTMENT ;
    PORT
      LAYER met2 ;
      RECT 1012.390 0.000 1012.530 0.420 ;
    END
  END r0_rd_out[183]
  PIN r0_rd_out[184]
    DIRECTION OUTPUT ;
    USE SIGNAL ;
    SHAPE ABUTMENT ;
    PORT
      LAYER met2 ;
      RECT 1014.690 0.000 1014.830 0.420 ;
    END
  END r0_rd_out[184]
  PIN r0_rd_out[185]
    DIRECTION OUTPUT ;
    USE SIGNAL ;
    SHAPE ABUTMENT ;
    PORT
      LAYER met2 ;
      RECT 1016.990 0.000 1017.130 0.420 ;
    END
  END r0_rd_out[185]
  PIN r0_rd_out[186]
    DIRECTION OUTPUT ;
    USE SIGNAL ;
    SHAPE ABUTMENT ;
    PORT
      LAYER met2 ;
      RECT 1019.290 0.000 1019.430 0.420 ;
    END
  END r0_rd_out[186]
  PIN r0_rd_out[187]
    DIRECTION OUTPUT ;
    USE SIGNAL ;
    SHAPE ABUTMENT ;
    PORT
      LAYER met2 ;
      RECT 1021.590 0.000 1021.730 0.420 ;
    END
  END r0_rd_out[187]
  PIN r0_rd_out[188]
    DIRECTION OUTPUT ;
    USE SIGNAL ;
    SHAPE ABUTMENT ;
    PORT
      LAYER met2 ;
      RECT 1023.890 0.000 1024.030 0.420 ;
    END
  END r0_rd_out[188]
  PIN r0_rd_out[189]
    DIRECTION OUTPUT ;
    USE SIGNAL ;
    SHAPE ABUTMENT ;
    PORT
      LAYER met2 ;
      RECT 1026.190 0.000 1026.330 0.420 ;
    END
  END r0_rd_out[189]
  PIN r0_rd_out[190]
    DIRECTION OUTPUT ;
    USE SIGNAL ;
    SHAPE ABUTMENT ;
    PORT
      LAYER met2 ;
      RECT 1028.490 0.000 1028.630 0.420 ;
    END
  END r0_rd_out[190]
  PIN r0_rd_out[191]
    DIRECTION OUTPUT ;
    USE SIGNAL ;
    SHAPE ABUTMENT ;
    PORT
      LAYER met2 ;
      RECT 1030.790 0.000 1030.930 0.420 ;
    END
  END r0_rd_out[191]
  PIN r0_rd_out[192]
    DIRECTION OUTPUT ;
    USE SIGNAL ;
    SHAPE ABUTMENT ;
    PORT
      LAYER met2 ;
      RECT 1033.090 0.000 1033.230 0.420 ;
    END
  END r0_rd_out[192]
  PIN r0_rd_out[193]
    DIRECTION OUTPUT ;
    USE SIGNAL ;
    SHAPE ABUTMENT ;
    PORT
      LAYER met2 ;
      RECT 1035.390 0.000 1035.530 0.420 ;
    END
  END r0_rd_out[193]
  PIN r0_rd_out[194]
    DIRECTION OUTPUT ;
    USE SIGNAL ;
    SHAPE ABUTMENT ;
    PORT
      LAYER met2 ;
      RECT 1037.690 0.000 1037.830 0.420 ;
    END
  END r0_rd_out[194]
  PIN r0_rd_out[195]
    DIRECTION OUTPUT ;
    USE SIGNAL ;
    SHAPE ABUTMENT ;
    PORT
      LAYER met2 ;
      RECT 1039.990 0.000 1040.130 0.420 ;
    END
  END r0_rd_out[195]
  PIN r0_rd_out[196]
    DIRECTION OUTPUT ;
    USE SIGNAL ;
    SHAPE ABUTMENT ;
    PORT
      LAYER met2 ;
      RECT 1042.290 0.000 1042.430 0.420 ;
    END
  END r0_rd_out[196]
  PIN r0_rd_out[197]
    DIRECTION OUTPUT ;
    USE SIGNAL ;
    SHAPE ABUTMENT ;
    PORT
      LAYER met2 ;
      RECT 1044.590 0.000 1044.730 0.420 ;
    END
  END r0_rd_out[197]
  PIN r0_rd_out[198]
    DIRECTION OUTPUT ;
    USE SIGNAL ;
    SHAPE ABUTMENT ;
    PORT
      LAYER met2 ;
      RECT 1046.890 0.000 1047.030 0.420 ;
    END
  END r0_rd_out[198]
  PIN r0_rd_out[199]
    DIRECTION OUTPUT ;
    USE SIGNAL ;
    SHAPE ABUTMENT ;
    PORT
      LAYER met2 ;
      RECT 1049.190 0.000 1049.330 0.420 ;
    END
  END r0_rd_out[199]
  PIN r0_rd_out[200]
    DIRECTION OUTPUT ;
    USE SIGNAL ;
    SHAPE ABUTMENT ;
    PORT
      LAYER met2 ;
      RECT 1051.490 0.000 1051.630 0.420 ;
    END
  END r0_rd_out[200]
  PIN r0_rd_out[201]
    DIRECTION OUTPUT ;
    USE SIGNAL ;
    SHAPE ABUTMENT ;
    PORT
      LAYER met2 ;
      RECT 1053.790 0.000 1053.930 0.420 ;
    END
  END r0_rd_out[201]
  PIN r0_rd_out[202]
    DIRECTION OUTPUT ;
    USE SIGNAL ;
    SHAPE ABUTMENT ;
    PORT
      LAYER met2 ;
      RECT 1056.090 0.000 1056.230 0.420 ;
    END
  END r0_rd_out[202]
  PIN r0_rd_out[203]
    DIRECTION OUTPUT ;
    USE SIGNAL ;
    SHAPE ABUTMENT ;
    PORT
      LAYER met2 ;
      RECT 1058.390 0.000 1058.530 0.420 ;
    END
  END r0_rd_out[203]
  PIN r0_rd_out[204]
    DIRECTION OUTPUT ;
    USE SIGNAL ;
    SHAPE ABUTMENT ;
    PORT
      LAYER met2 ;
      RECT 1060.690 0.000 1060.830 0.420 ;
    END
  END r0_rd_out[204]
  PIN r0_rd_out[205]
    DIRECTION OUTPUT ;
    USE SIGNAL ;
    SHAPE ABUTMENT ;
    PORT
      LAYER met2 ;
      RECT 1062.990 0.000 1063.130 0.420 ;
    END
  END r0_rd_out[205]
  PIN r0_rd_out[206]
    DIRECTION OUTPUT ;
    USE SIGNAL ;
    SHAPE ABUTMENT ;
    PORT
      LAYER met2 ;
      RECT 1065.290 0.000 1065.430 0.420 ;
    END
  END r0_rd_out[206]
  PIN r0_rd_out[207]
    DIRECTION OUTPUT ;
    USE SIGNAL ;
    SHAPE ABUTMENT ;
    PORT
      LAYER met2 ;
      RECT 1067.590 0.000 1067.730 0.420 ;
    END
  END r0_rd_out[207]
  PIN r0_rd_out[208]
    DIRECTION OUTPUT ;
    USE SIGNAL ;
    SHAPE ABUTMENT ;
    PORT
      LAYER met2 ;
      RECT 1069.890 0.000 1070.030 0.420 ;
    END
  END r0_rd_out[208]
  PIN r0_rd_out[209]
    DIRECTION OUTPUT ;
    USE SIGNAL ;
    SHAPE ABUTMENT ;
    PORT
      LAYER met2 ;
      RECT 1072.190 0.000 1072.330 0.420 ;
    END
  END r0_rd_out[209]
  PIN r0_rd_out[210]
    DIRECTION OUTPUT ;
    USE SIGNAL ;
    SHAPE ABUTMENT ;
    PORT
      LAYER met2 ;
      RECT 1074.490 0.000 1074.630 0.420 ;
    END
  END r0_rd_out[210]
  PIN r0_rd_out[211]
    DIRECTION OUTPUT ;
    USE SIGNAL ;
    SHAPE ABUTMENT ;
    PORT
      LAYER met2 ;
      RECT 1076.790 0.000 1076.930 0.420 ;
    END
  END r0_rd_out[211]
  PIN r0_rd_out[212]
    DIRECTION OUTPUT ;
    USE SIGNAL ;
    SHAPE ABUTMENT ;
    PORT
      LAYER met2 ;
      RECT 1079.090 0.000 1079.230 0.420 ;
    END
  END r0_rd_out[212]
  PIN r0_rd_out[213]
    DIRECTION OUTPUT ;
    USE SIGNAL ;
    SHAPE ABUTMENT ;
    PORT
      LAYER met2 ;
      RECT 1081.390 0.000 1081.530 0.420 ;
    END
  END r0_rd_out[213]
  PIN r0_rd_out[214]
    DIRECTION OUTPUT ;
    USE SIGNAL ;
    SHAPE ABUTMENT ;
    PORT
      LAYER met2 ;
      RECT 1083.690 0.000 1083.830 0.420 ;
    END
  END r0_rd_out[214]
  PIN r0_rd_out[215]
    DIRECTION OUTPUT ;
    USE SIGNAL ;
    SHAPE ABUTMENT ;
    PORT
      LAYER met2 ;
      RECT 1085.990 0.000 1086.130 0.420 ;
    END
  END r0_rd_out[215]
  PIN r0_rd_out[216]
    DIRECTION OUTPUT ;
    USE SIGNAL ;
    SHAPE ABUTMENT ;
    PORT
      LAYER met2 ;
      RECT 1088.290 0.000 1088.430 0.420 ;
    END
  END r0_rd_out[216]
  PIN r0_rd_out[217]
    DIRECTION OUTPUT ;
    USE SIGNAL ;
    SHAPE ABUTMENT ;
    PORT
      LAYER met2 ;
      RECT 1090.590 0.000 1090.730 0.420 ;
    END
  END r0_rd_out[217]
  PIN r0_rd_out[218]
    DIRECTION OUTPUT ;
    USE SIGNAL ;
    SHAPE ABUTMENT ;
    PORT
      LAYER met2 ;
      RECT 1092.890 0.000 1093.030 0.420 ;
    END
  END r0_rd_out[218]
  PIN r0_rd_out[219]
    DIRECTION OUTPUT ;
    USE SIGNAL ;
    SHAPE ABUTMENT ;
    PORT
      LAYER met2 ;
      RECT 1095.190 0.000 1095.330 0.420 ;
    END
  END r0_rd_out[219]
  PIN r0_rd_out[220]
    DIRECTION OUTPUT ;
    USE SIGNAL ;
    SHAPE ABUTMENT ;
    PORT
      LAYER met2 ;
      RECT 1097.490 0.000 1097.630 0.420 ;
    END
  END r0_rd_out[220]
  PIN r0_rd_out[221]
    DIRECTION OUTPUT ;
    USE SIGNAL ;
    SHAPE ABUTMENT ;
    PORT
      LAYER met2 ;
      RECT 1099.790 0.000 1099.930 0.420 ;
    END
  END r0_rd_out[221]
  PIN r0_rd_out[222]
    DIRECTION OUTPUT ;
    USE SIGNAL ;
    SHAPE ABUTMENT ;
    PORT
      LAYER met2 ;
      RECT 1102.090 0.000 1102.230 0.420 ;
    END
  END r0_rd_out[222]
  PIN r0_rd_out[223]
    DIRECTION OUTPUT ;
    USE SIGNAL ;
    SHAPE ABUTMENT ;
    PORT
      LAYER met2 ;
      RECT 1104.390 0.000 1104.530 0.420 ;
    END
  END r0_rd_out[223]
  PIN r0_rd_out[224]
    DIRECTION OUTPUT ;
    USE SIGNAL ;
    SHAPE ABUTMENT ;
    PORT
      LAYER met2 ;
      RECT 1106.690 0.000 1106.830 0.420 ;
    END
  END r0_rd_out[224]
  PIN r0_rd_out[225]
    DIRECTION OUTPUT ;
    USE SIGNAL ;
    SHAPE ABUTMENT ;
    PORT
      LAYER met2 ;
      RECT 1108.990 0.000 1109.130 0.420 ;
    END
  END r0_rd_out[225]
  PIN r0_rd_out[226]
    DIRECTION OUTPUT ;
    USE SIGNAL ;
    SHAPE ABUTMENT ;
    PORT
      LAYER met2 ;
      RECT 1111.290 0.000 1111.430 0.420 ;
    END
  END r0_rd_out[226]
  PIN r0_rd_out[227]
    DIRECTION OUTPUT ;
    USE SIGNAL ;
    SHAPE ABUTMENT ;
    PORT
      LAYER met2 ;
      RECT 1113.590 0.000 1113.730 0.420 ;
    END
  END r0_rd_out[227]
  PIN r0_rd_out[228]
    DIRECTION OUTPUT ;
    USE SIGNAL ;
    SHAPE ABUTMENT ;
    PORT
      LAYER met2 ;
      RECT 1115.890 0.000 1116.030 0.420 ;
    END
  END r0_rd_out[228]
  PIN r0_rd_out[229]
    DIRECTION OUTPUT ;
    USE SIGNAL ;
    SHAPE ABUTMENT ;
    PORT
      LAYER met2 ;
      RECT 1118.190 0.000 1118.330 0.420 ;
    END
  END r0_rd_out[229]
  PIN r0_rd_out[230]
    DIRECTION OUTPUT ;
    USE SIGNAL ;
    SHAPE ABUTMENT ;
    PORT
      LAYER met2 ;
      RECT 1120.490 0.000 1120.630 0.420 ;
    END
  END r0_rd_out[230]
  PIN r0_rd_out[231]
    DIRECTION OUTPUT ;
    USE SIGNAL ;
    SHAPE ABUTMENT ;
    PORT
      LAYER met2 ;
      RECT 1122.790 0.000 1122.930 0.420 ;
    END
  END r0_rd_out[231]
  PIN r0_rd_out[232]
    DIRECTION OUTPUT ;
    USE SIGNAL ;
    SHAPE ABUTMENT ;
    PORT
      LAYER met2 ;
      RECT 1125.090 0.000 1125.230 0.420 ;
    END
  END r0_rd_out[232]
  PIN r0_rd_out[233]
    DIRECTION OUTPUT ;
    USE SIGNAL ;
    SHAPE ABUTMENT ;
    PORT
      LAYER met2 ;
      RECT 1127.390 0.000 1127.530 0.420 ;
    END
  END r0_rd_out[233]
  PIN r0_rd_out[234]
    DIRECTION OUTPUT ;
    USE SIGNAL ;
    SHAPE ABUTMENT ;
    PORT
      LAYER met2 ;
      RECT 1129.690 0.000 1129.830 0.420 ;
    END
  END r0_rd_out[234]
  PIN r0_rd_out[235]
    DIRECTION OUTPUT ;
    USE SIGNAL ;
    SHAPE ABUTMENT ;
    PORT
      LAYER met2 ;
      RECT 1131.990 0.000 1132.130 0.420 ;
    END
  END r0_rd_out[235]
  PIN r0_rd_out[236]
    DIRECTION OUTPUT ;
    USE SIGNAL ;
    SHAPE ABUTMENT ;
    PORT
      LAYER met2 ;
      RECT 1134.290 0.000 1134.430 0.420 ;
    END
  END r0_rd_out[236]
  PIN r0_rd_out[237]
    DIRECTION OUTPUT ;
    USE SIGNAL ;
    SHAPE ABUTMENT ;
    PORT
      LAYER met2 ;
      RECT 1136.590 0.000 1136.730 0.420 ;
    END
  END r0_rd_out[237]
  PIN r0_rd_out[238]
    DIRECTION OUTPUT ;
    USE SIGNAL ;
    SHAPE ABUTMENT ;
    PORT
      LAYER met2 ;
      RECT 1138.890 0.000 1139.030 0.420 ;
    END
  END r0_rd_out[238]
  PIN r0_rd_out[239]
    DIRECTION OUTPUT ;
    USE SIGNAL ;
    SHAPE ABUTMENT ;
    PORT
      LAYER met2 ;
      RECT 1141.190 0.000 1141.330 0.420 ;
    END
  END r0_rd_out[239]
  PIN r0_rd_out[240]
    DIRECTION OUTPUT ;
    USE SIGNAL ;
    SHAPE ABUTMENT ;
    PORT
      LAYER met2 ;
      RECT 1143.490 0.000 1143.630 0.420 ;
    END
  END r0_rd_out[240]
  PIN r0_rd_out[241]
    DIRECTION OUTPUT ;
    USE SIGNAL ;
    SHAPE ABUTMENT ;
    PORT
      LAYER met2 ;
      RECT 1145.790 0.000 1145.930 0.420 ;
    END
  END r0_rd_out[241]
  PIN r0_rd_out[242]
    DIRECTION OUTPUT ;
    USE SIGNAL ;
    SHAPE ABUTMENT ;
    PORT
      LAYER met2 ;
      RECT 1148.090 0.000 1148.230 0.420 ;
    END
  END r0_rd_out[242]
  PIN r0_rd_out[243]
    DIRECTION OUTPUT ;
    USE SIGNAL ;
    SHAPE ABUTMENT ;
    PORT
      LAYER met2 ;
      RECT 1150.390 0.000 1150.530 0.420 ;
    END
  END r0_rd_out[243]
  PIN r0_rd_out[244]
    DIRECTION OUTPUT ;
    USE SIGNAL ;
    SHAPE ABUTMENT ;
    PORT
      LAYER met2 ;
      RECT 1152.690 0.000 1152.830 0.420 ;
    END
  END r0_rd_out[244]
  PIN r0_rd_out[245]
    DIRECTION OUTPUT ;
    USE SIGNAL ;
    SHAPE ABUTMENT ;
    PORT
      LAYER met2 ;
      RECT 1154.990 0.000 1155.130 0.420 ;
    END
  END r0_rd_out[245]
  PIN r0_rd_out[246]
    DIRECTION OUTPUT ;
    USE SIGNAL ;
    SHAPE ABUTMENT ;
    PORT
      LAYER met2 ;
      RECT 1157.290 0.000 1157.430 0.420 ;
    END
  END r0_rd_out[246]
  PIN r0_rd_out[247]
    DIRECTION OUTPUT ;
    USE SIGNAL ;
    SHAPE ABUTMENT ;
    PORT
      LAYER met2 ;
      RECT 1159.590 0.000 1159.730 0.420 ;
    END
  END r0_rd_out[247]
  PIN r0_rd_out[248]
    DIRECTION OUTPUT ;
    USE SIGNAL ;
    SHAPE ABUTMENT ;
    PORT
      LAYER met2 ;
      RECT 1161.890 0.000 1162.030 0.420 ;
    END
  END r0_rd_out[248]
  PIN r0_rd_out[249]
    DIRECTION OUTPUT ;
    USE SIGNAL ;
    SHAPE ABUTMENT ;
    PORT
      LAYER met2 ;
      RECT 1164.190 0.000 1164.330 0.420 ;
    END
  END r0_rd_out[249]
  PIN r0_rd_out[250]
    DIRECTION OUTPUT ;
    USE SIGNAL ;
    SHAPE ABUTMENT ;
    PORT
      LAYER met2 ;
      RECT 1166.490 0.000 1166.630 0.420 ;
    END
  END r0_rd_out[250]
  PIN r0_rd_out[251]
    DIRECTION OUTPUT ;
    USE SIGNAL ;
    SHAPE ABUTMENT ;
    PORT
      LAYER met2 ;
      RECT 1168.790 0.000 1168.930 0.420 ;
    END
  END r0_rd_out[251]
  PIN r0_rd_out[252]
    DIRECTION OUTPUT ;
    USE SIGNAL ;
    SHAPE ABUTMENT ;
    PORT
      LAYER met2 ;
      RECT 1171.090 0.000 1171.230 0.420 ;
    END
  END r0_rd_out[252]
  PIN r0_rd_out[253]
    DIRECTION OUTPUT ;
    USE SIGNAL ;
    SHAPE ABUTMENT ;
    PORT
      LAYER met2 ;
      RECT 1173.390 0.000 1173.530 0.420 ;
    END
  END r0_rd_out[253]
  PIN r0_rd_out[254]
    DIRECTION OUTPUT ;
    USE SIGNAL ;
    SHAPE ABUTMENT ;
    PORT
      LAYER met2 ;
      RECT 1175.690 0.000 1175.830 0.420 ;
    END
  END r0_rd_out[254]
  PIN r0_rd_out[255]
    DIRECTION OUTPUT ;
    USE SIGNAL ;
    SHAPE ABUTMENT ;
    PORT
      LAYER met2 ;
      RECT 1177.990 0.000 1178.130 0.420 ;
    END
  END r0_rd_out[255]
  PIN r0_rd_out[256]
    DIRECTION OUTPUT ;
    USE SIGNAL ;
    SHAPE ABUTMENT ;
    PORT
      LAYER met2 ;
      RECT 2.690 1569.020 2.830 1569.440 ;
    END
  END r0_rd_out[256]
  PIN r0_rd_out[257]
    DIRECTION OUTPUT ;
    USE SIGNAL ;
    SHAPE ABUTMENT ;
    PORT
      LAYER met2 ;
      RECT 7.290 1569.020 7.430 1569.440 ;
    END
  END r0_rd_out[257]
  PIN r0_rd_out[258]
    DIRECTION OUTPUT ;
    USE SIGNAL ;
    SHAPE ABUTMENT ;
    PORT
      LAYER met2 ;
      RECT 11.890 1569.020 12.030 1569.440 ;
    END
  END r0_rd_out[258]
  PIN r0_rd_out[259]
    DIRECTION OUTPUT ;
    USE SIGNAL ;
    SHAPE ABUTMENT ;
    PORT
      LAYER met2 ;
      RECT 16.490 1569.020 16.630 1569.440 ;
    END
  END r0_rd_out[259]
  PIN r0_rd_out[260]
    DIRECTION OUTPUT ;
    USE SIGNAL ;
    SHAPE ABUTMENT ;
    PORT
      LAYER met2 ;
      RECT 21.090 1569.020 21.230 1569.440 ;
    END
  END r0_rd_out[260]
  PIN r0_rd_out[261]
    DIRECTION OUTPUT ;
    USE SIGNAL ;
    SHAPE ABUTMENT ;
    PORT
      LAYER met2 ;
      RECT 25.690 1569.020 25.830 1569.440 ;
    END
  END r0_rd_out[261]
  PIN r0_rd_out[262]
    DIRECTION OUTPUT ;
    USE SIGNAL ;
    SHAPE ABUTMENT ;
    PORT
      LAYER met2 ;
      RECT 30.290 1569.020 30.430 1569.440 ;
    END
  END r0_rd_out[262]
  PIN r0_rd_out[263]
    DIRECTION OUTPUT ;
    USE SIGNAL ;
    SHAPE ABUTMENT ;
    PORT
      LAYER met2 ;
      RECT 34.890 1569.020 35.030 1569.440 ;
    END
  END r0_rd_out[263]
  PIN r0_rd_out[264]
    DIRECTION OUTPUT ;
    USE SIGNAL ;
    SHAPE ABUTMENT ;
    PORT
      LAYER met2 ;
      RECT 39.490 1569.020 39.630 1569.440 ;
    END
  END r0_rd_out[264]
  PIN r0_rd_out[265]
    DIRECTION OUTPUT ;
    USE SIGNAL ;
    SHAPE ABUTMENT ;
    PORT
      LAYER met2 ;
      RECT 44.090 1569.020 44.230 1569.440 ;
    END
  END r0_rd_out[265]
  PIN r0_rd_out[266]
    DIRECTION OUTPUT ;
    USE SIGNAL ;
    SHAPE ABUTMENT ;
    PORT
      LAYER met2 ;
      RECT 48.690 1569.020 48.830 1569.440 ;
    END
  END r0_rd_out[266]
  PIN r0_rd_out[267]
    DIRECTION OUTPUT ;
    USE SIGNAL ;
    SHAPE ABUTMENT ;
    PORT
      LAYER met2 ;
      RECT 53.290 1569.020 53.430 1569.440 ;
    END
  END r0_rd_out[267]
  PIN r0_rd_out[268]
    DIRECTION OUTPUT ;
    USE SIGNAL ;
    SHAPE ABUTMENT ;
    PORT
      LAYER met2 ;
      RECT 57.890 1569.020 58.030 1569.440 ;
    END
  END r0_rd_out[268]
  PIN r0_rd_out[269]
    DIRECTION OUTPUT ;
    USE SIGNAL ;
    SHAPE ABUTMENT ;
    PORT
      LAYER met2 ;
      RECT 62.490 1569.020 62.630 1569.440 ;
    END
  END r0_rd_out[269]
  PIN r0_rd_out[270]
    DIRECTION OUTPUT ;
    USE SIGNAL ;
    SHAPE ABUTMENT ;
    PORT
      LAYER met2 ;
      RECT 67.090 1569.020 67.230 1569.440 ;
    END
  END r0_rd_out[270]
  PIN r0_rd_out[271]
    DIRECTION OUTPUT ;
    USE SIGNAL ;
    SHAPE ABUTMENT ;
    PORT
      LAYER met2 ;
      RECT 71.690 1569.020 71.830 1569.440 ;
    END
  END r0_rd_out[271]
  PIN r0_rd_out[272]
    DIRECTION OUTPUT ;
    USE SIGNAL ;
    SHAPE ABUTMENT ;
    PORT
      LAYER met2 ;
      RECT 76.290 1569.020 76.430 1569.440 ;
    END
  END r0_rd_out[272]
  PIN r0_rd_out[273]
    DIRECTION OUTPUT ;
    USE SIGNAL ;
    SHAPE ABUTMENT ;
    PORT
      LAYER met2 ;
      RECT 80.890 1569.020 81.030 1569.440 ;
    END
  END r0_rd_out[273]
  PIN r0_rd_out[274]
    DIRECTION OUTPUT ;
    USE SIGNAL ;
    SHAPE ABUTMENT ;
    PORT
      LAYER met2 ;
      RECT 85.490 1569.020 85.630 1569.440 ;
    END
  END r0_rd_out[274]
  PIN r0_rd_out[275]
    DIRECTION OUTPUT ;
    USE SIGNAL ;
    SHAPE ABUTMENT ;
    PORT
      LAYER met2 ;
      RECT 90.090 1569.020 90.230 1569.440 ;
    END
  END r0_rd_out[275]
  PIN r0_rd_out[276]
    DIRECTION OUTPUT ;
    USE SIGNAL ;
    SHAPE ABUTMENT ;
    PORT
      LAYER met2 ;
      RECT 94.690 1569.020 94.830 1569.440 ;
    END
  END r0_rd_out[276]
  PIN r0_rd_out[277]
    DIRECTION OUTPUT ;
    USE SIGNAL ;
    SHAPE ABUTMENT ;
    PORT
      LAYER met2 ;
      RECT 99.290 1569.020 99.430 1569.440 ;
    END
  END r0_rd_out[277]
  PIN r0_rd_out[278]
    DIRECTION OUTPUT ;
    USE SIGNAL ;
    SHAPE ABUTMENT ;
    PORT
      LAYER met2 ;
      RECT 103.890 1569.020 104.030 1569.440 ;
    END
  END r0_rd_out[278]
  PIN r0_rd_out[279]
    DIRECTION OUTPUT ;
    USE SIGNAL ;
    SHAPE ABUTMENT ;
    PORT
      LAYER met2 ;
      RECT 108.490 1569.020 108.630 1569.440 ;
    END
  END r0_rd_out[279]
  PIN r0_rd_out[280]
    DIRECTION OUTPUT ;
    USE SIGNAL ;
    SHAPE ABUTMENT ;
    PORT
      LAYER met2 ;
      RECT 113.090 1569.020 113.230 1569.440 ;
    END
  END r0_rd_out[280]
  PIN r0_rd_out[281]
    DIRECTION OUTPUT ;
    USE SIGNAL ;
    SHAPE ABUTMENT ;
    PORT
      LAYER met2 ;
      RECT 117.690 1569.020 117.830 1569.440 ;
    END
  END r0_rd_out[281]
  PIN r0_rd_out[282]
    DIRECTION OUTPUT ;
    USE SIGNAL ;
    SHAPE ABUTMENT ;
    PORT
      LAYER met2 ;
      RECT 122.290 1569.020 122.430 1569.440 ;
    END
  END r0_rd_out[282]
  PIN r0_rd_out[283]
    DIRECTION OUTPUT ;
    USE SIGNAL ;
    SHAPE ABUTMENT ;
    PORT
      LAYER met2 ;
      RECT 126.890 1569.020 127.030 1569.440 ;
    END
  END r0_rd_out[283]
  PIN r0_rd_out[284]
    DIRECTION OUTPUT ;
    USE SIGNAL ;
    SHAPE ABUTMENT ;
    PORT
      LAYER met2 ;
      RECT 131.490 1569.020 131.630 1569.440 ;
    END
  END r0_rd_out[284]
  PIN r0_rd_out[285]
    DIRECTION OUTPUT ;
    USE SIGNAL ;
    SHAPE ABUTMENT ;
    PORT
      LAYER met2 ;
      RECT 136.090 1569.020 136.230 1569.440 ;
    END
  END r0_rd_out[285]
  PIN r0_rd_out[286]
    DIRECTION OUTPUT ;
    USE SIGNAL ;
    SHAPE ABUTMENT ;
    PORT
      LAYER met2 ;
      RECT 140.690 1569.020 140.830 1569.440 ;
    END
  END r0_rd_out[286]
  PIN r0_rd_out[287]
    DIRECTION OUTPUT ;
    USE SIGNAL ;
    SHAPE ABUTMENT ;
    PORT
      LAYER met2 ;
      RECT 145.290 1569.020 145.430 1569.440 ;
    END
  END r0_rd_out[287]
  PIN r0_rd_out[288]
    DIRECTION OUTPUT ;
    USE SIGNAL ;
    SHAPE ABUTMENT ;
    PORT
      LAYER met2 ;
      RECT 149.890 1569.020 150.030 1569.440 ;
    END
  END r0_rd_out[288]
  PIN r0_rd_out[289]
    DIRECTION OUTPUT ;
    USE SIGNAL ;
    SHAPE ABUTMENT ;
    PORT
      LAYER met2 ;
      RECT 154.490 1569.020 154.630 1569.440 ;
    END
  END r0_rd_out[289]
  PIN r0_rd_out[290]
    DIRECTION OUTPUT ;
    USE SIGNAL ;
    SHAPE ABUTMENT ;
    PORT
      LAYER met2 ;
      RECT 159.090 1569.020 159.230 1569.440 ;
    END
  END r0_rd_out[290]
  PIN r0_rd_out[291]
    DIRECTION OUTPUT ;
    USE SIGNAL ;
    SHAPE ABUTMENT ;
    PORT
      LAYER met2 ;
      RECT 163.690 1569.020 163.830 1569.440 ;
    END
  END r0_rd_out[291]
  PIN r0_rd_out[292]
    DIRECTION OUTPUT ;
    USE SIGNAL ;
    SHAPE ABUTMENT ;
    PORT
      LAYER met2 ;
      RECT 168.290 1569.020 168.430 1569.440 ;
    END
  END r0_rd_out[292]
  PIN r0_rd_out[293]
    DIRECTION OUTPUT ;
    USE SIGNAL ;
    SHAPE ABUTMENT ;
    PORT
      LAYER met2 ;
      RECT 172.890 1569.020 173.030 1569.440 ;
    END
  END r0_rd_out[293]
  PIN r0_rd_out[294]
    DIRECTION OUTPUT ;
    USE SIGNAL ;
    SHAPE ABUTMENT ;
    PORT
      LAYER met2 ;
      RECT 177.490 1569.020 177.630 1569.440 ;
    END
  END r0_rd_out[294]
  PIN r0_rd_out[295]
    DIRECTION OUTPUT ;
    USE SIGNAL ;
    SHAPE ABUTMENT ;
    PORT
      LAYER met2 ;
      RECT 182.090 1569.020 182.230 1569.440 ;
    END
  END r0_rd_out[295]
  PIN r0_rd_out[296]
    DIRECTION OUTPUT ;
    USE SIGNAL ;
    SHAPE ABUTMENT ;
    PORT
      LAYER met2 ;
      RECT 186.690 1569.020 186.830 1569.440 ;
    END
  END r0_rd_out[296]
  PIN r0_rd_out[297]
    DIRECTION OUTPUT ;
    USE SIGNAL ;
    SHAPE ABUTMENT ;
    PORT
      LAYER met2 ;
      RECT 191.290 1569.020 191.430 1569.440 ;
    END
  END r0_rd_out[297]
  PIN r0_rd_out[298]
    DIRECTION OUTPUT ;
    USE SIGNAL ;
    SHAPE ABUTMENT ;
    PORT
      LAYER met2 ;
      RECT 195.890 1569.020 196.030 1569.440 ;
    END
  END r0_rd_out[298]
  PIN r0_rd_out[299]
    DIRECTION OUTPUT ;
    USE SIGNAL ;
    SHAPE ABUTMENT ;
    PORT
      LAYER met2 ;
      RECT 200.490 1569.020 200.630 1569.440 ;
    END
  END r0_rd_out[299]
  PIN r0_rd_out[300]
    DIRECTION OUTPUT ;
    USE SIGNAL ;
    SHAPE ABUTMENT ;
    PORT
      LAYER met2 ;
      RECT 205.090 1569.020 205.230 1569.440 ;
    END
  END r0_rd_out[300]
  PIN r0_rd_out[301]
    DIRECTION OUTPUT ;
    USE SIGNAL ;
    SHAPE ABUTMENT ;
    PORT
      LAYER met2 ;
      RECT 209.690 1569.020 209.830 1569.440 ;
    END
  END r0_rd_out[301]
  PIN r0_rd_out[302]
    DIRECTION OUTPUT ;
    USE SIGNAL ;
    SHAPE ABUTMENT ;
    PORT
      LAYER met2 ;
      RECT 214.290 1569.020 214.430 1569.440 ;
    END
  END r0_rd_out[302]
  PIN r0_rd_out[303]
    DIRECTION OUTPUT ;
    USE SIGNAL ;
    SHAPE ABUTMENT ;
    PORT
      LAYER met2 ;
      RECT 218.890 1569.020 219.030 1569.440 ;
    END
  END r0_rd_out[303]
  PIN r0_rd_out[304]
    DIRECTION OUTPUT ;
    USE SIGNAL ;
    SHAPE ABUTMENT ;
    PORT
      LAYER met2 ;
      RECT 223.490 1569.020 223.630 1569.440 ;
    END
  END r0_rd_out[304]
  PIN r0_rd_out[305]
    DIRECTION OUTPUT ;
    USE SIGNAL ;
    SHAPE ABUTMENT ;
    PORT
      LAYER met2 ;
      RECT 228.090 1569.020 228.230 1569.440 ;
    END
  END r0_rd_out[305]
  PIN r0_rd_out[306]
    DIRECTION OUTPUT ;
    USE SIGNAL ;
    SHAPE ABUTMENT ;
    PORT
      LAYER met2 ;
      RECT 232.690 1569.020 232.830 1569.440 ;
    END
  END r0_rd_out[306]
  PIN r0_rd_out[307]
    DIRECTION OUTPUT ;
    USE SIGNAL ;
    SHAPE ABUTMENT ;
    PORT
      LAYER met2 ;
      RECT 237.290 1569.020 237.430 1569.440 ;
    END
  END r0_rd_out[307]
  PIN r0_rd_out[308]
    DIRECTION OUTPUT ;
    USE SIGNAL ;
    SHAPE ABUTMENT ;
    PORT
      LAYER met2 ;
      RECT 241.890 1569.020 242.030 1569.440 ;
    END
  END r0_rd_out[308]
  PIN r0_rd_out[309]
    DIRECTION OUTPUT ;
    USE SIGNAL ;
    SHAPE ABUTMENT ;
    PORT
      LAYER met2 ;
      RECT 246.490 1569.020 246.630 1569.440 ;
    END
  END r0_rd_out[309]
  PIN r0_rd_out[310]
    DIRECTION OUTPUT ;
    USE SIGNAL ;
    SHAPE ABUTMENT ;
    PORT
      LAYER met2 ;
      RECT 251.090 1569.020 251.230 1569.440 ;
    END
  END r0_rd_out[310]
  PIN r0_rd_out[311]
    DIRECTION OUTPUT ;
    USE SIGNAL ;
    SHAPE ABUTMENT ;
    PORT
      LAYER met2 ;
      RECT 255.690 1569.020 255.830 1569.440 ;
    END
  END r0_rd_out[311]
  PIN r0_rd_out[312]
    DIRECTION OUTPUT ;
    USE SIGNAL ;
    SHAPE ABUTMENT ;
    PORT
      LAYER met2 ;
      RECT 260.290 1569.020 260.430 1569.440 ;
    END
  END r0_rd_out[312]
  PIN r0_rd_out[313]
    DIRECTION OUTPUT ;
    USE SIGNAL ;
    SHAPE ABUTMENT ;
    PORT
      LAYER met2 ;
      RECT 264.890 1569.020 265.030 1569.440 ;
    END
  END r0_rd_out[313]
  PIN r0_rd_out[314]
    DIRECTION OUTPUT ;
    USE SIGNAL ;
    SHAPE ABUTMENT ;
    PORT
      LAYER met2 ;
      RECT 269.490 1569.020 269.630 1569.440 ;
    END
  END r0_rd_out[314]
  PIN r0_rd_out[315]
    DIRECTION OUTPUT ;
    USE SIGNAL ;
    SHAPE ABUTMENT ;
    PORT
      LAYER met2 ;
      RECT 274.090 1569.020 274.230 1569.440 ;
    END
  END r0_rd_out[315]
  PIN r0_rd_out[316]
    DIRECTION OUTPUT ;
    USE SIGNAL ;
    SHAPE ABUTMENT ;
    PORT
      LAYER met2 ;
      RECT 278.690 1569.020 278.830 1569.440 ;
    END
  END r0_rd_out[316]
  PIN r0_rd_out[317]
    DIRECTION OUTPUT ;
    USE SIGNAL ;
    SHAPE ABUTMENT ;
    PORT
      LAYER met2 ;
      RECT 283.290 1569.020 283.430 1569.440 ;
    END
  END r0_rd_out[317]
  PIN r0_rd_out[318]
    DIRECTION OUTPUT ;
    USE SIGNAL ;
    SHAPE ABUTMENT ;
    PORT
      LAYER met2 ;
      RECT 287.890 1569.020 288.030 1569.440 ;
    END
  END r0_rd_out[318]
  PIN r0_rd_out[319]
    DIRECTION OUTPUT ;
    USE SIGNAL ;
    SHAPE ABUTMENT ;
    PORT
      LAYER met2 ;
      RECT 292.490 1569.020 292.630 1569.440 ;
    END
  END r0_rd_out[319]
  PIN r0_rd_out[320]
    DIRECTION OUTPUT ;
    USE SIGNAL ;
    SHAPE ABUTMENT ;
    PORT
      LAYER met2 ;
      RECT 297.090 1569.020 297.230 1569.440 ;
    END
  END r0_rd_out[320]
  PIN r0_rd_out[321]
    DIRECTION OUTPUT ;
    USE SIGNAL ;
    SHAPE ABUTMENT ;
    PORT
      LAYER met2 ;
      RECT 301.690 1569.020 301.830 1569.440 ;
    END
  END r0_rd_out[321]
  PIN r0_rd_out[322]
    DIRECTION OUTPUT ;
    USE SIGNAL ;
    SHAPE ABUTMENT ;
    PORT
      LAYER met2 ;
      RECT 306.290 1569.020 306.430 1569.440 ;
    END
  END r0_rd_out[322]
  PIN r0_rd_out[323]
    DIRECTION OUTPUT ;
    USE SIGNAL ;
    SHAPE ABUTMENT ;
    PORT
      LAYER met2 ;
      RECT 310.890 1569.020 311.030 1569.440 ;
    END
  END r0_rd_out[323]
  PIN r0_rd_out[324]
    DIRECTION OUTPUT ;
    USE SIGNAL ;
    SHAPE ABUTMENT ;
    PORT
      LAYER met2 ;
      RECT 315.490 1569.020 315.630 1569.440 ;
    END
  END r0_rd_out[324]
  PIN r0_rd_out[325]
    DIRECTION OUTPUT ;
    USE SIGNAL ;
    SHAPE ABUTMENT ;
    PORT
      LAYER met2 ;
      RECT 320.090 1569.020 320.230 1569.440 ;
    END
  END r0_rd_out[325]
  PIN r0_rd_out[326]
    DIRECTION OUTPUT ;
    USE SIGNAL ;
    SHAPE ABUTMENT ;
    PORT
      LAYER met2 ;
      RECT 324.690 1569.020 324.830 1569.440 ;
    END
  END r0_rd_out[326]
  PIN r0_rd_out[327]
    DIRECTION OUTPUT ;
    USE SIGNAL ;
    SHAPE ABUTMENT ;
    PORT
      LAYER met2 ;
      RECT 329.290 1569.020 329.430 1569.440 ;
    END
  END r0_rd_out[327]
  PIN r0_rd_out[328]
    DIRECTION OUTPUT ;
    USE SIGNAL ;
    SHAPE ABUTMENT ;
    PORT
      LAYER met2 ;
      RECT 333.890 1569.020 334.030 1569.440 ;
    END
  END r0_rd_out[328]
  PIN r0_rd_out[329]
    DIRECTION OUTPUT ;
    USE SIGNAL ;
    SHAPE ABUTMENT ;
    PORT
      LAYER met2 ;
      RECT 338.490 1569.020 338.630 1569.440 ;
    END
  END r0_rd_out[329]
  PIN r0_rd_out[330]
    DIRECTION OUTPUT ;
    USE SIGNAL ;
    SHAPE ABUTMENT ;
    PORT
      LAYER met2 ;
      RECT 343.090 1569.020 343.230 1569.440 ;
    END
  END r0_rd_out[330]
  PIN r0_rd_out[331]
    DIRECTION OUTPUT ;
    USE SIGNAL ;
    SHAPE ABUTMENT ;
    PORT
      LAYER met2 ;
      RECT 347.690 1569.020 347.830 1569.440 ;
    END
  END r0_rd_out[331]
  PIN r0_rd_out[332]
    DIRECTION OUTPUT ;
    USE SIGNAL ;
    SHAPE ABUTMENT ;
    PORT
      LAYER met2 ;
      RECT 352.290 1569.020 352.430 1569.440 ;
    END
  END r0_rd_out[332]
  PIN r0_rd_out[333]
    DIRECTION OUTPUT ;
    USE SIGNAL ;
    SHAPE ABUTMENT ;
    PORT
      LAYER met2 ;
      RECT 356.890 1569.020 357.030 1569.440 ;
    END
  END r0_rd_out[333]
  PIN r0_rd_out[334]
    DIRECTION OUTPUT ;
    USE SIGNAL ;
    SHAPE ABUTMENT ;
    PORT
      LAYER met2 ;
      RECT 361.490 1569.020 361.630 1569.440 ;
    END
  END r0_rd_out[334]
  PIN r0_rd_out[335]
    DIRECTION OUTPUT ;
    USE SIGNAL ;
    SHAPE ABUTMENT ;
    PORT
      LAYER met2 ;
      RECT 366.090 1569.020 366.230 1569.440 ;
    END
  END r0_rd_out[335]
  PIN r0_rd_out[336]
    DIRECTION OUTPUT ;
    USE SIGNAL ;
    SHAPE ABUTMENT ;
    PORT
      LAYER met2 ;
      RECT 370.690 1569.020 370.830 1569.440 ;
    END
  END r0_rd_out[336]
  PIN r0_rd_out[337]
    DIRECTION OUTPUT ;
    USE SIGNAL ;
    SHAPE ABUTMENT ;
    PORT
      LAYER met2 ;
      RECT 375.290 1569.020 375.430 1569.440 ;
    END
  END r0_rd_out[337]
  PIN r0_rd_out[338]
    DIRECTION OUTPUT ;
    USE SIGNAL ;
    SHAPE ABUTMENT ;
    PORT
      LAYER met2 ;
      RECT 379.890 1569.020 380.030 1569.440 ;
    END
  END r0_rd_out[338]
  PIN r0_rd_out[339]
    DIRECTION OUTPUT ;
    USE SIGNAL ;
    SHAPE ABUTMENT ;
    PORT
      LAYER met2 ;
      RECT 384.490 1569.020 384.630 1569.440 ;
    END
  END r0_rd_out[339]
  PIN r0_rd_out[340]
    DIRECTION OUTPUT ;
    USE SIGNAL ;
    SHAPE ABUTMENT ;
    PORT
      LAYER met2 ;
      RECT 389.090 1569.020 389.230 1569.440 ;
    END
  END r0_rd_out[340]
  PIN r0_rd_out[341]
    DIRECTION OUTPUT ;
    USE SIGNAL ;
    SHAPE ABUTMENT ;
    PORT
      LAYER met2 ;
      RECT 393.690 1569.020 393.830 1569.440 ;
    END
  END r0_rd_out[341]
  PIN r0_rd_out[342]
    DIRECTION OUTPUT ;
    USE SIGNAL ;
    SHAPE ABUTMENT ;
    PORT
      LAYER met2 ;
      RECT 398.290 1569.020 398.430 1569.440 ;
    END
  END r0_rd_out[342]
  PIN r0_rd_out[343]
    DIRECTION OUTPUT ;
    USE SIGNAL ;
    SHAPE ABUTMENT ;
    PORT
      LAYER met2 ;
      RECT 402.890 1569.020 403.030 1569.440 ;
    END
  END r0_rd_out[343]
  PIN r0_rd_out[344]
    DIRECTION OUTPUT ;
    USE SIGNAL ;
    SHAPE ABUTMENT ;
    PORT
      LAYER met2 ;
      RECT 407.490 1569.020 407.630 1569.440 ;
    END
  END r0_rd_out[344]
  PIN r0_rd_out[345]
    DIRECTION OUTPUT ;
    USE SIGNAL ;
    SHAPE ABUTMENT ;
    PORT
      LAYER met2 ;
      RECT 412.090 1569.020 412.230 1569.440 ;
    END
  END r0_rd_out[345]
  PIN r0_rd_out[346]
    DIRECTION OUTPUT ;
    USE SIGNAL ;
    SHAPE ABUTMENT ;
    PORT
      LAYER met2 ;
      RECT 416.690 1569.020 416.830 1569.440 ;
    END
  END r0_rd_out[346]
  PIN r0_rd_out[347]
    DIRECTION OUTPUT ;
    USE SIGNAL ;
    SHAPE ABUTMENT ;
    PORT
      LAYER met2 ;
      RECT 421.290 1569.020 421.430 1569.440 ;
    END
  END r0_rd_out[347]
  PIN r0_rd_out[348]
    DIRECTION OUTPUT ;
    USE SIGNAL ;
    SHAPE ABUTMENT ;
    PORT
      LAYER met2 ;
      RECT 425.890 1569.020 426.030 1569.440 ;
    END
  END r0_rd_out[348]
  PIN r0_rd_out[349]
    DIRECTION OUTPUT ;
    USE SIGNAL ;
    SHAPE ABUTMENT ;
    PORT
      LAYER met2 ;
      RECT 430.490 1569.020 430.630 1569.440 ;
    END
  END r0_rd_out[349]
  PIN r0_rd_out[350]
    DIRECTION OUTPUT ;
    USE SIGNAL ;
    SHAPE ABUTMENT ;
    PORT
      LAYER met2 ;
      RECT 435.090 1569.020 435.230 1569.440 ;
    END
  END r0_rd_out[350]
  PIN r0_rd_out[351]
    DIRECTION OUTPUT ;
    USE SIGNAL ;
    SHAPE ABUTMENT ;
    PORT
      LAYER met2 ;
      RECT 439.690 1569.020 439.830 1569.440 ;
    END
  END r0_rd_out[351]
  PIN r0_rd_out[352]
    DIRECTION OUTPUT ;
    USE SIGNAL ;
    SHAPE ABUTMENT ;
    PORT
      LAYER met2 ;
      RECT 444.290 1569.020 444.430 1569.440 ;
    END
  END r0_rd_out[352]
  PIN r0_rd_out[353]
    DIRECTION OUTPUT ;
    USE SIGNAL ;
    SHAPE ABUTMENT ;
    PORT
      LAYER met2 ;
      RECT 448.890 1569.020 449.030 1569.440 ;
    END
  END r0_rd_out[353]
  PIN r0_rd_out[354]
    DIRECTION OUTPUT ;
    USE SIGNAL ;
    SHAPE ABUTMENT ;
    PORT
      LAYER met2 ;
      RECT 453.490 1569.020 453.630 1569.440 ;
    END
  END r0_rd_out[354]
  PIN r0_rd_out[355]
    DIRECTION OUTPUT ;
    USE SIGNAL ;
    SHAPE ABUTMENT ;
    PORT
      LAYER met2 ;
      RECT 458.090 1569.020 458.230 1569.440 ;
    END
  END r0_rd_out[355]
  PIN r0_rd_out[356]
    DIRECTION OUTPUT ;
    USE SIGNAL ;
    SHAPE ABUTMENT ;
    PORT
      LAYER met2 ;
      RECT 462.690 1569.020 462.830 1569.440 ;
    END
  END r0_rd_out[356]
  PIN r0_rd_out[357]
    DIRECTION OUTPUT ;
    USE SIGNAL ;
    SHAPE ABUTMENT ;
    PORT
      LAYER met2 ;
      RECT 467.290 1569.020 467.430 1569.440 ;
    END
  END r0_rd_out[357]
  PIN r0_rd_out[358]
    DIRECTION OUTPUT ;
    USE SIGNAL ;
    SHAPE ABUTMENT ;
    PORT
      LAYER met2 ;
      RECT 471.890 1569.020 472.030 1569.440 ;
    END
  END r0_rd_out[358]
  PIN r0_rd_out[359]
    DIRECTION OUTPUT ;
    USE SIGNAL ;
    SHAPE ABUTMENT ;
    PORT
      LAYER met2 ;
      RECT 476.490 1569.020 476.630 1569.440 ;
    END
  END r0_rd_out[359]
  PIN r0_rd_out[360]
    DIRECTION OUTPUT ;
    USE SIGNAL ;
    SHAPE ABUTMENT ;
    PORT
      LAYER met2 ;
      RECT 481.090 1569.020 481.230 1569.440 ;
    END
  END r0_rd_out[360]
  PIN r0_rd_out[361]
    DIRECTION OUTPUT ;
    USE SIGNAL ;
    SHAPE ABUTMENT ;
    PORT
      LAYER met2 ;
      RECT 485.690 1569.020 485.830 1569.440 ;
    END
  END r0_rd_out[361]
  PIN r0_rd_out[362]
    DIRECTION OUTPUT ;
    USE SIGNAL ;
    SHAPE ABUTMENT ;
    PORT
      LAYER met2 ;
      RECT 490.290 1569.020 490.430 1569.440 ;
    END
  END r0_rd_out[362]
  PIN r0_rd_out[363]
    DIRECTION OUTPUT ;
    USE SIGNAL ;
    SHAPE ABUTMENT ;
    PORT
      LAYER met2 ;
      RECT 494.890 1569.020 495.030 1569.440 ;
    END
  END r0_rd_out[363]
  PIN r0_rd_out[364]
    DIRECTION OUTPUT ;
    USE SIGNAL ;
    SHAPE ABUTMENT ;
    PORT
      LAYER met2 ;
      RECT 499.490 1569.020 499.630 1569.440 ;
    END
  END r0_rd_out[364]
  PIN r0_rd_out[365]
    DIRECTION OUTPUT ;
    USE SIGNAL ;
    SHAPE ABUTMENT ;
    PORT
      LAYER met2 ;
      RECT 504.090 1569.020 504.230 1569.440 ;
    END
  END r0_rd_out[365]
  PIN r0_rd_out[366]
    DIRECTION OUTPUT ;
    USE SIGNAL ;
    SHAPE ABUTMENT ;
    PORT
      LAYER met2 ;
      RECT 508.690 1569.020 508.830 1569.440 ;
    END
  END r0_rd_out[366]
  PIN r0_rd_out[367]
    DIRECTION OUTPUT ;
    USE SIGNAL ;
    SHAPE ABUTMENT ;
    PORT
      LAYER met2 ;
      RECT 513.290 1569.020 513.430 1569.440 ;
    END
  END r0_rd_out[367]
  PIN r0_rd_out[368]
    DIRECTION OUTPUT ;
    USE SIGNAL ;
    SHAPE ABUTMENT ;
    PORT
      LAYER met2 ;
      RECT 517.890 1569.020 518.030 1569.440 ;
    END
  END r0_rd_out[368]
  PIN r0_rd_out[369]
    DIRECTION OUTPUT ;
    USE SIGNAL ;
    SHAPE ABUTMENT ;
    PORT
      LAYER met2 ;
      RECT 522.490 1569.020 522.630 1569.440 ;
    END
  END r0_rd_out[369]
  PIN r0_rd_out[370]
    DIRECTION OUTPUT ;
    USE SIGNAL ;
    SHAPE ABUTMENT ;
    PORT
      LAYER met2 ;
      RECT 527.090 1569.020 527.230 1569.440 ;
    END
  END r0_rd_out[370]
  PIN r0_rd_out[371]
    DIRECTION OUTPUT ;
    USE SIGNAL ;
    SHAPE ABUTMENT ;
    PORT
      LAYER met2 ;
      RECT 531.690 1569.020 531.830 1569.440 ;
    END
  END r0_rd_out[371]
  PIN r0_rd_out[372]
    DIRECTION OUTPUT ;
    USE SIGNAL ;
    SHAPE ABUTMENT ;
    PORT
      LAYER met2 ;
      RECT 536.290 1569.020 536.430 1569.440 ;
    END
  END r0_rd_out[372]
  PIN r0_rd_out[373]
    DIRECTION OUTPUT ;
    USE SIGNAL ;
    SHAPE ABUTMENT ;
    PORT
      LAYER met2 ;
      RECT 540.890 1569.020 541.030 1569.440 ;
    END
  END r0_rd_out[373]
  PIN r0_rd_out[374]
    DIRECTION OUTPUT ;
    USE SIGNAL ;
    SHAPE ABUTMENT ;
    PORT
      LAYER met2 ;
      RECT 545.490 1569.020 545.630 1569.440 ;
    END
  END r0_rd_out[374]
  PIN r0_rd_out[375]
    DIRECTION OUTPUT ;
    USE SIGNAL ;
    SHAPE ABUTMENT ;
    PORT
      LAYER met2 ;
      RECT 550.090 1569.020 550.230 1569.440 ;
    END
  END r0_rd_out[375]
  PIN r0_rd_out[376]
    DIRECTION OUTPUT ;
    USE SIGNAL ;
    SHAPE ABUTMENT ;
    PORT
      LAYER met2 ;
      RECT 554.690 1569.020 554.830 1569.440 ;
    END
  END r0_rd_out[376]
  PIN r0_rd_out[377]
    DIRECTION OUTPUT ;
    USE SIGNAL ;
    SHAPE ABUTMENT ;
    PORT
      LAYER met2 ;
      RECT 559.290 1569.020 559.430 1569.440 ;
    END
  END r0_rd_out[377]
  PIN r0_rd_out[378]
    DIRECTION OUTPUT ;
    USE SIGNAL ;
    SHAPE ABUTMENT ;
    PORT
      LAYER met2 ;
      RECT 563.890 1569.020 564.030 1569.440 ;
    END
  END r0_rd_out[378]
  PIN r0_rd_out[379]
    DIRECTION OUTPUT ;
    USE SIGNAL ;
    SHAPE ABUTMENT ;
    PORT
      LAYER met2 ;
      RECT 568.490 1569.020 568.630 1569.440 ;
    END
  END r0_rd_out[379]
  PIN r0_rd_out[380]
    DIRECTION OUTPUT ;
    USE SIGNAL ;
    SHAPE ABUTMENT ;
    PORT
      LAYER met2 ;
      RECT 573.090 1569.020 573.230 1569.440 ;
    END
  END r0_rd_out[380]
  PIN r0_rd_out[381]
    DIRECTION OUTPUT ;
    USE SIGNAL ;
    SHAPE ABUTMENT ;
    PORT
      LAYER met2 ;
      RECT 577.690 1569.020 577.830 1569.440 ;
    END
  END r0_rd_out[381]
  PIN r0_rd_out[382]
    DIRECTION OUTPUT ;
    USE SIGNAL ;
    SHAPE ABUTMENT ;
    PORT
      LAYER met2 ;
      RECT 582.290 1569.020 582.430 1569.440 ;
    END
  END r0_rd_out[382]
  PIN r0_rd_out[383]
    DIRECTION OUTPUT ;
    USE SIGNAL ;
    SHAPE ABUTMENT ;
    PORT
      LAYER met2 ;
      RECT 586.890 1569.020 587.030 1569.440 ;
    END
  END r0_rd_out[383]
  PIN r0_rd_out[384]
    DIRECTION OUTPUT ;
    USE SIGNAL ;
    SHAPE ABUTMENT ;
    PORT
      LAYER met2 ;
      RECT 591.490 1569.020 591.630 1569.440 ;
    END
  END r0_rd_out[384]
  PIN r0_rd_out[385]
    DIRECTION OUTPUT ;
    USE SIGNAL ;
    SHAPE ABUTMENT ;
    PORT
      LAYER met2 ;
      RECT 596.090 1569.020 596.230 1569.440 ;
    END
  END r0_rd_out[385]
  PIN r0_rd_out[386]
    DIRECTION OUTPUT ;
    USE SIGNAL ;
    SHAPE ABUTMENT ;
    PORT
      LAYER met2 ;
      RECT 600.690 1569.020 600.830 1569.440 ;
    END
  END r0_rd_out[386]
  PIN r0_rd_out[387]
    DIRECTION OUTPUT ;
    USE SIGNAL ;
    SHAPE ABUTMENT ;
    PORT
      LAYER met2 ;
      RECT 605.290 1569.020 605.430 1569.440 ;
    END
  END r0_rd_out[387]
  PIN r0_rd_out[388]
    DIRECTION OUTPUT ;
    USE SIGNAL ;
    SHAPE ABUTMENT ;
    PORT
      LAYER met2 ;
      RECT 609.890 1569.020 610.030 1569.440 ;
    END
  END r0_rd_out[388]
  PIN r0_rd_out[389]
    DIRECTION OUTPUT ;
    USE SIGNAL ;
    SHAPE ABUTMENT ;
    PORT
      LAYER met2 ;
      RECT 614.490 1569.020 614.630 1569.440 ;
    END
  END r0_rd_out[389]
  PIN r0_rd_out[390]
    DIRECTION OUTPUT ;
    USE SIGNAL ;
    SHAPE ABUTMENT ;
    PORT
      LAYER met2 ;
      RECT 619.090 1569.020 619.230 1569.440 ;
    END
  END r0_rd_out[390]
  PIN r0_rd_out[391]
    DIRECTION OUTPUT ;
    USE SIGNAL ;
    SHAPE ABUTMENT ;
    PORT
      LAYER met2 ;
      RECT 623.690 1569.020 623.830 1569.440 ;
    END
  END r0_rd_out[391]
  PIN r0_rd_out[392]
    DIRECTION OUTPUT ;
    USE SIGNAL ;
    SHAPE ABUTMENT ;
    PORT
      LAYER met2 ;
      RECT 628.290 1569.020 628.430 1569.440 ;
    END
  END r0_rd_out[392]
  PIN r0_rd_out[393]
    DIRECTION OUTPUT ;
    USE SIGNAL ;
    SHAPE ABUTMENT ;
    PORT
      LAYER met2 ;
      RECT 632.890 1569.020 633.030 1569.440 ;
    END
  END r0_rd_out[393]
  PIN r0_rd_out[394]
    DIRECTION OUTPUT ;
    USE SIGNAL ;
    SHAPE ABUTMENT ;
    PORT
      LAYER met2 ;
      RECT 637.490 1569.020 637.630 1569.440 ;
    END
  END r0_rd_out[394]
  PIN r0_rd_out[395]
    DIRECTION OUTPUT ;
    USE SIGNAL ;
    SHAPE ABUTMENT ;
    PORT
      LAYER met2 ;
      RECT 642.090 1569.020 642.230 1569.440 ;
    END
  END r0_rd_out[395]
  PIN r0_rd_out[396]
    DIRECTION OUTPUT ;
    USE SIGNAL ;
    SHAPE ABUTMENT ;
    PORT
      LAYER met2 ;
      RECT 646.690 1569.020 646.830 1569.440 ;
    END
  END r0_rd_out[396]
  PIN r0_rd_out[397]
    DIRECTION OUTPUT ;
    USE SIGNAL ;
    SHAPE ABUTMENT ;
    PORT
      LAYER met2 ;
      RECT 651.290 1569.020 651.430 1569.440 ;
    END
  END r0_rd_out[397]
  PIN r0_rd_out[398]
    DIRECTION OUTPUT ;
    USE SIGNAL ;
    SHAPE ABUTMENT ;
    PORT
      LAYER met2 ;
      RECT 655.890 1569.020 656.030 1569.440 ;
    END
  END r0_rd_out[398]
  PIN r0_rd_out[399]
    DIRECTION OUTPUT ;
    USE SIGNAL ;
    SHAPE ABUTMENT ;
    PORT
      LAYER met2 ;
      RECT 660.490 1569.020 660.630 1569.440 ;
    END
  END r0_rd_out[399]
  PIN r0_rd_out[400]
    DIRECTION OUTPUT ;
    USE SIGNAL ;
    SHAPE ABUTMENT ;
    PORT
      LAYER met2 ;
      RECT 665.090 1569.020 665.230 1569.440 ;
    END
  END r0_rd_out[400]
  PIN r0_rd_out[401]
    DIRECTION OUTPUT ;
    USE SIGNAL ;
    SHAPE ABUTMENT ;
    PORT
      LAYER met2 ;
      RECT 669.690 1569.020 669.830 1569.440 ;
    END
  END r0_rd_out[401]
  PIN r0_rd_out[402]
    DIRECTION OUTPUT ;
    USE SIGNAL ;
    SHAPE ABUTMENT ;
    PORT
      LAYER met2 ;
      RECT 674.290 1569.020 674.430 1569.440 ;
    END
  END r0_rd_out[402]
  PIN r0_rd_out[403]
    DIRECTION OUTPUT ;
    USE SIGNAL ;
    SHAPE ABUTMENT ;
    PORT
      LAYER met2 ;
      RECT 678.890 1569.020 679.030 1569.440 ;
    END
  END r0_rd_out[403]
  PIN r0_rd_out[404]
    DIRECTION OUTPUT ;
    USE SIGNAL ;
    SHAPE ABUTMENT ;
    PORT
      LAYER met2 ;
      RECT 683.490 1569.020 683.630 1569.440 ;
    END
  END r0_rd_out[404]
  PIN r0_rd_out[405]
    DIRECTION OUTPUT ;
    USE SIGNAL ;
    SHAPE ABUTMENT ;
    PORT
      LAYER met2 ;
      RECT 688.090 1569.020 688.230 1569.440 ;
    END
  END r0_rd_out[405]
  PIN r0_rd_out[406]
    DIRECTION OUTPUT ;
    USE SIGNAL ;
    SHAPE ABUTMENT ;
    PORT
      LAYER met2 ;
      RECT 692.690 1569.020 692.830 1569.440 ;
    END
  END r0_rd_out[406]
  PIN r0_rd_out[407]
    DIRECTION OUTPUT ;
    USE SIGNAL ;
    SHAPE ABUTMENT ;
    PORT
      LAYER met2 ;
      RECT 697.290 1569.020 697.430 1569.440 ;
    END
  END r0_rd_out[407]
  PIN r0_rd_out[408]
    DIRECTION OUTPUT ;
    USE SIGNAL ;
    SHAPE ABUTMENT ;
    PORT
      LAYER met2 ;
      RECT 701.890 1569.020 702.030 1569.440 ;
    END
  END r0_rd_out[408]
  PIN r0_rd_out[409]
    DIRECTION OUTPUT ;
    USE SIGNAL ;
    SHAPE ABUTMENT ;
    PORT
      LAYER met2 ;
      RECT 706.490 1569.020 706.630 1569.440 ;
    END
  END r0_rd_out[409]
  PIN r0_rd_out[410]
    DIRECTION OUTPUT ;
    USE SIGNAL ;
    SHAPE ABUTMENT ;
    PORT
      LAYER met2 ;
      RECT 711.090 1569.020 711.230 1569.440 ;
    END
  END r0_rd_out[410]
  PIN r0_rd_out[411]
    DIRECTION OUTPUT ;
    USE SIGNAL ;
    SHAPE ABUTMENT ;
    PORT
      LAYER met2 ;
      RECT 715.690 1569.020 715.830 1569.440 ;
    END
  END r0_rd_out[411]
  PIN r0_rd_out[412]
    DIRECTION OUTPUT ;
    USE SIGNAL ;
    SHAPE ABUTMENT ;
    PORT
      LAYER met2 ;
      RECT 720.290 1569.020 720.430 1569.440 ;
    END
  END r0_rd_out[412]
  PIN r0_rd_out[413]
    DIRECTION OUTPUT ;
    USE SIGNAL ;
    SHAPE ABUTMENT ;
    PORT
      LAYER met2 ;
      RECT 724.890 1569.020 725.030 1569.440 ;
    END
  END r0_rd_out[413]
  PIN r0_rd_out[414]
    DIRECTION OUTPUT ;
    USE SIGNAL ;
    SHAPE ABUTMENT ;
    PORT
      LAYER met2 ;
      RECT 729.490 1569.020 729.630 1569.440 ;
    END
  END r0_rd_out[414]
  PIN r0_rd_out[415]
    DIRECTION OUTPUT ;
    USE SIGNAL ;
    SHAPE ABUTMENT ;
    PORT
      LAYER met2 ;
      RECT 734.090 1569.020 734.230 1569.440 ;
    END
  END r0_rd_out[415]
  PIN r0_rd_out[416]
    DIRECTION OUTPUT ;
    USE SIGNAL ;
    SHAPE ABUTMENT ;
    PORT
      LAYER met2 ;
      RECT 738.690 1569.020 738.830 1569.440 ;
    END
  END r0_rd_out[416]
  PIN r0_rd_out[417]
    DIRECTION OUTPUT ;
    USE SIGNAL ;
    SHAPE ABUTMENT ;
    PORT
      LAYER met2 ;
      RECT 743.290 1569.020 743.430 1569.440 ;
    END
  END r0_rd_out[417]
  PIN r0_rd_out[418]
    DIRECTION OUTPUT ;
    USE SIGNAL ;
    SHAPE ABUTMENT ;
    PORT
      LAYER met2 ;
      RECT 747.890 1569.020 748.030 1569.440 ;
    END
  END r0_rd_out[418]
  PIN r0_rd_out[419]
    DIRECTION OUTPUT ;
    USE SIGNAL ;
    SHAPE ABUTMENT ;
    PORT
      LAYER met2 ;
      RECT 752.490 1569.020 752.630 1569.440 ;
    END
  END r0_rd_out[419]
  PIN r0_rd_out[420]
    DIRECTION OUTPUT ;
    USE SIGNAL ;
    SHAPE ABUTMENT ;
    PORT
      LAYER met2 ;
      RECT 757.090 1569.020 757.230 1569.440 ;
    END
  END r0_rd_out[420]
  PIN r0_rd_out[421]
    DIRECTION OUTPUT ;
    USE SIGNAL ;
    SHAPE ABUTMENT ;
    PORT
      LAYER met2 ;
      RECT 761.690 1569.020 761.830 1569.440 ;
    END
  END r0_rd_out[421]
  PIN r0_rd_out[422]
    DIRECTION OUTPUT ;
    USE SIGNAL ;
    SHAPE ABUTMENT ;
    PORT
      LAYER met2 ;
      RECT 766.290 1569.020 766.430 1569.440 ;
    END
  END r0_rd_out[422]
  PIN r0_rd_out[423]
    DIRECTION OUTPUT ;
    USE SIGNAL ;
    SHAPE ABUTMENT ;
    PORT
      LAYER met2 ;
      RECT 770.890 1569.020 771.030 1569.440 ;
    END
  END r0_rd_out[423]
  PIN r0_rd_out[424]
    DIRECTION OUTPUT ;
    USE SIGNAL ;
    SHAPE ABUTMENT ;
    PORT
      LAYER met2 ;
      RECT 775.490 1569.020 775.630 1569.440 ;
    END
  END r0_rd_out[424]
  PIN r0_rd_out[425]
    DIRECTION OUTPUT ;
    USE SIGNAL ;
    SHAPE ABUTMENT ;
    PORT
      LAYER met2 ;
      RECT 780.090 1569.020 780.230 1569.440 ;
    END
  END r0_rd_out[425]
  PIN r0_rd_out[426]
    DIRECTION OUTPUT ;
    USE SIGNAL ;
    SHAPE ABUTMENT ;
    PORT
      LAYER met2 ;
      RECT 784.690 1569.020 784.830 1569.440 ;
    END
  END r0_rd_out[426]
  PIN r0_rd_out[427]
    DIRECTION OUTPUT ;
    USE SIGNAL ;
    SHAPE ABUTMENT ;
    PORT
      LAYER met2 ;
      RECT 789.290 1569.020 789.430 1569.440 ;
    END
  END r0_rd_out[427]
  PIN r0_rd_out[428]
    DIRECTION OUTPUT ;
    USE SIGNAL ;
    SHAPE ABUTMENT ;
    PORT
      LAYER met2 ;
      RECT 793.890 1569.020 794.030 1569.440 ;
    END
  END r0_rd_out[428]
  PIN r0_rd_out[429]
    DIRECTION OUTPUT ;
    USE SIGNAL ;
    SHAPE ABUTMENT ;
    PORT
      LAYER met2 ;
      RECT 798.490 1569.020 798.630 1569.440 ;
    END
  END r0_rd_out[429]
  PIN r0_rd_out[430]
    DIRECTION OUTPUT ;
    USE SIGNAL ;
    SHAPE ABUTMENT ;
    PORT
      LAYER met2 ;
      RECT 803.090 1569.020 803.230 1569.440 ;
    END
  END r0_rd_out[430]
  PIN r0_rd_out[431]
    DIRECTION OUTPUT ;
    USE SIGNAL ;
    SHAPE ABUTMENT ;
    PORT
      LAYER met2 ;
      RECT 807.690 1569.020 807.830 1569.440 ;
    END
  END r0_rd_out[431]
  PIN r0_rd_out[432]
    DIRECTION OUTPUT ;
    USE SIGNAL ;
    SHAPE ABUTMENT ;
    PORT
      LAYER met2 ;
      RECT 812.290 1569.020 812.430 1569.440 ;
    END
  END r0_rd_out[432]
  PIN r0_rd_out[433]
    DIRECTION OUTPUT ;
    USE SIGNAL ;
    SHAPE ABUTMENT ;
    PORT
      LAYER met2 ;
      RECT 816.890 1569.020 817.030 1569.440 ;
    END
  END r0_rd_out[433]
  PIN r0_rd_out[434]
    DIRECTION OUTPUT ;
    USE SIGNAL ;
    SHAPE ABUTMENT ;
    PORT
      LAYER met2 ;
      RECT 821.490 1569.020 821.630 1569.440 ;
    END
  END r0_rd_out[434]
  PIN r0_rd_out[435]
    DIRECTION OUTPUT ;
    USE SIGNAL ;
    SHAPE ABUTMENT ;
    PORT
      LAYER met2 ;
      RECT 826.090 1569.020 826.230 1569.440 ;
    END
  END r0_rd_out[435]
  PIN r0_rd_out[436]
    DIRECTION OUTPUT ;
    USE SIGNAL ;
    SHAPE ABUTMENT ;
    PORT
      LAYER met2 ;
      RECT 830.690 1569.020 830.830 1569.440 ;
    END
  END r0_rd_out[436]
  PIN r0_rd_out[437]
    DIRECTION OUTPUT ;
    USE SIGNAL ;
    SHAPE ABUTMENT ;
    PORT
      LAYER met2 ;
      RECT 835.290 1569.020 835.430 1569.440 ;
    END
  END r0_rd_out[437]
  PIN r0_rd_out[438]
    DIRECTION OUTPUT ;
    USE SIGNAL ;
    SHAPE ABUTMENT ;
    PORT
      LAYER met2 ;
      RECT 839.890 1569.020 840.030 1569.440 ;
    END
  END r0_rd_out[438]
  PIN r0_rd_out[439]
    DIRECTION OUTPUT ;
    USE SIGNAL ;
    SHAPE ABUTMENT ;
    PORT
      LAYER met2 ;
      RECT 844.490 1569.020 844.630 1569.440 ;
    END
  END r0_rd_out[439]
  PIN r0_rd_out[440]
    DIRECTION OUTPUT ;
    USE SIGNAL ;
    SHAPE ABUTMENT ;
    PORT
      LAYER met2 ;
      RECT 849.090 1569.020 849.230 1569.440 ;
    END
  END r0_rd_out[440]
  PIN r0_rd_out[441]
    DIRECTION OUTPUT ;
    USE SIGNAL ;
    SHAPE ABUTMENT ;
    PORT
      LAYER met2 ;
      RECT 853.690 1569.020 853.830 1569.440 ;
    END
  END r0_rd_out[441]
  PIN r0_rd_out[442]
    DIRECTION OUTPUT ;
    USE SIGNAL ;
    SHAPE ABUTMENT ;
    PORT
      LAYER met2 ;
      RECT 858.290 1569.020 858.430 1569.440 ;
    END
  END r0_rd_out[442]
  PIN r0_rd_out[443]
    DIRECTION OUTPUT ;
    USE SIGNAL ;
    SHAPE ABUTMENT ;
    PORT
      LAYER met2 ;
      RECT 862.890 1569.020 863.030 1569.440 ;
    END
  END r0_rd_out[443]
  PIN r0_rd_out[444]
    DIRECTION OUTPUT ;
    USE SIGNAL ;
    SHAPE ABUTMENT ;
    PORT
      LAYER met2 ;
      RECT 867.490 1569.020 867.630 1569.440 ;
    END
  END r0_rd_out[444]
  PIN r0_rd_out[445]
    DIRECTION OUTPUT ;
    USE SIGNAL ;
    SHAPE ABUTMENT ;
    PORT
      LAYER met2 ;
      RECT 872.090 1569.020 872.230 1569.440 ;
    END
  END r0_rd_out[445]
  PIN r0_rd_out[446]
    DIRECTION OUTPUT ;
    USE SIGNAL ;
    SHAPE ABUTMENT ;
    PORT
      LAYER met2 ;
      RECT 876.690 1569.020 876.830 1569.440 ;
    END
  END r0_rd_out[446]
  PIN r0_rd_out[447]
    DIRECTION OUTPUT ;
    USE SIGNAL ;
    SHAPE ABUTMENT ;
    PORT
      LAYER met2 ;
      RECT 881.290 1569.020 881.430 1569.440 ;
    END
  END r0_rd_out[447]
  PIN r0_rd_out[448]
    DIRECTION OUTPUT ;
    USE SIGNAL ;
    SHAPE ABUTMENT ;
    PORT
      LAYER met2 ;
      RECT 885.890 1569.020 886.030 1569.440 ;
    END
  END r0_rd_out[448]
  PIN r0_rd_out[449]
    DIRECTION OUTPUT ;
    USE SIGNAL ;
    SHAPE ABUTMENT ;
    PORT
      LAYER met2 ;
      RECT 890.490 1569.020 890.630 1569.440 ;
    END
  END r0_rd_out[449]
  PIN r0_rd_out[450]
    DIRECTION OUTPUT ;
    USE SIGNAL ;
    SHAPE ABUTMENT ;
    PORT
      LAYER met2 ;
      RECT 895.090 1569.020 895.230 1569.440 ;
    END
  END r0_rd_out[450]
  PIN r0_rd_out[451]
    DIRECTION OUTPUT ;
    USE SIGNAL ;
    SHAPE ABUTMENT ;
    PORT
      LAYER met2 ;
      RECT 899.690 1569.020 899.830 1569.440 ;
    END
  END r0_rd_out[451]
  PIN r0_rd_out[452]
    DIRECTION OUTPUT ;
    USE SIGNAL ;
    SHAPE ABUTMENT ;
    PORT
      LAYER met2 ;
      RECT 904.290 1569.020 904.430 1569.440 ;
    END
  END r0_rd_out[452]
  PIN r0_rd_out[453]
    DIRECTION OUTPUT ;
    USE SIGNAL ;
    SHAPE ABUTMENT ;
    PORT
      LAYER met2 ;
      RECT 908.890 1569.020 909.030 1569.440 ;
    END
  END r0_rd_out[453]
  PIN r0_rd_out[454]
    DIRECTION OUTPUT ;
    USE SIGNAL ;
    SHAPE ABUTMENT ;
    PORT
      LAYER met2 ;
      RECT 913.490 1569.020 913.630 1569.440 ;
    END
  END r0_rd_out[454]
  PIN r0_rd_out[455]
    DIRECTION OUTPUT ;
    USE SIGNAL ;
    SHAPE ABUTMENT ;
    PORT
      LAYER met2 ;
      RECT 918.090 1569.020 918.230 1569.440 ;
    END
  END r0_rd_out[455]
  PIN r0_rd_out[456]
    DIRECTION OUTPUT ;
    USE SIGNAL ;
    SHAPE ABUTMENT ;
    PORT
      LAYER met2 ;
      RECT 922.690 1569.020 922.830 1569.440 ;
    END
  END r0_rd_out[456]
  PIN r0_rd_out[457]
    DIRECTION OUTPUT ;
    USE SIGNAL ;
    SHAPE ABUTMENT ;
    PORT
      LAYER met2 ;
      RECT 927.290 1569.020 927.430 1569.440 ;
    END
  END r0_rd_out[457]
  PIN r0_rd_out[458]
    DIRECTION OUTPUT ;
    USE SIGNAL ;
    SHAPE ABUTMENT ;
    PORT
      LAYER met2 ;
      RECT 931.890 1569.020 932.030 1569.440 ;
    END
  END r0_rd_out[458]
  PIN r0_rd_out[459]
    DIRECTION OUTPUT ;
    USE SIGNAL ;
    SHAPE ABUTMENT ;
    PORT
      LAYER met2 ;
      RECT 936.490 1569.020 936.630 1569.440 ;
    END
  END r0_rd_out[459]
  PIN r0_rd_out[460]
    DIRECTION OUTPUT ;
    USE SIGNAL ;
    SHAPE ABUTMENT ;
    PORT
      LAYER met2 ;
      RECT 941.090 1569.020 941.230 1569.440 ;
    END
  END r0_rd_out[460]
  PIN r0_rd_out[461]
    DIRECTION OUTPUT ;
    USE SIGNAL ;
    SHAPE ABUTMENT ;
    PORT
      LAYER met2 ;
      RECT 945.690 1569.020 945.830 1569.440 ;
    END
  END r0_rd_out[461]
  PIN r0_rd_out[462]
    DIRECTION OUTPUT ;
    USE SIGNAL ;
    SHAPE ABUTMENT ;
    PORT
      LAYER met2 ;
      RECT 950.290 1569.020 950.430 1569.440 ;
    END
  END r0_rd_out[462]
  PIN r0_rd_out[463]
    DIRECTION OUTPUT ;
    USE SIGNAL ;
    SHAPE ABUTMENT ;
    PORT
      LAYER met2 ;
      RECT 954.890 1569.020 955.030 1569.440 ;
    END
  END r0_rd_out[463]
  PIN r0_rd_out[464]
    DIRECTION OUTPUT ;
    USE SIGNAL ;
    SHAPE ABUTMENT ;
    PORT
      LAYER met2 ;
      RECT 959.490 1569.020 959.630 1569.440 ;
    END
  END r0_rd_out[464]
  PIN r0_rd_out[465]
    DIRECTION OUTPUT ;
    USE SIGNAL ;
    SHAPE ABUTMENT ;
    PORT
      LAYER met2 ;
      RECT 964.090 1569.020 964.230 1569.440 ;
    END
  END r0_rd_out[465]
  PIN r0_rd_out[466]
    DIRECTION OUTPUT ;
    USE SIGNAL ;
    SHAPE ABUTMENT ;
    PORT
      LAYER met2 ;
      RECT 968.690 1569.020 968.830 1569.440 ;
    END
  END r0_rd_out[466]
  PIN r0_rd_out[467]
    DIRECTION OUTPUT ;
    USE SIGNAL ;
    SHAPE ABUTMENT ;
    PORT
      LAYER met2 ;
      RECT 973.290 1569.020 973.430 1569.440 ;
    END
  END r0_rd_out[467]
  PIN r0_rd_out[468]
    DIRECTION OUTPUT ;
    USE SIGNAL ;
    SHAPE ABUTMENT ;
    PORT
      LAYER met2 ;
      RECT 977.890 1569.020 978.030 1569.440 ;
    END
  END r0_rd_out[468]
  PIN r0_rd_out[469]
    DIRECTION OUTPUT ;
    USE SIGNAL ;
    SHAPE ABUTMENT ;
    PORT
      LAYER met2 ;
      RECT 982.490 1569.020 982.630 1569.440 ;
    END
  END r0_rd_out[469]
  PIN r0_rd_out[470]
    DIRECTION OUTPUT ;
    USE SIGNAL ;
    SHAPE ABUTMENT ;
    PORT
      LAYER met2 ;
      RECT 987.090 1569.020 987.230 1569.440 ;
    END
  END r0_rd_out[470]
  PIN r0_rd_out[471]
    DIRECTION OUTPUT ;
    USE SIGNAL ;
    SHAPE ABUTMENT ;
    PORT
      LAYER met2 ;
      RECT 991.690 1569.020 991.830 1569.440 ;
    END
  END r0_rd_out[471]
  PIN r0_rd_out[472]
    DIRECTION OUTPUT ;
    USE SIGNAL ;
    SHAPE ABUTMENT ;
    PORT
      LAYER met2 ;
      RECT 996.290 1569.020 996.430 1569.440 ;
    END
  END r0_rd_out[472]
  PIN r0_rd_out[473]
    DIRECTION OUTPUT ;
    USE SIGNAL ;
    SHAPE ABUTMENT ;
    PORT
      LAYER met2 ;
      RECT 1000.890 1569.020 1001.030 1569.440 ;
    END
  END r0_rd_out[473]
  PIN r0_rd_out[474]
    DIRECTION OUTPUT ;
    USE SIGNAL ;
    SHAPE ABUTMENT ;
    PORT
      LAYER met2 ;
      RECT 1005.490 1569.020 1005.630 1569.440 ;
    END
  END r0_rd_out[474]
  PIN r0_rd_out[475]
    DIRECTION OUTPUT ;
    USE SIGNAL ;
    SHAPE ABUTMENT ;
    PORT
      LAYER met2 ;
      RECT 1010.090 1569.020 1010.230 1569.440 ;
    END
  END r0_rd_out[475]
  PIN r0_rd_out[476]
    DIRECTION OUTPUT ;
    USE SIGNAL ;
    SHAPE ABUTMENT ;
    PORT
      LAYER met2 ;
      RECT 1014.690 1569.020 1014.830 1569.440 ;
    END
  END r0_rd_out[476]
  PIN r0_rd_out[477]
    DIRECTION OUTPUT ;
    USE SIGNAL ;
    SHAPE ABUTMENT ;
    PORT
      LAYER met2 ;
      RECT 1019.290 1569.020 1019.430 1569.440 ;
    END
  END r0_rd_out[477]
  PIN r0_rd_out[478]
    DIRECTION OUTPUT ;
    USE SIGNAL ;
    SHAPE ABUTMENT ;
    PORT
      LAYER met2 ;
      RECT 1023.890 1569.020 1024.030 1569.440 ;
    END
  END r0_rd_out[478]
  PIN r0_rd_out[479]
    DIRECTION OUTPUT ;
    USE SIGNAL ;
    SHAPE ABUTMENT ;
    PORT
      LAYER met2 ;
      RECT 1028.490 1569.020 1028.630 1569.440 ;
    END
  END r0_rd_out[479]
  PIN r0_rd_out[480]
    DIRECTION OUTPUT ;
    USE SIGNAL ;
    SHAPE ABUTMENT ;
    PORT
      LAYER met2 ;
      RECT 1033.090 1569.020 1033.230 1569.440 ;
    END
  END r0_rd_out[480]
  PIN r0_rd_out[481]
    DIRECTION OUTPUT ;
    USE SIGNAL ;
    SHAPE ABUTMENT ;
    PORT
      LAYER met2 ;
      RECT 1037.690 1569.020 1037.830 1569.440 ;
    END
  END r0_rd_out[481]
  PIN r0_rd_out[482]
    DIRECTION OUTPUT ;
    USE SIGNAL ;
    SHAPE ABUTMENT ;
    PORT
      LAYER met2 ;
      RECT 1042.290 1569.020 1042.430 1569.440 ;
    END
  END r0_rd_out[482]
  PIN r0_rd_out[483]
    DIRECTION OUTPUT ;
    USE SIGNAL ;
    SHAPE ABUTMENT ;
    PORT
      LAYER met2 ;
      RECT 1046.890 1569.020 1047.030 1569.440 ;
    END
  END r0_rd_out[483]
  PIN r0_rd_out[484]
    DIRECTION OUTPUT ;
    USE SIGNAL ;
    SHAPE ABUTMENT ;
    PORT
      LAYER met2 ;
      RECT 1051.490 1569.020 1051.630 1569.440 ;
    END
  END r0_rd_out[484]
  PIN r0_rd_out[485]
    DIRECTION OUTPUT ;
    USE SIGNAL ;
    SHAPE ABUTMENT ;
    PORT
      LAYER met2 ;
      RECT 1056.090 1569.020 1056.230 1569.440 ;
    END
  END r0_rd_out[485]
  PIN r0_rd_out[486]
    DIRECTION OUTPUT ;
    USE SIGNAL ;
    SHAPE ABUTMENT ;
    PORT
      LAYER met2 ;
      RECT 1060.690 1569.020 1060.830 1569.440 ;
    END
  END r0_rd_out[486]
  PIN r0_rd_out[487]
    DIRECTION OUTPUT ;
    USE SIGNAL ;
    SHAPE ABUTMENT ;
    PORT
      LAYER met2 ;
      RECT 1065.290 1569.020 1065.430 1569.440 ;
    END
  END r0_rd_out[487]
  PIN r0_rd_out[488]
    DIRECTION OUTPUT ;
    USE SIGNAL ;
    SHAPE ABUTMENT ;
    PORT
      LAYER met2 ;
      RECT 1069.890 1569.020 1070.030 1569.440 ;
    END
  END r0_rd_out[488]
  PIN r0_rd_out[489]
    DIRECTION OUTPUT ;
    USE SIGNAL ;
    SHAPE ABUTMENT ;
    PORT
      LAYER met2 ;
      RECT 1074.490 1569.020 1074.630 1569.440 ;
    END
  END r0_rd_out[489]
  PIN r0_rd_out[490]
    DIRECTION OUTPUT ;
    USE SIGNAL ;
    SHAPE ABUTMENT ;
    PORT
      LAYER met2 ;
      RECT 1079.090 1569.020 1079.230 1569.440 ;
    END
  END r0_rd_out[490]
  PIN r0_rd_out[491]
    DIRECTION OUTPUT ;
    USE SIGNAL ;
    SHAPE ABUTMENT ;
    PORT
      LAYER met2 ;
      RECT 1083.690 1569.020 1083.830 1569.440 ;
    END
  END r0_rd_out[491]
  PIN r0_rd_out[492]
    DIRECTION OUTPUT ;
    USE SIGNAL ;
    SHAPE ABUTMENT ;
    PORT
      LAYER met2 ;
      RECT 1088.290 1569.020 1088.430 1569.440 ;
    END
  END r0_rd_out[492]
  PIN r0_rd_out[493]
    DIRECTION OUTPUT ;
    USE SIGNAL ;
    SHAPE ABUTMENT ;
    PORT
      LAYER met2 ;
      RECT 1092.890 1569.020 1093.030 1569.440 ;
    END
  END r0_rd_out[493]
  PIN r0_rd_out[494]
    DIRECTION OUTPUT ;
    USE SIGNAL ;
    SHAPE ABUTMENT ;
    PORT
      LAYER met2 ;
      RECT 1097.490 1569.020 1097.630 1569.440 ;
    END
  END r0_rd_out[494]
  PIN r0_rd_out[495]
    DIRECTION OUTPUT ;
    USE SIGNAL ;
    SHAPE ABUTMENT ;
    PORT
      LAYER met2 ;
      RECT 1102.090 1569.020 1102.230 1569.440 ;
    END
  END r0_rd_out[495]
  PIN r0_rd_out[496]
    DIRECTION OUTPUT ;
    USE SIGNAL ;
    SHAPE ABUTMENT ;
    PORT
      LAYER met2 ;
      RECT 1106.690 1569.020 1106.830 1569.440 ;
    END
  END r0_rd_out[496]
  PIN r0_rd_out[497]
    DIRECTION OUTPUT ;
    USE SIGNAL ;
    SHAPE ABUTMENT ;
    PORT
      LAYER met2 ;
      RECT 1111.290 1569.020 1111.430 1569.440 ;
    END
  END r0_rd_out[497]
  PIN r0_rd_out[498]
    DIRECTION OUTPUT ;
    USE SIGNAL ;
    SHAPE ABUTMENT ;
    PORT
      LAYER met2 ;
      RECT 1115.890 1569.020 1116.030 1569.440 ;
    END
  END r0_rd_out[498]
  PIN r0_rd_out[499]
    DIRECTION OUTPUT ;
    USE SIGNAL ;
    SHAPE ABUTMENT ;
    PORT
      LAYER met2 ;
      RECT 1120.490 1569.020 1120.630 1569.440 ;
    END
  END r0_rd_out[499]
  PIN r0_rd_out[500]
    DIRECTION OUTPUT ;
    USE SIGNAL ;
    SHAPE ABUTMENT ;
    PORT
      LAYER met2 ;
      RECT 1125.090 1569.020 1125.230 1569.440 ;
    END
  END r0_rd_out[500]
  PIN r0_rd_out[501]
    DIRECTION OUTPUT ;
    USE SIGNAL ;
    SHAPE ABUTMENT ;
    PORT
      LAYER met2 ;
      RECT 1129.690 1569.020 1129.830 1569.440 ;
    END
  END r0_rd_out[501]
  PIN r0_rd_out[502]
    DIRECTION OUTPUT ;
    USE SIGNAL ;
    SHAPE ABUTMENT ;
    PORT
      LAYER met2 ;
      RECT 1134.290 1569.020 1134.430 1569.440 ;
    END
  END r0_rd_out[502]
  PIN r0_rd_out[503]
    DIRECTION OUTPUT ;
    USE SIGNAL ;
    SHAPE ABUTMENT ;
    PORT
      LAYER met2 ;
      RECT 1138.890 1569.020 1139.030 1569.440 ;
    END
  END r0_rd_out[503]
  PIN r0_rd_out[504]
    DIRECTION OUTPUT ;
    USE SIGNAL ;
    SHAPE ABUTMENT ;
    PORT
      LAYER met2 ;
      RECT 1143.490 1569.020 1143.630 1569.440 ;
    END
  END r0_rd_out[504]
  PIN r0_rd_out[505]
    DIRECTION OUTPUT ;
    USE SIGNAL ;
    SHAPE ABUTMENT ;
    PORT
      LAYER met2 ;
      RECT 1148.090 1569.020 1148.230 1569.440 ;
    END
  END r0_rd_out[505]
  PIN r0_rd_out[506]
    DIRECTION OUTPUT ;
    USE SIGNAL ;
    SHAPE ABUTMENT ;
    PORT
      LAYER met2 ;
      RECT 1152.690 1569.020 1152.830 1569.440 ;
    END
  END r0_rd_out[506]
  PIN r0_rd_out[507]
    DIRECTION OUTPUT ;
    USE SIGNAL ;
    SHAPE ABUTMENT ;
    PORT
      LAYER met2 ;
      RECT 1157.290 1569.020 1157.430 1569.440 ;
    END
  END r0_rd_out[507]
  PIN r0_rd_out[508]
    DIRECTION OUTPUT ;
    USE SIGNAL ;
    SHAPE ABUTMENT ;
    PORT
      LAYER met2 ;
      RECT 1161.890 1569.020 1162.030 1569.440 ;
    END
  END r0_rd_out[508]
  PIN r0_rd_out[509]
    DIRECTION OUTPUT ;
    USE SIGNAL ;
    SHAPE ABUTMENT ;
    PORT
      LAYER met2 ;
      RECT 1166.490 1569.020 1166.630 1569.440 ;
    END
  END r0_rd_out[509]
  PIN r0_rd_out[510]
    DIRECTION OUTPUT ;
    USE SIGNAL ;
    SHAPE ABUTMENT ;
    PORT
      LAYER met2 ;
      RECT 1171.090 1569.020 1171.230 1569.440 ;
    END
  END r0_rd_out[510]
  PIN r0_rd_out[511]
    DIRECTION OUTPUT ;
    USE SIGNAL ;
    SHAPE ABUTMENT ;
    PORT
      LAYER met2 ;
      RECT 1175.690 1569.020 1175.830 1569.440 ;
    END
  END r0_rd_out[511]
  PIN w0_addr_in[0]
    DIRECTION INPUT ;
    USE SIGNAL ;
    SHAPE ABUTMENT ;
    PORT
      LAYER met3 ;
      RECT 0.000 1396.570 0.900 1396.870 ;
    END
  END w0_addr_in[0]
  PIN w0_addr_in[1]
    DIRECTION INPUT ;
    USE SIGNAL ;
    SHAPE ABUTMENT ;
    PORT
      LAYER met3 ;
      RECT 0.000 1407.450 0.900 1407.750 ;
    END
  END w0_addr_in[1]
  PIN w0_addr_in[2]
    DIRECTION INPUT ;
    USE SIGNAL ;
    SHAPE ABUTMENT ;
    PORT
      LAYER met3 ;
      RECT 0.000 1418.330 0.900 1418.630 ;
    END
  END w0_addr_in[2]
  PIN w0_addr_in[3]
    DIRECTION INPUT ;
    USE SIGNAL ;
    SHAPE ABUTMENT ;
    PORT
      LAYER met3 ;
      RECT 0.000 1429.210 0.900 1429.510 ;
    END
  END w0_addr_in[3]
  PIN w0_addr_in[4]
    DIRECTION INPUT ;
    USE SIGNAL ;
    SHAPE ABUTMENT ;
    PORT
      LAYER met3 ;
      RECT 1301.820 1396.570 1302.720 1396.870 ;
    END
  END w0_addr_in[4]
  PIN w0_addr_in[5]
    DIRECTION INPUT ;
    USE SIGNAL ;
    SHAPE ABUTMENT ;
    PORT
      LAYER met3 ;
      RECT 1301.820 1407.450 1302.720 1407.750 ;
    END
  END w0_addr_in[5]
  PIN w0_addr_in[6]
    DIRECTION INPUT ;
    USE SIGNAL ;
    SHAPE ABUTMENT ;
    PORT
      LAYER met3 ;
      RECT 1301.820 1418.330 1302.720 1418.630 ;
    END
  END w0_addr_in[6]
  PIN w0_addr_in[7]
    DIRECTION INPUT ;
    USE SIGNAL ;
    SHAPE ABUTMENT ;
    PORT
      LAYER met3 ;
      RECT 1301.820 1429.210 1302.720 1429.510 ;
    END
  END w0_addr_in[7]
  PIN r0_addr_in[0]
    DIRECTION INPUT ;
    USE SIGNAL ;
    SHAPE ABUTMENT ;
    PORT
      LAYER met3 ;
      RECT 0.000 1440.090 0.900 1440.390 ;
    END
  END r0_addr_in[0]
  PIN r0_addr_in[1]
    DIRECTION INPUT ;
    USE SIGNAL ;
    SHAPE ABUTMENT ;
    PORT
      LAYER met3 ;
      RECT 0.000 1450.970 0.900 1451.270 ;
    END
  END r0_addr_in[1]
  PIN r0_addr_in[2]
    DIRECTION INPUT ;
    USE SIGNAL ;
    SHAPE ABUTMENT ;
    PORT
      LAYER met3 ;
      RECT 0.000 1461.850 0.900 1462.150 ;
    END
  END r0_addr_in[2]
  PIN r0_addr_in[3]
    DIRECTION INPUT ;
    USE SIGNAL ;
    SHAPE ABUTMENT ;
    PORT
      LAYER met3 ;
      RECT 0.000 1472.730 0.900 1473.030 ;
    END
  END r0_addr_in[3]
  PIN r0_addr_in[4]
    DIRECTION INPUT ;
    USE SIGNAL ;
    SHAPE ABUTMENT ;
    PORT
      LAYER met3 ;
      RECT 1301.820 1440.090 1302.720 1440.390 ;
    END
  END r0_addr_in[4]
  PIN r0_addr_in[5]
    DIRECTION INPUT ;
    USE SIGNAL ;
    SHAPE ABUTMENT ;
    PORT
      LAYER met3 ;
      RECT 1301.820 1450.970 1302.720 1451.270 ;
    END
  END r0_addr_in[5]
  PIN r0_addr_in[6]
    DIRECTION INPUT ;
    USE SIGNAL ;
    SHAPE ABUTMENT ;
    PORT
      LAYER met3 ;
      RECT 1301.820 1461.850 1302.720 1462.150 ;
    END
  END r0_addr_in[6]
  PIN r0_addr_in[7]
    DIRECTION INPUT ;
    USE SIGNAL ;
    SHAPE ABUTMENT ;
    PORT
      LAYER met3 ;
      RECT 1301.820 1472.730 1302.720 1473.030 ;
    END
  END r0_addr_in[7]
  PIN w0_we_in
    DIRECTION INPUT ;
    USE SIGNAL ;
    SHAPE ABUTMENT ;
    PORT
      LAYER met2 ;
      RECT 1180.290 1569.020 1180.430 1569.440 ;
    END
  END w0_we_in
  PIN w0_ce_in
    DIRECTION INPUT ;
    USE SIGNAL ;
    SHAPE ABUTMENT ;
    PORT
      LAYER met2 ;
      RECT 1184.890 1569.020 1185.030 1569.440 ;
    END
  END w0_ce_in
  PIN w0_clk
    DIRECTION INPUT ;
    USE SIGNAL ;
    SHAPE ABUTMENT ;
    PORT
      LAYER met2 ;
      RECT 1189.490 1569.020 1189.630 1569.440 ;
    END
  END w0_clk
  PIN r0_ce_in
    DIRECTION INPUT ;
    USE SIGNAL ;
    SHAPE ABUTMENT ;
    PORT
      LAYER met2 ;
      RECT 1194.090 1569.020 1194.230 1569.440 ;
    END
  END r0_ce_in
  PIN r0_clk
    DIRECTION INPUT ;
    USE SIGNAL ;
    SHAPE ABUTMENT ;
    PORT
      LAYER met2 ;
      RECT 1198.690 1569.020 1198.830 1569.440 ;
    END
  END r0_clk
  PIN VSS
    DIRECTION INOUT ;
    USE GROUND ;
    PORT
      LAYER met4 ;
      RECT 2.160 4.080 3.360 1565.360 ;
      RECT 13.040 4.080 14.240 1565.360 ;
      RECT 23.920 4.080 25.120 1565.360 ;
      RECT 34.800 4.080 36.000 1565.360 ;
      RECT 45.680 4.080 46.880 1565.360 ;
      RECT 56.560 4.080 57.760 1565.360 ;
      RECT 67.440 4.080 68.640 1565.360 ;
      RECT 78.320 4.080 79.520 1565.360 ;
      RECT 89.200 4.080 90.400 1565.360 ;
      RECT 100.080 4.080 101.280 1565.360 ;
      RECT 110.960 4.080 112.160 1565.360 ;
      RECT 121.840 4.080 123.040 1565.360 ;
      RECT 132.720 4.080 133.920 1565.360 ;
      RECT 143.600 4.080 144.800 1565.360 ;
      RECT 154.480 4.080 155.680 1565.360 ;
      RECT 165.360 4.080 166.560 1565.360 ;
      RECT 176.240 4.080 177.440 1565.360 ;
      RECT 187.120 4.080 188.320 1565.360 ;
      RECT 198.000 4.080 199.200 1565.360 ;
      RECT 208.880 4.080 210.080 1565.360 ;
      RECT 219.760 4.080 220.960 1565.360 ;
      RECT 230.640 4.080 231.840 1565.360 ;
      RECT 241.520 4.080 242.720 1565.360 ;
      RECT 252.400 4.080 253.600 1565.360 ;
      RECT 263.280 4.080 264.480 1565.360 ;
      RECT 274.160 4.080 275.360 1565.360 ;
      RECT 285.040 4.080 286.240 1565.360 ;
      RECT 295.920 4.080 297.120 1565.360 ;
      RECT 306.800 4.080 308.000 1565.360 ;
      RECT 317.680 4.080 318.880 1565.360 ;
      RECT 328.560 4.080 329.760 1565.360 ;
      RECT 339.440 4.080 340.640 1565.360 ;
      RECT 350.320 4.080 351.520 1565.360 ;
      RECT 361.200 4.080 362.400 1565.360 ;
      RECT 372.080 4.080 373.280 1565.360 ;
      RECT 382.960 4.080 384.160 1565.360 ;
      RECT 393.840 4.080 395.040 1565.360 ;
      RECT 404.720 4.080 405.920 1565.360 ;
      RECT 415.600 4.080 416.800 1565.360 ;
      RECT 426.480 4.080 427.680 1565.360 ;
      RECT 437.360 4.080 438.560 1565.360 ;
      RECT 448.240 4.080 449.440 1565.360 ;
      RECT 459.120 4.080 460.320 1565.360 ;
      RECT 470.000 4.080 471.200 1565.360 ;
      RECT 480.880 4.080 482.080 1565.360 ;
      RECT 491.760 4.080 492.960 1565.360 ;
      RECT 502.640 4.080 503.840 1565.360 ;
      RECT 513.520 4.080 514.720 1565.360 ;
      RECT 524.400 4.080 525.600 1565.360 ;
      RECT 535.280 4.080 536.480 1565.360 ;
      RECT 546.160 4.080 547.360 1565.360 ;
      RECT 557.040 4.080 558.240 1565.360 ;
      RECT 567.920 4.080 569.120 1565.360 ;
      RECT 578.800 4.080 580.000 1565.360 ;
      RECT 589.680 4.080 590.880 1565.360 ;
      RECT 600.560 4.080 601.760 1565.360 ;
      RECT 611.440 4.080 612.640 1565.360 ;
      RECT 622.320 4.080 623.520 1565.360 ;
      RECT 633.200 4.080 634.400 1565.360 ;
      RECT 644.080 4.080 645.280 1565.360 ;
      RECT 654.960 4.080 656.160 1565.360 ;
      RECT 665.840 4.080 667.040 1565.360 ;
      RECT 676.720 4.080 677.920 1565.360 ;
      RECT 687.600 4.080 688.800 1565.360 ;
      RECT 698.480 4.080 699.680 1565.360 ;
      RECT 709.360 4.080 710.560 1565.360 ;
      RECT 720.240 4.080 721.440 1565.360 ;
      RECT 731.120 4.080 732.320 1565.360 ;
      RECT 742.000 4.080 743.200 1565.360 ;
      RECT 752.880 4.080 754.080 1565.360 ;
      RECT 763.760 4.080 764.960 1565.360 ;
      RECT 774.640 4.080 775.840 1565.360 ;
      RECT 785.520 4.080 786.720 1565.360 ;
      RECT 796.400 4.080 797.600 1565.360 ;
      RECT 807.280 4.080 808.480 1565.360 ;
      RECT 818.160 4.080 819.360 1565.360 ;
      RECT 829.040 4.080 830.240 1565.360 ;
      RECT 839.920 4.080 841.120 1565.360 ;
      RECT 850.800 4.080 852.000 1565.360 ;
      RECT 861.680 4.080 862.880 1565.360 ;
      RECT 872.560 4.080 873.760 1565.360 ;
      RECT 883.440 4.080 884.640 1565.360 ;
      RECT 894.320 4.080 895.520 1565.360 ;
      RECT 905.200 4.080 906.400 1565.360 ;
      RECT 916.080 4.080 917.280 1565.360 ;
      RECT 926.960 4.080 928.160 1565.360 ;
      RECT 937.840 4.080 939.040 1565.360 ;
      RECT 948.720 4.080 949.920 1565.360 ;
      RECT 959.600 4.080 960.800 1565.360 ;
      RECT 970.480 4.080 971.680 1565.360 ;
      RECT 981.360 4.080 982.560 1565.360 ;
      RECT 992.240 4.080 993.440 1565.360 ;
      RECT 1003.120 4.080 1004.320 1565.360 ;
      RECT 1014.000 4.080 1015.200 1565.360 ;
      RECT 1024.880 4.080 1026.080 1565.360 ;
      RECT 1035.760 4.080 1036.960 1565.360 ;
      RECT 1046.640 4.080 1047.840 1565.360 ;
      RECT 1057.520 4.080 1058.720 1565.360 ;
      RECT 1068.400 4.080 1069.600 1565.360 ;
      RECT 1079.280 4.080 1080.480 1565.360 ;
      RECT 1090.160 4.080 1091.360 1565.360 ;
      RECT 1101.040 4.080 1102.240 1565.360 ;
      RECT 1111.920 4.080 1113.120 1565.360 ;
      RECT 1122.800 4.080 1124.000 1565.360 ;
      RECT 1133.680 4.080 1134.880 1565.360 ;
      RECT 1144.560 4.080 1145.760 1565.360 ;
      RECT 1155.440 4.080 1156.640 1565.360 ;
      RECT 1166.320 4.080 1167.520 1565.360 ;
      RECT 1177.200 4.080 1178.400 1565.360 ;
      RECT 1188.080 4.080 1189.280 1565.360 ;
      RECT 1198.960 4.080 1200.160 1565.360 ;
      RECT 1209.840 4.080 1211.040 1565.360 ;
      RECT 1220.720 4.080 1221.920 1565.360 ;
      RECT 1231.600 4.080 1232.800 1565.360 ;
      RECT 1242.480 4.080 1243.680 1565.360 ;
      RECT 1253.360 4.080 1254.560 1565.360 ;
      RECT 1264.240 4.080 1265.440 1565.360 ;
      RECT 1275.120 4.080 1276.320 1565.360 ;
      RECT 1286.000 4.080 1287.200 1565.360 ;
      RECT 1296.880 4.080 1298.080 1565.360 ;
    END
  END VSS
  PIN VDD
    DIRECTION INOUT ;
    USE POWER ;
    PORT
      LAYER met4 ;
      RECT 2.160 4.080 3.360 1565.360 ;
      RECT 13.040 4.080 14.240 1565.360 ;
      RECT 23.920 4.080 25.120 1565.360 ;
      RECT 34.800 4.080 36.000 1565.360 ;
      RECT 45.680 4.080 46.880 1565.360 ;
      RECT 56.560 4.080 57.760 1565.360 ;
      RECT 67.440 4.080 68.640 1565.360 ;
      RECT 78.320 4.080 79.520 1565.360 ;
      RECT 89.200 4.080 90.400 1565.360 ;
      RECT 100.080 4.080 101.280 1565.360 ;
      RECT 110.960 4.080 112.160 1565.360 ;
      RECT 121.840 4.080 123.040 1565.360 ;
      RECT 132.720 4.080 133.920 1565.360 ;
      RECT 143.600 4.080 144.800 1565.360 ;
      RECT 154.480 4.080 155.680 1565.360 ;
      RECT 165.360 4.080 166.560 1565.360 ;
      RECT 176.240 4.080 177.440 1565.360 ;
      RECT 187.120 4.080 188.320 1565.360 ;
      RECT 198.000 4.080 199.200 1565.360 ;
      RECT 208.880 4.080 210.080 1565.360 ;
      RECT 219.760 4.080 220.960 1565.360 ;
      RECT 230.640 4.080 231.840 1565.360 ;
      RECT 241.520 4.080 242.720 1565.360 ;
      RECT 252.400 4.080 253.600 1565.360 ;
      RECT 263.280 4.080 264.480 1565.360 ;
      RECT 274.160 4.080 275.360 1565.360 ;
      RECT 285.040 4.080 286.240 1565.360 ;
      RECT 295.920 4.080 297.120 1565.360 ;
      RECT 306.800 4.080 308.000 1565.360 ;
      RECT 317.680 4.080 318.880 1565.360 ;
      RECT 328.560 4.080 329.760 1565.360 ;
      RECT 339.440 4.080 340.640 1565.360 ;
      RECT 350.320 4.080 351.520 1565.360 ;
      RECT 361.200 4.080 362.400 1565.360 ;
      RECT 372.080 4.080 373.280 1565.360 ;
      RECT 382.960 4.080 384.160 1565.360 ;
      RECT 393.840 4.080 395.040 1565.360 ;
      RECT 404.720 4.080 405.920 1565.360 ;
      RECT 415.600 4.080 416.800 1565.360 ;
      RECT 426.480 4.080 427.680 1565.360 ;
      RECT 437.360 4.080 438.560 1565.360 ;
      RECT 448.240 4.080 449.440 1565.360 ;
      RECT 459.120 4.080 460.320 1565.360 ;
      RECT 470.000 4.080 471.200 1565.360 ;
      RECT 480.880 4.080 482.080 1565.360 ;
      RECT 491.760 4.080 492.960 1565.360 ;
      RECT 502.640 4.080 503.840 1565.360 ;
      RECT 513.520 4.080 514.720 1565.360 ;
      RECT 524.400 4.080 525.600 1565.360 ;
      RECT 535.280 4.080 536.480 1565.360 ;
      RECT 546.160 4.080 547.360 1565.360 ;
      RECT 557.040 4.080 558.240 1565.360 ;
      RECT 567.920 4.080 569.120 1565.360 ;
      RECT 578.800 4.080 580.000 1565.360 ;
      RECT 589.680 4.080 590.880 1565.360 ;
      RECT 600.560 4.080 601.760 1565.360 ;
      RECT 611.440 4.080 612.640 1565.360 ;
      RECT 622.320 4.080 623.520 1565.360 ;
      RECT 633.200 4.080 634.400 1565.360 ;
      RECT 644.080 4.080 645.280 1565.360 ;
      RECT 654.960 4.080 656.160 1565.360 ;
      RECT 665.840 4.080 667.040 1565.360 ;
      RECT 676.720 4.080 677.920 1565.360 ;
      RECT 687.600 4.080 688.800 1565.360 ;
      RECT 698.480 4.080 699.680 1565.360 ;
      RECT 709.360 4.080 710.560 1565.360 ;
      RECT 720.240 4.080 721.440 1565.360 ;
      RECT 731.120 4.080 732.320 1565.360 ;
      RECT 742.000 4.080 743.200 1565.360 ;
      RECT 752.880 4.080 754.080 1565.360 ;
      RECT 763.760 4.080 764.960 1565.360 ;
      RECT 774.640 4.080 775.840 1565.360 ;
      RECT 785.520 4.080 786.720 1565.360 ;
      RECT 796.400 4.080 797.600 1565.360 ;
      RECT 807.280 4.080 808.480 1565.360 ;
      RECT 818.160 4.080 819.360 1565.360 ;
      RECT 829.040 4.080 830.240 1565.360 ;
      RECT 839.920 4.080 841.120 1565.360 ;
      RECT 850.800 4.080 852.000 1565.360 ;
      RECT 861.680 4.080 862.880 1565.360 ;
      RECT 872.560 4.080 873.760 1565.360 ;
      RECT 883.440 4.080 884.640 1565.360 ;
      RECT 894.320 4.080 895.520 1565.360 ;
      RECT 905.200 4.080 906.400 1565.360 ;
      RECT 916.080 4.080 917.280 1565.360 ;
      RECT 926.960 4.080 928.160 1565.360 ;
      RECT 937.840 4.080 939.040 1565.360 ;
      RECT 948.720 4.080 949.920 1565.360 ;
      RECT 959.600 4.080 960.800 1565.360 ;
      RECT 970.480 4.080 971.680 1565.360 ;
      RECT 981.360 4.080 982.560 1565.360 ;
      RECT 992.240 4.080 993.440 1565.360 ;
      RECT 1003.120 4.080 1004.320 1565.360 ;
      RECT 1014.000 4.080 1015.200 1565.360 ;
      RECT 1024.880 4.080 1026.080 1565.360 ;
      RECT 1035.760 4.080 1036.960 1565.360 ;
      RECT 1046.640 4.080 1047.840 1565.360 ;
      RECT 1057.520 4.080 1058.720 1565.360 ;
      RECT 1068.400 4.080 1069.600 1565.360 ;
      RECT 1079.280 4.080 1080.480 1565.360 ;
      RECT 1090.160 4.080 1091.360 1565.360 ;
      RECT 1101.040 4.080 1102.240 1565.360 ;
      RECT 1111.920 4.080 1113.120 1565.360 ;
      RECT 1122.800 4.080 1124.000 1565.360 ;
      RECT 1133.680 4.080 1134.880 1565.360 ;
      RECT 1144.560 4.080 1145.760 1565.360 ;
      RECT 1155.440 4.080 1156.640 1565.360 ;
      RECT 1166.320 4.080 1167.520 1565.360 ;
      RECT 1177.200 4.080 1178.400 1565.360 ;
      RECT 1188.080 4.080 1189.280 1565.360 ;
      RECT 1198.960 4.080 1200.160 1565.360 ;
      RECT 1209.840 4.080 1211.040 1565.360 ;
      RECT 1220.720 4.080 1221.920 1565.360 ;
      RECT 1231.600 4.080 1232.800 1565.360 ;
      RECT 1242.480 4.080 1243.680 1565.360 ;
      RECT 1253.360 4.080 1254.560 1565.360 ;
      RECT 1264.240 4.080 1265.440 1565.360 ;
      RECT 1275.120 4.080 1276.320 1565.360 ;
      RECT 1286.000 4.080 1287.200 1565.360 ;
      RECT 1296.880 4.080 1298.080 1565.360 ;
    END
  END VDD
  OBS
    LAYER met1 ;
    RECT 0 0 1302.720 1569.440 ;
    LAYER met2 ;
    RECT 0 0 1302.720 1569.440 ;
    LAYER met3 ;
    RECT 0 0 1302.720 1569.440 ;
    LAYER met4 ;
    RECT 0 0 1302.720 1569.440 ;
  END
END fakeram_512x256_1r1w

END LIBRARY
